VERSION 5.8 ;
BUSBITCHARS "[]" ;
DIVIDERCHAR "/" ;
UNITS
    DATABASE MICRONS 2000 ;
END UNITS

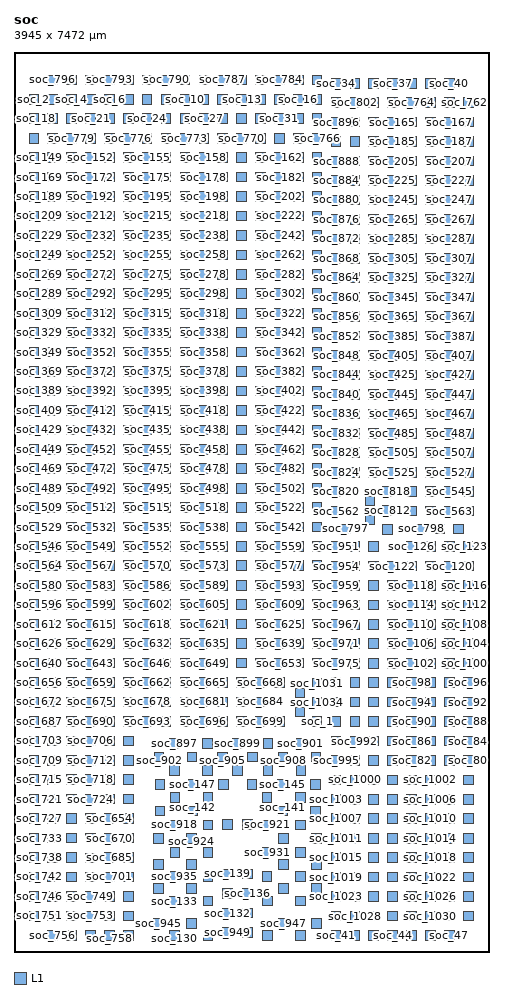
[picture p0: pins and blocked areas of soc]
MACRO soc
  FOREIGN soc 0 0 ;
  CLASS BLOCK ;
  SIZE 3945 BY 7472 ;
  PIN soc_1
    DIRECTION INOUT ;
    USE SIGNAL ;
    PORT
      LAYER L1 ;
        RECT  2476.881 1874.7005 2556.881 1954.7005 ;
    END
  END soc_1
  PIN soc_10
    DIRECTION INOUT ;
    USE SIGNAL ;
    PORT
      LAYER L1 ;
        RECT  1379.281 7039.1995 1459.281 7119.1995 ;
    END
  END soc_10
  PIN soc_100
    DIRECTION INOUT ;
    USE SIGNAL ;
    PORT
      LAYER L1 ;
        RECT  3731.281 2357.4025 3811.281 2437.4025 ;
    END
  END soc_100
  PIN soc_1000
    DIRECTION INOUT ;
    USE SIGNAL ;
    PORT
      LAYER L1 ;
        RECT  2790.481 1388.7545 2870.481 1468.7545 ;
    END
  END soc_1000
  PIN soc_1001
    DIRECTION INOUT ;
    USE SIGNAL ;
    PORT
      LAYER L1 ;
        RECT  2947.281 1388.7545 3027.281 1468.7545 ;
    END
  END soc_1001
  PIN soc_1002
    DIRECTION INOUT ;
    USE SIGNAL ;
    PORT
      LAYER L1 ;
        RECT  3417.681 1388.7545 3497.681 1468.7545 ;
    END
  END soc_1002
  PIN soc_1003
    DIRECTION INOUT ;
    USE SIGNAL ;
    PORT
      LAYER L1 ;
        RECT  2633.681 1227.3135 2713.681 1307.3135 ;
    END
  END soc_1003
  PIN soc_1004
    DIRECTION INOUT ;
    USE SIGNAL ;
    PORT
      LAYER L1 ;
        RECT  2790.481 1227.3135 2870.481 1307.3135 ;
    END
  END soc_1004
  PIN soc_1005
    DIRECTION INOUT ;
    USE SIGNAL ;
    PORT
      LAYER L1 ;
        RECT  2947.281 1227.3135 3027.281 1307.3135 ;
    END
  END soc_1005
  PIN soc_1006
    DIRECTION INOUT ;
    USE SIGNAL ;
    PORT
      LAYER L1 ;
        RECT  3417.681 1227.3135 3497.681 1307.3135 ;
    END
  END soc_1006
  PIN soc_1007
    DIRECTION INOUT ;
    USE SIGNAL ;
    PORT
      LAYER L1 ;
        RECT  2633.681 1065.872 2713.681 1145.872 ;
    END
  END soc_1007
  PIN soc_1008
    DIRECTION INOUT ;
    USE SIGNAL ;
    PORT
      LAYER L1 ;
        RECT  2790.481 1065.872 2870.481 1145.872 ;
    END
  END soc_1008
  PIN soc_1009
    DIRECTION INOUT ;
    USE SIGNAL ;
    PORT
      LAYER L1 ;
        RECT  2947.281 1065.872 3027.281 1145.872 ;
    END
  END soc_1009
  PIN soc_101
    DIRECTION INOUT ;
    USE SIGNAL ;
    PORT
      LAYER L1 ;
        RECT  3574.481 2357.4025 3654.481 2437.4025 ;
    END
  END soc_101
  PIN soc_1010
    DIRECTION INOUT ;
    USE SIGNAL ;
    PORT
      LAYER L1 ;
        RECT  3417.681 1065.872 3497.681 1145.872 ;
    END
  END soc_1010
  PIN soc_1011
    DIRECTION INOUT ;
    USE SIGNAL ;
    PORT
      LAYER L1 ;
        RECT  2633.681 904.431 2713.681 984.431 ;
    END
  END soc_1011
  PIN soc_1012
    DIRECTION INOUT ;
    USE SIGNAL ;
    PORT
      LAYER L1 ;
        RECT  2790.481 904.431 2870.481 984.431 ;
    END
  END soc_1012
  PIN soc_1013
    DIRECTION INOUT ;
    USE SIGNAL ;
    PORT
      LAYER L1 ;
        RECT  2947.281 904.431 3027.281 984.431 ;
    END
  END soc_1013
  PIN soc_1014
    DIRECTION INOUT ;
    USE SIGNAL ;
    PORT
      LAYER L1 ;
        RECT  3417.681 904.431 3497.681 984.431 ;
    END
  END soc_1014
  PIN soc_1015
    DIRECTION INOUT ;
    USE SIGNAL ;
    PORT
      LAYER L1 ;
        RECT  2633.681 742.9895 2713.681 822.9895 ;
    END
  END soc_1015
  PIN soc_1016
    DIRECTION INOUT ;
    USE SIGNAL ;
    PORT
      LAYER L1 ;
        RECT  2790.481 742.9895 2870.481 822.9895 ;
    END
  END soc_1016
  PIN soc_1017
    DIRECTION INOUT ;
    USE SIGNAL ;
    PORT
      LAYER L1 ;
        RECT  2947.281 742.9895 3027.281 822.9895 ;
    END
  END soc_1017
  PIN soc_1018
    DIRECTION INOUT ;
    USE SIGNAL ;
    PORT
      LAYER L1 ;
        RECT  3417.681 742.9895 3497.681 822.9895 ;
    END
  END soc_1018
  PIN soc_1019
    DIRECTION INOUT ;
    USE SIGNAL ;
    PORT
      LAYER L1 ;
        RECT  2633.681 581.5485 2713.681 661.5485 ;
    END
  END soc_1019
  PIN soc_102
    DIRECTION INOUT ;
    USE SIGNAL ;
    PORT
      LAYER L1 ;
        RECT  3260.881 2357.4025 3340.881 2437.4025 ;
    END
  END soc_102
  PIN soc_1020
    DIRECTION INOUT ;
    USE SIGNAL ;
    PORT
      LAYER L1 ;
        RECT  2790.481 581.5485 2870.481 661.5485 ;
    END
  END soc_1020
  PIN soc_1021
    DIRECTION INOUT ;
    USE SIGNAL ;
    PORT
      LAYER L1 ;
        RECT  2947.281 581.5485 3027.281 661.5485 ;
    END
  END soc_1021
  PIN soc_1022
    DIRECTION INOUT ;
    USE SIGNAL ;
    PORT
      LAYER L1 ;
        RECT  3417.681 581.5485 3497.681 661.5485 ;
    END
  END soc_1022
  PIN soc_1023
    DIRECTION INOUT ;
    USE SIGNAL ;
    PORT
      LAYER L1 ;
        RECT  2633.681 420.107 2713.681 500.107 ;
    END
  END soc_1023
  PIN soc_1024
    DIRECTION INOUT ;
    USE SIGNAL ;
    PORT
      LAYER L1 ;
        RECT  2790.481 420.107 2870.481 500.107 ;
    END
  END soc_1024
  PIN soc_1025
    DIRECTION INOUT ;
    USE SIGNAL ;
    PORT
      LAYER L1 ;
        RECT  2947.281 420.107 3027.281 500.107 ;
    END
  END soc_1025
  PIN soc_1026
    DIRECTION INOUT ;
    USE SIGNAL ;
    PORT
      LAYER L1 ;
        RECT  3417.681 420.107 3497.681 500.107 ;
    END
  END soc_1026
  PIN soc_1027
    DIRECTION INOUT ;
    USE SIGNAL ;
    PORT
      LAYER L1 ;
        RECT  2633.681 258.666 2713.681 338.666 ;
    END
  END soc_1027
  PIN soc_1028
    DIRECTION INOUT ;
    USE SIGNAL ;
    PORT
      LAYER L1 ;
        RECT  2790.481 258.666 2870.481 338.666 ;
    END
  END soc_1028
  PIN soc_1029
    DIRECTION INOUT ;
    USE SIGNAL ;
    PORT
      LAYER L1 ;
        RECT  2947.281 258.666 3027.281 338.666 ;
    END
  END soc_1029
  PIN soc_103
    DIRECTION INOUT ;
    USE SIGNAL ;
    PORT
      LAYER L1 ;
        RECT  3104.081 2357.4025 3184.081 2437.4025 ;
    END
  END soc_103
  PIN soc_1030
    DIRECTION INOUT ;
    USE SIGNAL ;
    PORT
      LAYER L1 ;
        RECT  3417.681 258.666 3497.681 338.666 ;
    END
  END soc_1030
  PIN soc_1031
    DIRECTION INOUT ;
    USE SIGNAL ;
    PORT
      LAYER L1 ;
        RECT  2476.881 2188.3005 2556.881 2268.3005 ;
    END
  END soc_1031
  PIN soc_1032
    DIRECTION INOUT ;
    USE SIGNAL ;
    PORT
      LAYER L1 ;
        RECT  2333.5325 2109.9005 2413.5325 2189.9005 ;
    END
  END soc_1032
  PIN soc_1033
    DIRECTION INOUT ;
    USE SIGNAL ;
    PORT
      LAYER L1 ;
        RECT  2333.5325 1953.1005 2413.5325 2033.1005 ;
    END
  END soc_1033
  PIN soc_1034
    DIRECTION INOUT ;
    USE SIGNAL ;
    PORT
      LAYER L1 ;
        RECT  2476.881 2031.5005 2556.881 2111.5005 ;
    END
  END soc_1034
  PIN soc_104
    DIRECTION INOUT ;
    USE SIGNAL ;
    PORT
      LAYER L1 ;
        RECT  3731.281 2518.8435 3811.281 2598.8435 ;
    END
  END soc_104
  PIN soc_105
    DIRECTION INOUT ;
    USE SIGNAL ;
    PORT
      LAYER L1 ;
        RECT  3574.481 2518.8435 3654.481 2598.8435 ;
    END
  END soc_105
  PIN soc_106
    DIRECTION INOUT ;
    USE SIGNAL ;
    PORT
      LAYER L1 ;
        RECT  3260.881 2518.8435 3340.881 2598.8435 ;
    END
  END soc_106
  PIN soc_107
    DIRECTION INOUT ;
    USE SIGNAL ;
    PORT
      LAYER L1 ;
        RECT  3104.081 2518.8435 3184.081 2598.8435 ;
    END
  END soc_107
  PIN soc_108
    DIRECTION INOUT ;
    USE SIGNAL ;
    PORT
      LAYER L1 ;
        RECT  3731.281 2680.285 3811.281 2760.285 ;
    END
  END soc_108
  PIN soc_109
    DIRECTION INOUT ;
    USE SIGNAL ;
    PORT
      LAYER L1 ;
        RECT  3574.481 2680.285 3654.481 2760.285 ;
    END
  END soc_109
  PIN soc_11
    DIRECTION INOUT ;
    USE SIGNAL ;
    PORT
      LAYER L1 ;
        RECT  1536.081 7039.1995 1616.081 7119.1995 ;
    END
  END soc_11
  PIN soc_110
    DIRECTION INOUT ;
    USE SIGNAL ;
    PORT
      LAYER L1 ;
        RECT  3260.881 2680.285 3340.881 2760.285 ;
    END
  END soc_110
  PIN soc_111
    DIRECTION INOUT ;
    USE SIGNAL ;
    PORT
      LAYER L1 ;
        RECT  3104.081 2680.285 3184.081 2760.285 ;
    END
  END soc_111
  PIN soc_112
    DIRECTION INOUT ;
    USE SIGNAL ;
    PORT
      LAYER L1 ;
        RECT  3731.281 2841.7265 3811.281 2921.7265 ;
    END
  END soc_112
  PIN soc_113
    DIRECTION INOUT ;
    USE SIGNAL ;
    PORT
      LAYER L1 ;
        RECT  3574.481 2841.7265 3654.481 2921.7265 ;
    END
  END soc_113
  PIN soc_114
    DIRECTION INOUT ;
    USE SIGNAL ;
    PORT
      LAYER L1 ;
        RECT  3260.881 2841.7265 3340.881 2921.7265 ;
    END
  END soc_114
  PIN soc_115
    DIRECTION INOUT ;
    USE SIGNAL ;
    PORT
      LAYER L1 ;
        RECT  3104.081 2841.7265 3184.081 2921.7265 ;
    END
  END soc_115
  PIN soc_116
    DIRECTION INOUT ;
    USE SIGNAL ;
    PORT
      LAYER L1 ;
        RECT  3731.281 3003.1675 3811.281 3083.1675 ;
    END
  END soc_116
  PIN soc_117
    DIRECTION INOUT ;
    USE SIGNAL ;
    PORT
      LAYER L1 ;
        RECT  3574.481 3003.1675 3654.481 3083.1675 ;
    END
  END soc_117
  PIN soc_118
    DIRECTION INOUT ;
    USE SIGNAL ;
    PORT
      LAYER L1 ;
        RECT  3260.881 3003.1675 3340.881 3083.1675 ;
    END
  END soc_118
  PIN soc_119
    DIRECTION INOUT ;
    USE SIGNAL ;
    PORT
      LAYER L1 ;
        RECT  3104.081 3003.1675 3184.081 3083.1675 ;
    END
  END soc_119
  PIN soc_12
    DIRECTION INOUT ;
    USE SIGNAL ;
    PORT
      LAYER L1 ;
        RECT  1692.881 7039.1995 1772.881 7119.1995 ;
    END
  END soc_12
  PIN soc_120
    DIRECTION INOUT ;
    USE SIGNAL ;
    PORT
      LAYER L1 ;
        RECT  3574.481 3164.609 3654.481 3244.609 ;
    END
  END soc_120
  PIN soc_121
    DIRECTION INOUT ;
    USE SIGNAL ;
    PORT
      LAYER L1 ;
        RECT  3260.881 3164.609 3340.881 3244.609 ;
    END
  END soc_121
  PIN soc_122
    DIRECTION INOUT ;
    USE SIGNAL ;
    PORT
      LAYER L1 ;
        RECT  3104.081 3164.609 3184.081 3244.609 ;
    END
  END soc_122
  PIN soc_123
    DIRECTION INOUT ;
    USE SIGNAL ;
    PORT
      LAYER L1 ;
        RECT  3731.281 3326.05 3811.281 3406.05 ;
    END
  END soc_123
  PIN soc_124
    DIRECTION INOUT ;
    USE SIGNAL ;
    PORT
      LAYER L1 ;
        RECT  3574.481 3326.05 3654.481 3406.05 ;
    END
  END soc_124
  PIN soc_125
    DIRECTION INOUT ;
    USE SIGNAL ;
    PORT
      LAYER L1 ;
        RECT  3417.681 3326.05 3497.681 3406.05 ;
    END
  END soc_125
  PIN soc_126
    DIRECTION INOUT ;
    USE SIGNAL ;
    PORT
      LAYER L1 ;
        RECT  3260.881 3326.05 3340.881 3406.05 ;
    END
  END soc_126
  PIN soc_127
    DIRECTION INOUT ;
    USE SIGNAL ;
    PORT
      LAYER L1 ;
        RECT  2337.637 98.8385 2417.637 178.8385 ;
    END
  END soc_127
  PIN soc_128
    DIRECTION INOUT ;
    USE SIGNAL ;
    PORT
      LAYER L1 ;
        RECT  2063.237 98.8385 2143.237 178.8385 ;
    END
  END soc_128
  PIN soc_129
    DIRECTION INOUT ;
    USE SIGNAL ;
    PORT
      LAYER L1 ;
        RECT  1569.317 98.8385 1649.317 178.8385 ;
    END
  END soc_129
  PIN soc_13
    DIRECTION INOUT ;
    USE SIGNAL ;
    PORT
      LAYER L1 ;
        RECT  1849.681 7039.1995 1929.681 7119.1995 ;
    END
  END soc_13
  PIN soc_130
    DIRECTION INOUT ;
    USE SIGNAL ;
    PORT
      LAYER L1 ;
        RECT  1294.917 98.8385 1374.917 178.8385 ;
    END
  END soc_130
  PIN soc_131
    DIRECTION INOUT ;
    USE SIGNAL ;
    PORT
      LAYER L1 ;
        RECT  1898.597 282.663 1978.597 362.663 ;
    END
  END soc_131
  PIN soc_132
    DIRECTION INOUT ;
    USE SIGNAL ;
    PORT
      LAYER L1 ;
        RECT  1733.957 282.663 1813.957 362.663 ;
    END
  END soc_132
  PIN soc_133
    DIRECTION INOUT ;
    USE SIGNAL ;
    PORT
      LAYER L1 ;
        RECT  1294.917 383.1015 1374.917 463.1015 ;
    END
  END soc_133
  PIN soc_134
    DIRECTION INOUT ;
    USE SIGNAL ;
    PORT
      LAYER L1 ;
        RECT  2337.637 383.1015 2417.637 463.1015 ;
    END
  END soc_134
  PIN soc_135
    DIRECTION INOUT ;
    USE SIGNAL ;
    PORT
      LAYER L1 ;
        RECT  2063.237 383.1015 2143.237 463.1015 ;
    END
  END soc_135
  PIN soc_136
    DIRECTION INOUT ;
    USE SIGNAL ;
    PORT
      LAYER L1 ;
        RECT  1898.597 445.343 1978.597 525.343 ;
    END
  END soc_136
  PIN soc_137
    DIRECTION INOUT ;
    USE SIGNAL ;
    PORT
      LAYER L1 ;
        RECT  1733.957 445.343 1813.957 525.343 ;
    END
  END soc_137
  PIN soc_138
    DIRECTION INOUT ;
    USE SIGNAL ;
    PORT
      LAYER L1 ;
        RECT  1569.317 383.1015 1649.317 463.1015 ;
    END
  END soc_138
  PIN soc_139
    DIRECTION INOUT ;
    USE SIGNAL ;
    PORT
      LAYER L1 ;
        RECT  1733.957 608.023 1813.957 688.023 ;
    END
  END soc_139
  PIN soc_14
    DIRECTION INOUT ;
    USE SIGNAL ;
    PORT
      LAYER L1 ;
        RECT  2006.481 7039.1995 2086.481 7119.1995 ;
    END
  END soc_14
  PIN soc_140
    DIRECTION INOUT ;
    USE SIGNAL ;
    PORT
      LAYER L1 ;
        RECT  2461.244 1130.4435 2541.244 1210.4435 ;
    END
  END soc_140
  PIN soc_141
    DIRECTION INOUT ;
    USE SIGNAL ;
    PORT
      LAYER L1 ;
        RECT  2186.844 1130.4435 2266.844 1210.4435 ;
    END
  END soc_141
  PIN soc_142
    DIRECTION INOUT ;
    USE SIGNAL ;
    PORT
      LAYER L1 ;
        RECT  1445.7095 1130.4435 1525.7095 1210.4435 ;
    END
  END soc_142
  PIN soc_143
    DIRECTION INOUT ;
    USE SIGNAL ;
    PORT
      LAYER L1 ;
        RECT  1171.3095 1130.4435 1251.3095 1210.4435 ;
    END
  END soc_143
  PIN soc_144
    DIRECTION INOUT ;
    USE SIGNAL ;
    PORT
      LAYER L1 ;
        RECT  2461.244 1351.3195 2541.244 1431.3195 ;
    END
  END soc_144
  PIN soc_145
    DIRECTION INOUT ;
    USE SIGNAL ;
    PORT
      LAYER L1 ;
        RECT  2186.844 1351.3195 2266.844 1431.3195 ;
    END
  END soc_145
  PIN soc_146
    DIRECTION INOUT ;
    USE SIGNAL ;
    PORT
      LAYER L1 ;
        RECT  1934.8645 1351.3195 2014.8645 1431.3195 ;
    END
  END soc_146
  PIN soc_147
    DIRECTION INOUT ;
    USE SIGNAL ;
    PORT
      LAYER L1 ;
        RECT  1445.7095 1351.3195 1525.7095 1431.3195 ;
    END
  END soc_147
  PIN soc_148
    DIRECTION INOUT ;
    USE SIGNAL ;
    PORT
      LAYER L1 ;
        RECT  1171.3095 1351.3195 1251.3095 1431.3195 ;
    END
  END soc_148
  PIN soc_149
    DIRECTION INOUT ;
    USE SIGNAL ;
    PORT
      LAYER L1 ;
        RECT  124.881 6554.8755 204.881 6634.8755 ;
    END
  END soc_149
  PIN soc_15
    DIRECTION INOUT ;
    USE SIGNAL ;
    PORT
      LAYER L1 ;
        RECT  2163.281 7039.1995 2243.281 7119.1995 ;
    END
  END soc_15
  PIN soc_150
    DIRECTION INOUT ;
    USE SIGNAL ;
    PORT
      LAYER L1 ;
        RECT  281.681 6554.8755 361.681 6634.8755 ;
    END
  END soc_150
  PIN soc_151
    DIRECTION INOUT ;
    USE SIGNAL ;
    PORT
      LAYER L1 ;
        RECT  438.481 6554.8755 518.481 6634.8755 ;
    END
  END soc_151
  PIN soc_152
    DIRECTION INOUT ;
    USE SIGNAL ;
    PORT
      LAYER L1 ;
        RECT  595.281 6554.8755 675.281 6634.8755 ;
    END
  END soc_152
  PIN soc_153
    DIRECTION INOUT ;
    USE SIGNAL ;
    PORT
      LAYER L1 ;
        RECT  752.081 6554.8755 832.081 6634.8755 ;
    END
  END soc_153
  PIN soc_154
    DIRECTION INOUT ;
    USE SIGNAL ;
    PORT
      LAYER L1 ;
        RECT  908.881 6554.8755 988.881 6634.8755 ;
    END
  END soc_154
  PIN soc_155
    DIRECTION INOUT ;
    USE SIGNAL ;
    PORT
      LAYER L1 ;
        RECT  1065.681 6554.8755 1145.681 6634.8755 ;
    END
  END soc_155
  PIN soc_156
    DIRECTION INOUT ;
    USE SIGNAL ;
    PORT
      LAYER L1 ;
        RECT  1222.481 6554.8755 1302.481 6634.8755 ;
    END
  END soc_156
  PIN soc_157
    DIRECTION INOUT ;
    USE SIGNAL ;
    PORT
      LAYER L1 ;
        RECT  1379.281 6554.8755 1459.281 6634.8755 ;
    END
  END soc_157
  PIN soc_158
    DIRECTION INOUT ;
    USE SIGNAL ;
    PORT
      LAYER L1 ;
        RECT  1536.081 6554.8755 1616.081 6634.8755 ;
    END
  END soc_158
  PIN soc_159
    DIRECTION INOUT ;
    USE SIGNAL ;
    PORT
      LAYER L1 ;
        RECT  1692.881 6554.8755 1772.881 6634.8755 ;
    END
  END soc_159
  PIN soc_16
    DIRECTION INOUT ;
    USE SIGNAL ;
    PORT
      LAYER L1 ;
        RECT  2320.081 7039.1995 2400.081 7119.1995 ;
    END
  END soc_16
  PIN soc_160
    DIRECTION INOUT ;
    USE SIGNAL ;
    PORT
      LAYER L1 ;
        RECT  1849.681 6554.8755 1929.681 6634.8755 ;
    END
  END soc_160
  PIN soc_161
    DIRECTION INOUT ;
    USE SIGNAL ;
    PORT
      LAYER L1 ;
        RECT  2006.481 6554.8755 2086.481 6634.8755 ;
    END
  END soc_161
  PIN soc_162
    DIRECTION INOUT ;
    USE SIGNAL ;
    PORT
      LAYER L1 ;
        RECT  2163.281 6554.8755 2243.281 6634.8755 ;
    END
  END soc_162
  PIN soc_163
    DIRECTION INOUT ;
    USE SIGNAL ;
    PORT
      LAYER L1 ;
        RECT  2320.081 6554.8755 2400.081 6634.8755 ;
    END
  END soc_163
  PIN soc_164
    DIRECTION INOUT ;
    USE SIGNAL ;
    PORT
      LAYER L1 ;
        RECT  2476.881 6554.8755 2556.881 6634.8755 ;
    END
  END soc_164
  PIN soc_165
    DIRECTION INOUT ;
    USE SIGNAL ;
    PORT
      LAYER L1 ;
        RECT  3104.081 6849.4225 3184.081 6929.4225 ;
    END
  END soc_165
  PIN soc_166
    DIRECTION INOUT ;
    USE SIGNAL ;
    PORT
      LAYER L1 ;
        RECT  3260.881 6849.4225 3340.881 6929.4225 ;
    END
  END soc_166
  PIN soc_167
    DIRECTION INOUT ;
    USE SIGNAL ;
    PORT
      LAYER L1 ;
        RECT  3574.481 6849.4225 3654.481 6929.4225 ;
    END
  END soc_167
  PIN soc_168
    DIRECTION INOUT ;
    USE SIGNAL ;
    PORT
      LAYER L1 ;
        RECT  3731.281 6849.4225 3811.281 6929.4225 ;
    END
  END soc_168
  PIN soc_169
    DIRECTION INOUT ;
    USE SIGNAL ;
    PORT
      LAYER L1 ;
        RECT  124.881 6393.4345 204.881 6473.4345 ;
    END
  END soc_169
  PIN soc_17
    DIRECTION INOUT ;
    USE SIGNAL ;
    PORT
      LAYER L1 ;
        RECT  2476.881 7039.1995 2556.881 7119.1995 ;
    END
  END soc_17
  PIN soc_170
    DIRECTION INOUT ;
    USE SIGNAL ;
    PORT
      LAYER L1 ;
        RECT  281.681 6393.4345 361.681 6473.4345 ;
    END
  END soc_170
  PIN soc_171
    DIRECTION INOUT ;
    USE SIGNAL ;
    PORT
      LAYER L1 ;
        RECT  438.481 6393.4345 518.481 6473.4345 ;
    END
  END soc_171
  PIN soc_172
    DIRECTION INOUT ;
    USE SIGNAL ;
    PORT
      LAYER L1 ;
        RECT  595.281 6393.4345 675.281 6473.4345 ;
    END
  END soc_172
  PIN soc_173
    DIRECTION INOUT ;
    USE SIGNAL ;
    PORT
      LAYER L1 ;
        RECT  752.081 6393.4345 832.081 6473.4345 ;
    END
  END soc_173
  PIN soc_174
    DIRECTION INOUT ;
    USE SIGNAL ;
    PORT
      LAYER L1 ;
        RECT  908.881 6393.4345 988.881 6473.4345 ;
    END
  END soc_174
  PIN soc_175
    DIRECTION INOUT ;
    USE SIGNAL ;
    PORT
      LAYER L1 ;
        RECT  1065.681 6393.4345 1145.681 6473.4345 ;
    END
  END soc_175
  PIN soc_176
    DIRECTION INOUT ;
    USE SIGNAL ;
    PORT
      LAYER L1 ;
        RECT  1222.481 6393.4345 1302.481 6473.4345 ;
    END
  END soc_176
  PIN soc_177
    DIRECTION INOUT ;
    USE SIGNAL ;
    PORT
      LAYER L1 ;
        RECT  1379.281 6393.4345 1459.281 6473.4345 ;
    END
  END soc_177
  PIN soc_178
    DIRECTION INOUT ;
    USE SIGNAL ;
    PORT
      LAYER L1 ;
        RECT  1536.081 6393.4345 1616.081 6473.4345 ;
    END
  END soc_178
  PIN soc_179
    DIRECTION INOUT ;
    USE SIGNAL ;
    PORT
      LAYER L1 ;
        RECT  1692.881 6393.4345 1772.881 6473.4345 ;
    END
  END soc_179
  PIN soc_18
    DIRECTION INOUT ;
    USE SIGNAL ;
    PORT
      LAYER L1 ;
        RECT  124.881 6877.7585 204.881 6957.7585 ;
    END
  END soc_18
  PIN soc_180
    DIRECTION INOUT ;
    USE SIGNAL ;
    PORT
      LAYER L1 ;
        RECT  1849.681 6393.4345 1929.681 6473.4345 ;
    END
  END soc_180
  PIN soc_181
    DIRECTION INOUT ;
    USE SIGNAL ;
    PORT
      LAYER L1 ;
        RECT  2006.481 6393.4345 2086.481 6473.4345 ;
    END
  END soc_181
  PIN soc_182
    DIRECTION INOUT ;
    USE SIGNAL ;
    PORT
      LAYER L1 ;
        RECT  2163.281 6393.4345 2243.281 6473.4345 ;
    END
  END soc_182
  PIN soc_183
    DIRECTION INOUT ;
    USE SIGNAL ;
    PORT
      LAYER L1 ;
        RECT  2320.081 6393.4345 2400.081 6473.4345 ;
    END
  END soc_183
  PIN soc_184
    DIRECTION INOUT ;
    USE SIGNAL ;
    PORT
      LAYER L1 ;
        RECT  2476.881 6393.4345 2556.881 6473.4345 ;
    END
  END soc_184
  PIN soc_185
    DIRECTION INOUT ;
    USE SIGNAL ;
    PORT
      LAYER L1 ;
        RECT  3104.081 6687.9815 3184.081 6767.9815 ;
    END
  END soc_185
  PIN soc_186
    DIRECTION INOUT ;
    USE SIGNAL ;
    PORT
      LAYER L1 ;
        RECT  3260.881 6687.9815 3340.881 6767.9815 ;
    END
  END soc_186
  PIN soc_187
    DIRECTION INOUT ;
    USE SIGNAL ;
    PORT
      LAYER L1 ;
        RECT  3574.481 6687.9815 3654.481 6767.9815 ;
    END
  END soc_187
  PIN soc_188
    DIRECTION INOUT ;
    USE SIGNAL ;
    PORT
      LAYER L1 ;
        RECT  3731.281 6687.9815 3811.281 6767.9815 ;
    END
  END soc_188
  PIN soc_189
    DIRECTION INOUT ;
    USE SIGNAL ;
    PORT
      LAYER L1 ;
        RECT  124.881 6231.993 204.881 6311.993 ;
    END
  END soc_189
  PIN soc_19
    DIRECTION INOUT ;
    USE SIGNAL ;
    PORT
      LAYER L1 ;
        RECT  281.681 6877.7585 361.681 6957.7585 ;
    END
  END soc_19
  PIN soc_190
    DIRECTION INOUT ;
    USE SIGNAL ;
    PORT
      LAYER L1 ;
        RECT  281.681 6231.993 361.681 6311.993 ;
    END
  END soc_190
  PIN soc_191
    DIRECTION INOUT ;
    USE SIGNAL ;
    PORT
      LAYER L1 ;
        RECT  438.481 6231.993 518.481 6311.993 ;
    END
  END soc_191
  PIN soc_192
    DIRECTION INOUT ;
    USE SIGNAL ;
    PORT
      LAYER L1 ;
        RECT  595.281 6231.993 675.281 6311.993 ;
    END
  END soc_192
  PIN soc_193
    DIRECTION INOUT ;
    USE SIGNAL ;
    PORT
      LAYER L1 ;
        RECT  752.081 6231.993 832.081 6311.993 ;
    END
  END soc_193
  PIN soc_194
    DIRECTION INOUT ;
    USE SIGNAL ;
    PORT
      LAYER L1 ;
        RECT  908.881 6231.993 988.881 6311.993 ;
    END
  END soc_194
  PIN soc_195
    DIRECTION INOUT ;
    USE SIGNAL ;
    PORT
      LAYER L1 ;
        RECT  1065.681 6231.993 1145.681 6311.993 ;
    END
  END soc_195
  PIN soc_196
    DIRECTION INOUT ;
    USE SIGNAL ;
    PORT
      LAYER L1 ;
        RECT  1222.481 6231.993 1302.481 6311.993 ;
    END
  END soc_196
  PIN soc_197
    DIRECTION INOUT ;
    USE SIGNAL ;
    PORT
      LAYER L1 ;
        RECT  1379.281 6231.993 1459.281 6311.993 ;
    END
  END soc_197
  PIN soc_198
    DIRECTION INOUT ;
    USE SIGNAL ;
    PORT
      LAYER L1 ;
        RECT  1536.081 6231.993 1616.081 6311.993 ;
    END
  END soc_198
  PIN soc_199
    DIRECTION INOUT ;
    USE SIGNAL ;
    PORT
      LAYER L1 ;
        RECT  1692.881 6231.993 1772.881 6311.993 ;
    END
  END soc_199
  PIN soc_2
    DIRECTION INOUT ;
    USE SIGNAL ;
    PORT
      LAYER L1 ;
        RECT  124.881 7039.1995 204.881 7119.1995 ;
    END
  END soc_2
  PIN soc_20
    DIRECTION INOUT ;
    USE SIGNAL ;
    PORT
      LAYER L1 ;
        RECT  438.481 6877.7585 518.481 6957.7585 ;
    END
  END soc_20
  PIN soc_200
    DIRECTION INOUT ;
    USE SIGNAL ;
    PORT
      LAYER L1 ;
        RECT  1849.681 6231.993 1929.681 6311.993 ;
    END
  END soc_200
  PIN soc_201
    DIRECTION INOUT ;
    USE SIGNAL ;
    PORT
      LAYER L1 ;
        RECT  2006.481 6231.993 2086.481 6311.993 ;
    END
  END soc_201
  PIN soc_202
    DIRECTION INOUT ;
    USE SIGNAL ;
    PORT
      LAYER L1 ;
        RECT  2163.281 6231.993 2243.281 6311.993 ;
    END
  END soc_202
  PIN soc_203
    DIRECTION INOUT ;
    USE SIGNAL ;
    PORT
      LAYER L1 ;
        RECT  2320.081 6231.993 2400.081 6311.993 ;
    END
  END soc_203
  PIN soc_204
    DIRECTION INOUT ;
    USE SIGNAL ;
    PORT
      LAYER L1 ;
        RECT  2476.881 6231.993 2556.881 6311.993 ;
    END
  END soc_204
  PIN soc_205
    DIRECTION INOUT ;
    USE SIGNAL ;
    PORT
      LAYER L1 ;
        RECT  3104.081 6526.54 3184.081 6606.54 ;
    END
  END soc_205
  PIN soc_206
    DIRECTION INOUT ;
    USE SIGNAL ;
    PORT
      LAYER L1 ;
        RECT  3260.881 6526.54 3340.881 6606.54 ;
    END
  END soc_206
  PIN soc_207
    DIRECTION INOUT ;
    USE SIGNAL ;
    PORT
      LAYER L1 ;
        RECT  3574.481 6526.54 3654.481 6606.54 ;
    END
  END soc_207
  PIN soc_208
    DIRECTION INOUT ;
    USE SIGNAL ;
    PORT
      LAYER L1 ;
        RECT  3731.281 6526.54 3811.281 6606.54 ;
    END
  END soc_208
  PIN soc_209
    DIRECTION INOUT ;
    USE SIGNAL ;
    PORT
      LAYER L1 ;
        RECT  124.881 6070.552 204.881 6150.552 ;
    END
  END soc_209
  PIN soc_21
    DIRECTION INOUT ;
    USE SIGNAL ;
    PORT
      LAYER L1 ;
        RECT  595.281 6877.7585 675.281 6957.7585 ;
    END
  END soc_21
  PIN soc_210
    DIRECTION INOUT ;
    USE SIGNAL ;
    PORT
      LAYER L1 ;
        RECT  281.681 6070.552 361.681 6150.552 ;
    END
  END soc_210
  PIN soc_211
    DIRECTION INOUT ;
    USE SIGNAL ;
    PORT
      LAYER L1 ;
        RECT  438.481 6070.552 518.481 6150.552 ;
    END
  END soc_211
  PIN soc_212
    DIRECTION INOUT ;
    USE SIGNAL ;
    PORT
      LAYER L1 ;
        RECT  595.281 6070.552 675.281 6150.552 ;
    END
  END soc_212
  PIN soc_213
    DIRECTION INOUT ;
    USE SIGNAL ;
    PORT
      LAYER L1 ;
        RECT  752.081 6070.552 832.081 6150.552 ;
    END
  END soc_213
  PIN soc_214
    DIRECTION INOUT ;
    USE SIGNAL ;
    PORT
      LAYER L1 ;
        RECT  908.881 6070.552 988.881 6150.552 ;
    END
  END soc_214
  PIN soc_215
    DIRECTION INOUT ;
    USE SIGNAL ;
    PORT
      LAYER L1 ;
        RECT  1065.681 6070.552 1145.681 6150.552 ;
    END
  END soc_215
  PIN soc_216
    DIRECTION INOUT ;
    USE SIGNAL ;
    PORT
      LAYER L1 ;
        RECT  1222.481 6070.552 1302.481 6150.552 ;
    END
  END soc_216
  PIN soc_217
    DIRECTION INOUT ;
    USE SIGNAL ;
    PORT
      LAYER L1 ;
        RECT  1379.281 6070.552 1459.281 6150.552 ;
    END
  END soc_217
  PIN soc_218
    DIRECTION INOUT ;
    USE SIGNAL ;
    PORT
      LAYER L1 ;
        RECT  1536.081 6070.552 1616.081 6150.552 ;
    END
  END soc_218
  PIN soc_219
    DIRECTION INOUT ;
    USE SIGNAL ;
    PORT
      LAYER L1 ;
        RECT  1692.881 6070.552 1772.881 6150.552 ;
    END
  END soc_219
  PIN soc_22
    DIRECTION INOUT ;
    USE SIGNAL ;
    PORT
      LAYER L1 ;
        RECT  752.081 6877.7585 832.081 6957.7585 ;
    END
  END soc_22
  PIN soc_220
    DIRECTION INOUT ;
    USE SIGNAL ;
    PORT
      LAYER L1 ;
        RECT  1849.681 6070.552 1929.681 6150.552 ;
    END
  END soc_220
  PIN soc_221
    DIRECTION INOUT ;
    USE SIGNAL ;
    PORT
      LAYER L1 ;
        RECT  2006.481 6070.552 2086.481 6150.552 ;
    END
  END soc_221
  PIN soc_222
    DIRECTION INOUT ;
    USE SIGNAL ;
    PORT
      LAYER L1 ;
        RECT  2163.281 6070.552 2243.281 6150.552 ;
    END
  END soc_222
  PIN soc_223
    DIRECTION INOUT ;
    USE SIGNAL ;
    PORT
      LAYER L1 ;
        RECT  2320.081 6070.552 2400.081 6150.552 ;
    END
  END soc_223
  PIN soc_224
    DIRECTION INOUT ;
    USE SIGNAL ;
    PORT
      LAYER L1 ;
        RECT  2476.881 6070.552 2556.881 6150.552 ;
    END
  END soc_224
  PIN soc_225
    DIRECTION INOUT ;
    USE SIGNAL ;
    PORT
      LAYER L1 ;
        RECT  3104.081 6365.0985 3184.081 6445.0985 ;
    END
  END soc_225
  PIN soc_226
    DIRECTION INOUT ;
    USE SIGNAL ;
    PORT
      LAYER L1 ;
        RECT  3260.881 6365.0985 3340.881 6445.0985 ;
    END
  END soc_226
  PIN soc_227
    DIRECTION INOUT ;
    USE SIGNAL ;
    PORT
      LAYER L1 ;
        RECT  3574.481 6365.0985 3654.481 6445.0985 ;
    END
  END soc_227
  PIN soc_228
    DIRECTION INOUT ;
    USE SIGNAL ;
    PORT
      LAYER L1 ;
        RECT  3731.281 6365.0985 3811.281 6445.0985 ;
    END
  END soc_228
  PIN soc_229
    DIRECTION INOUT ;
    USE SIGNAL ;
    PORT
      LAYER L1 ;
        RECT  124.881 5909.1105 204.881 5989.1105 ;
    END
  END soc_229
  PIN soc_23
    DIRECTION INOUT ;
    USE SIGNAL ;
    PORT
      LAYER L1 ;
        RECT  908.881 6877.7585 988.881 6957.7585 ;
    END
  END soc_23
  PIN soc_230
    DIRECTION INOUT ;
    USE SIGNAL ;
    PORT
      LAYER L1 ;
        RECT  281.681 5909.1105 361.681 5989.1105 ;
    END
  END soc_230
  PIN soc_231
    DIRECTION INOUT ;
    USE SIGNAL ;
    PORT
      LAYER L1 ;
        RECT  438.481 5909.1105 518.481 5989.1105 ;
    END
  END soc_231
  PIN soc_232
    DIRECTION INOUT ;
    USE SIGNAL ;
    PORT
      LAYER L1 ;
        RECT  595.281 5909.1105 675.281 5989.1105 ;
    END
  END soc_232
  PIN soc_233
    DIRECTION INOUT ;
    USE SIGNAL ;
    PORT
      LAYER L1 ;
        RECT  752.081 5909.1105 832.081 5989.1105 ;
    END
  END soc_233
  PIN soc_234
    DIRECTION INOUT ;
    USE SIGNAL ;
    PORT
      LAYER L1 ;
        RECT  908.881 5909.1105 988.881 5989.1105 ;
    END
  END soc_234
  PIN soc_235
    DIRECTION INOUT ;
    USE SIGNAL ;
    PORT
      LAYER L1 ;
        RECT  1065.681 5909.1105 1145.681 5989.1105 ;
    END
  END soc_235
  PIN soc_236
    DIRECTION INOUT ;
    USE SIGNAL ;
    PORT
      LAYER L1 ;
        RECT  1222.481 5909.1105 1302.481 5989.1105 ;
    END
  END soc_236
  PIN soc_237
    DIRECTION INOUT ;
    USE SIGNAL ;
    PORT
      LAYER L1 ;
        RECT  1379.281 5909.1105 1459.281 5989.1105 ;
    END
  END soc_237
  PIN soc_238
    DIRECTION INOUT ;
    USE SIGNAL ;
    PORT
      LAYER L1 ;
        RECT  1536.081 5909.1105 1616.081 5989.1105 ;
    END
  END soc_238
  PIN soc_239
    DIRECTION INOUT ;
    USE SIGNAL ;
    PORT
      LAYER L1 ;
        RECT  1692.881 5909.1105 1772.881 5989.1105 ;
    END
  END soc_239
  PIN soc_24
    DIRECTION INOUT ;
    USE SIGNAL ;
    PORT
      LAYER L1 ;
        RECT  1065.681 6877.7585 1145.681 6957.7585 ;
    END
  END soc_24
  PIN soc_240
    DIRECTION INOUT ;
    USE SIGNAL ;
    PORT
      LAYER L1 ;
        RECT  1849.681 5909.1105 1929.681 5989.1105 ;
    END
  END soc_240
  PIN soc_241
    DIRECTION INOUT ;
    USE SIGNAL ;
    PORT
      LAYER L1 ;
        RECT  2006.481 5909.1105 2086.481 5989.1105 ;
    END
  END soc_241
  PIN soc_242
    DIRECTION INOUT ;
    USE SIGNAL ;
    PORT
      LAYER L1 ;
        RECT  2163.281 5909.1105 2243.281 5989.1105 ;
    END
  END soc_242
  PIN soc_243
    DIRECTION INOUT ;
    USE SIGNAL ;
    PORT
      LAYER L1 ;
        RECT  2320.081 5909.1105 2400.081 5989.1105 ;
    END
  END soc_243
  PIN soc_244
    DIRECTION INOUT ;
    USE SIGNAL ;
    PORT
      LAYER L1 ;
        RECT  2476.881 5909.1105 2556.881 5989.1105 ;
    END
  END soc_244
  PIN soc_245
    DIRECTION INOUT ;
    USE SIGNAL ;
    PORT
      LAYER L1 ;
        RECT  3104.081 6203.6575 3184.081 6283.6575 ;
    END
  END soc_245
  PIN soc_246
    DIRECTION INOUT ;
    USE SIGNAL ;
    PORT
      LAYER L1 ;
        RECT  3260.881 6203.6575 3340.881 6283.6575 ;
    END
  END soc_246
  PIN soc_247
    DIRECTION INOUT ;
    USE SIGNAL ;
    PORT
      LAYER L1 ;
        RECT  3574.481 6203.6575 3654.481 6283.6575 ;
    END
  END soc_247
  PIN soc_248
    DIRECTION INOUT ;
    USE SIGNAL ;
    PORT
      LAYER L1 ;
        RECT  3731.281 6203.6575 3811.281 6283.6575 ;
    END
  END soc_248
  PIN soc_249
    DIRECTION INOUT ;
    USE SIGNAL ;
    PORT
      LAYER L1 ;
        RECT  124.881 5747.6695 204.881 5827.6695 ;
    END
  END soc_249
  PIN soc_25
    DIRECTION INOUT ;
    USE SIGNAL ;
    PORT
      LAYER L1 ;
        RECT  1222.481 6877.7585 1302.481 6957.7585 ;
    END
  END soc_25
  PIN soc_250
    DIRECTION INOUT ;
    USE SIGNAL ;
    PORT
      LAYER L1 ;
        RECT  281.681 5747.6695 361.681 5827.6695 ;
    END
  END soc_250
  PIN soc_251
    DIRECTION INOUT ;
    USE SIGNAL ;
    PORT
      LAYER L1 ;
        RECT  438.481 5747.6695 518.481 5827.6695 ;
    END
  END soc_251
  PIN soc_252
    DIRECTION INOUT ;
    USE SIGNAL ;
    PORT
      LAYER L1 ;
        RECT  595.281 5747.6695 675.281 5827.6695 ;
    END
  END soc_252
  PIN soc_253
    DIRECTION INOUT ;
    USE SIGNAL ;
    PORT
      LAYER L1 ;
        RECT  752.081 5747.6695 832.081 5827.6695 ;
    END
  END soc_253
  PIN soc_254
    DIRECTION INOUT ;
    USE SIGNAL ;
    PORT
      LAYER L1 ;
        RECT  908.881 5747.6695 988.881 5827.6695 ;
    END
  END soc_254
  PIN soc_255
    DIRECTION INOUT ;
    USE SIGNAL ;
    PORT
      LAYER L1 ;
        RECT  1065.681 5747.6695 1145.681 5827.6695 ;
    END
  END soc_255
  PIN soc_256
    DIRECTION INOUT ;
    USE SIGNAL ;
    PORT
      LAYER L1 ;
        RECT  1222.481 5747.6695 1302.481 5827.6695 ;
    END
  END soc_256
  PIN soc_257
    DIRECTION INOUT ;
    USE SIGNAL ;
    PORT
      LAYER L1 ;
        RECT  1379.281 5747.6695 1459.281 5827.6695 ;
    END
  END soc_257
  PIN soc_258
    DIRECTION INOUT ;
    USE SIGNAL ;
    PORT
      LAYER L1 ;
        RECT  1536.081 5747.6695 1616.081 5827.6695 ;
    END
  END soc_258
  PIN soc_259
    DIRECTION INOUT ;
    USE SIGNAL ;
    PORT
      LAYER L1 ;
        RECT  1692.881 5747.6695 1772.881 5827.6695 ;
    END
  END soc_259
  PIN soc_26
    DIRECTION INOUT ;
    USE SIGNAL ;
    PORT
      LAYER L1 ;
        RECT  1379.281 6877.7585 1459.281 6957.7585 ;
    END
  END soc_26
  PIN soc_260
    DIRECTION INOUT ;
    USE SIGNAL ;
    PORT
      LAYER L1 ;
        RECT  1849.681 5747.6695 1929.681 5827.6695 ;
    END
  END soc_260
  PIN soc_261
    DIRECTION INOUT ;
    USE SIGNAL ;
    PORT
      LAYER L1 ;
        RECT  2006.481 5747.6695 2086.481 5827.6695 ;
    END
  END soc_261
  PIN soc_262
    DIRECTION INOUT ;
    USE SIGNAL ;
    PORT
      LAYER L1 ;
        RECT  2163.281 5747.6695 2243.281 5827.6695 ;
    END
  END soc_262
  PIN soc_263
    DIRECTION INOUT ;
    USE SIGNAL ;
    PORT
      LAYER L1 ;
        RECT  2320.081 5747.6695 2400.081 5827.6695 ;
    END
  END soc_263
  PIN soc_264
    DIRECTION INOUT ;
    USE SIGNAL ;
    PORT
      LAYER L1 ;
        RECT  2476.881 5747.6695 2556.881 5827.6695 ;
    END
  END soc_264
  PIN soc_265
    DIRECTION INOUT ;
    USE SIGNAL ;
    PORT
      LAYER L1 ;
        RECT  3104.081 6042.216 3184.081 6122.216 ;
    END
  END soc_265
  PIN soc_266
    DIRECTION INOUT ;
    USE SIGNAL ;
    PORT
      LAYER L1 ;
        RECT  3260.881 6042.216 3340.881 6122.216 ;
    END
  END soc_266
  PIN soc_267
    DIRECTION INOUT ;
    USE SIGNAL ;
    PORT
      LAYER L1 ;
        RECT  3574.481 6042.216 3654.481 6122.216 ;
    END
  END soc_267
  PIN soc_268
    DIRECTION INOUT ;
    USE SIGNAL ;
    PORT
      LAYER L1 ;
        RECT  3731.281 6042.216 3811.281 6122.216 ;
    END
  END soc_268
  PIN soc_269
    DIRECTION INOUT ;
    USE SIGNAL ;
    PORT
      LAYER L1 ;
        RECT  124.881 5586.228 204.881 5666.228 ;
    END
  END soc_269
  PIN soc_27
    DIRECTION INOUT ;
    USE SIGNAL ;
    PORT
      LAYER L1 ;
        RECT  1536.081 6877.7585 1616.081 6957.7585 ;
    END
  END soc_27
  PIN soc_270
    DIRECTION INOUT ;
    USE SIGNAL ;
    PORT
      LAYER L1 ;
        RECT  281.681 5586.228 361.681 5666.228 ;
    END
  END soc_270
  PIN soc_271
    DIRECTION INOUT ;
    USE SIGNAL ;
    PORT
      LAYER L1 ;
        RECT  438.481 5586.228 518.481 5666.228 ;
    END
  END soc_271
  PIN soc_272
    DIRECTION INOUT ;
    USE SIGNAL ;
    PORT
      LAYER L1 ;
        RECT  595.281 5586.228 675.281 5666.228 ;
    END
  END soc_272
  PIN soc_273
    DIRECTION INOUT ;
    USE SIGNAL ;
    PORT
      LAYER L1 ;
        RECT  752.081 5586.228 832.081 5666.228 ;
    END
  END soc_273
  PIN soc_274
    DIRECTION INOUT ;
    USE SIGNAL ;
    PORT
      LAYER L1 ;
        RECT  908.881 5586.228 988.881 5666.228 ;
    END
  END soc_274
  PIN soc_275
    DIRECTION INOUT ;
    USE SIGNAL ;
    PORT
      LAYER L1 ;
        RECT  1065.681 5586.228 1145.681 5666.228 ;
    END
  END soc_275
  PIN soc_276
    DIRECTION INOUT ;
    USE SIGNAL ;
    PORT
      LAYER L1 ;
        RECT  1222.481 5586.228 1302.481 5666.228 ;
    END
  END soc_276
  PIN soc_277
    DIRECTION INOUT ;
    USE SIGNAL ;
    PORT
      LAYER L1 ;
        RECT  1379.281 5586.228 1459.281 5666.228 ;
    END
  END soc_277
  PIN soc_278
    DIRECTION INOUT ;
    USE SIGNAL ;
    PORT
      LAYER L1 ;
        RECT  1536.081 5586.228 1616.081 5666.228 ;
    END
  END soc_278
  PIN soc_279
    DIRECTION INOUT ;
    USE SIGNAL ;
    PORT
      LAYER L1 ;
        RECT  1692.881 5586.228 1772.881 5666.228 ;
    END
  END soc_279
  PIN soc_28
    DIRECTION INOUT ;
    USE SIGNAL ;
    PORT
      LAYER L1 ;
        RECT  1692.881 6877.7585 1772.881 6957.7585 ;
    END
  END soc_28
  PIN soc_280
    DIRECTION INOUT ;
    USE SIGNAL ;
    PORT
      LAYER L1 ;
        RECT  1849.681 5586.228 1929.681 5666.228 ;
    END
  END soc_280
  PIN soc_281
    DIRECTION INOUT ;
    USE SIGNAL ;
    PORT
      LAYER L1 ;
        RECT  2006.481 5586.228 2086.481 5666.228 ;
    END
  END soc_281
  PIN soc_282
    DIRECTION INOUT ;
    USE SIGNAL ;
    PORT
      LAYER L1 ;
        RECT  2163.281 5586.228 2243.281 5666.228 ;
    END
  END soc_282
  PIN soc_283
    DIRECTION INOUT ;
    USE SIGNAL ;
    PORT
      LAYER L1 ;
        RECT  2320.081 5586.228 2400.081 5666.228 ;
    END
  END soc_283
  PIN soc_284
    DIRECTION INOUT ;
    USE SIGNAL ;
    PORT
      LAYER L1 ;
        RECT  2476.881 5586.228 2556.881 5666.228 ;
    END
  END soc_284
  PIN soc_285
    DIRECTION INOUT ;
    USE SIGNAL ;
    PORT
      LAYER L1 ;
        RECT  3104.081 5880.775 3184.081 5960.775 ;
    END
  END soc_285
  PIN soc_286
    DIRECTION INOUT ;
    USE SIGNAL ;
    PORT
      LAYER L1 ;
        RECT  3260.881 5880.775 3340.881 5960.775 ;
    END
  END soc_286
  PIN soc_287
    DIRECTION INOUT ;
    USE SIGNAL ;
    PORT
      LAYER L1 ;
        RECT  3574.481 5880.775 3654.481 5960.775 ;
    END
  END soc_287
  PIN soc_288
    DIRECTION INOUT ;
    USE SIGNAL ;
    PORT
      LAYER L1 ;
        RECT  3731.281 5880.775 3811.281 5960.775 ;
    END
  END soc_288
  PIN soc_289
    DIRECTION INOUT ;
    USE SIGNAL ;
    PORT
      LAYER L1 ;
        RECT  124.881 5424.7865 204.881 5504.7865 ;
    END
  END soc_289
  PIN soc_29
    DIRECTION INOUT ;
    USE SIGNAL ;
    PORT
      LAYER L1 ;
        RECT  1849.681 6877.7585 1929.681 6957.7585 ;
    END
  END soc_29
  PIN soc_290
    DIRECTION INOUT ;
    USE SIGNAL ;
    PORT
      LAYER L1 ;
        RECT  281.681 5424.7865 361.681 5504.7865 ;
    END
  END soc_290
  PIN soc_291
    DIRECTION INOUT ;
    USE SIGNAL ;
    PORT
      LAYER L1 ;
        RECT  438.481 5424.7865 518.481 5504.7865 ;
    END
  END soc_291
  PIN soc_292
    DIRECTION INOUT ;
    USE SIGNAL ;
    PORT
      LAYER L1 ;
        RECT  595.281 5424.7865 675.281 5504.7865 ;
    END
  END soc_292
  PIN soc_293
    DIRECTION INOUT ;
    USE SIGNAL ;
    PORT
      LAYER L1 ;
        RECT  752.081 5424.7865 832.081 5504.7865 ;
    END
  END soc_293
  PIN soc_294
    DIRECTION INOUT ;
    USE SIGNAL ;
    PORT
      LAYER L1 ;
        RECT  908.881 5424.7865 988.881 5504.7865 ;
    END
  END soc_294
  PIN soc_295
    DIRECTION INOUT ;
    USE SIGNAL ;
    PORT
      LAYER L1 ;
        RECT  1065.681 5424.7865 1145.681 5504.7865 ;
    END
  END soc_295
  PIN soc_296
    DIRECTION INOUT ;
    USE SIGNAL ;
    PORT
      LAYER L1 ;
        RECT  1222.481 5424.7865 1302.481 5504.7865 ;
    END
  END soc_296
  PIN soc_297
    DIRECTION INOUT ;
    USE SIGNAL ;
    PORT
      LAYER L1 ;
        RECT  1379.281 5424.7865 1459.281 5504.7865 ;
    END
  END soc_297
  PIN soc_298
    DIRECTION INOUT ;
    USE SIGNAL ;
    PORT
      LAYER L1 ;
        RECT  1536.081 5424.7865 1616.081 5504.7865 ;
    END
  END soc_298
  PIN soc_299
    DIRECTION INOUT ;
    USE SIGNAL ;
    PORT
      LAYER L1 ;
        RECT  1692.881 5424.7865 1772.881 5504.7865 ;
    END
  END soc_299
  PIN soc_3
    DIRECTION INOUT ;
    USE SIGNAL ;
    PORT
      LAYER L1 ;
        RECT  281.681 7039.1995 361.681 7119.1995 ;
    END
  END soc_3
  PIN soc_30
    DIRECTION INOUT ;
    USE SIGNAL ;
    PORT
      LAYER L1 ;
        RECT  2006.481 6877.7585 2086.481 6957.7585 ;
    END
  END soc_30
  PIN soc_300
    DIRECTION INOUT ;
    USE SIGNAL ;
    PORT
      LAYER L1 ;
        RECT  1849.681 5424.7865 1929.681 5504.7865 ;
    END
  END soc_300
  PIN soc_301
    DIRECTION INOUT ;
    USE SIGNAL ;
    PORT
      LAYER L1 ;
        RECT  2006.481 5424.7865 2086.481 5504.7865 ;
    END
  END soc_301
  PIN soc_302
    DIRECTION INOUT ;
    USE SIGNAL ;
    PORT
      LAYER L1 ;
        RECT  2163.281 5424.7865 2243.281 5504.7865 ;
    END
  END soc_302
  PIN soc_303
    DIRECTION INOUT ;
    USE SIGNAL ;
    PORT
      LAYER L1 ;
        RECT  2320.081 5424.7865 2400.081 5504.7865 ;
    END
  END soc_303
  PIN soc_304
    DIRECTION INOUT ;
    USE SIGNAL ;
    PORT
      LAYER L1 ;
        RECT  2476.881 5424.7865 2556.881 5504.7865 ;
    END
  END soc_304
  PIN soc_305
    DIRECTION INOUT ;
    USE SIGNAL ;
    PORT
      LAYER L1 ;
        RECT  3104.081 5719.3335 3184.081 5799.3335 ;
    END
  END soc_305
  PIN soc_306
    DIRECTION INOUT ;
    USE SIGNAL ;
    PORT
      LAYER L1 ;
        RECT  3260.881 5719.3335 3340.881 5799.3335 ;
    END
  END soc_306
  PIN soc_307
    DIRECTION INOUT ;
    USE SIGNAL ;
    PORT
      LAYER L1 ;
        RECT  3574.481 5719.3335 3654.481 5799.3335 ;
    END
  END soc_307
  PIN soc_308
    DIRECTION INOUT ;
    USE SIGNAL ;
    PORT
      LAYER L1 ;
        RECT  3731.281 5719.3335 3811.281 5799.3335 ;
    END
  END soc_308
  PIN soc_309
    DIRECTION INOUT ;
    USE SIGNAL ;
    PORT
      LAYER L1 ;
        RECT  124.881 5263.3455 204.881 5343.3455 ;
    END
  END soc_309
  PIN soc_31
    DIRECTION INOUT ;
    USE SIGNAL ;
    PORT
      LAYER L1 ;
        RECT  2163.281 6877.7585 2243.281 6957.7585 ;
    END
  END soc_31
  PIN soc_310
    DIRECTION INOUT ;
    USE SIGNAL ;
    PORT
      LAYER L1 ;
        RECT  281.681 5263.3455 361.681 5343.3455 ;
    END
  END soc_310
  PIN soc_311
    DIRECTION INOUT ;
    USE SIGNAL ;
    PORT
      LAYER L1 ;
        RECT  438.481 5263.3455 518.481 5343.3455 ;
    END
  END soc_311
  PIN soc_312
    DIRECTION INOUT ;
    USE SIGNAL ;
    PORT
      LAYER L1 ;
        RECT  595.281 5263.3455 675.281 5343.3455 ;
    END
  END soc_312
  PIN soc_313
    DIRECTION INOUT ;
    USE SIGNAL ;
    PORT
      LAYER L1 ;
        RECT  752.081 5263.3455 832.081 5343.3455 ;
    END
  END soc_313
  PIN soc_314
    DIRECTION INOUT ;
    USE SIGNAL ;
    PORT
      LAYER L1 ;
        RECT  908.881 5263.3455 988.881 5343.3455 ;
    END
  END soc_314
  PIN soc_315
    DIRECTION INOUT ;
    USE SIGNAL ;
    PORT
      LAYER L1 ;
        RECT  1065.681 5263.3455 1145.681 5343.3455 ;
    END
  END soc_315
  PIN soc_316
    DIRECTION INOUT ;
    USE SIGNAL ;
    PORT
      LAYER L1 ;
        RECT  1222.481 5263.3455 1302.481 5343.3455 ;
    END
  END soc_316
  PIN soc_317
    DIRECTION INOUT ;
    USE SIGNAL ;
    PORT
      LAYER L1 ;
        RECT  1379.281 5263.3455 1459.281 5343.3455 ;
    END
  END soc_317
  PIN soc_318
    DIRECTION INOUT ;
    USE SIGNAL ;
    PORT
      LAYER L1 ;
        RECT  1536.081 5263.3455 1616.081 5343.3455 ;
    END
  END soc_318
  PIN soc_319
    DIRECTION INOUT ;
    USE SIGNAL ;
    PORT
      LAYER L1 ;
        RECT  1692.881 5263.3455 1772.881 5343.3455 ;
    END
  END soc_319
  PIN soc_32
    DIRECTION INOUT ;
    USE SIGNAL ;
    PORT
      LAYER L1 ;
        RECT  2320.081 6877.7585 2400.081 6957.7585 ;
    END
  END soc_32
  PIN soc_320
    DIRECTION INOUT ;
    USE SIGNAL ;
    PORT
      LAYER L1 ;
        RECT  1849.681 5263.3455 1929.681 5343.3455 ;
    END
  END soc_320
  PIN soc_321
    DIRECTION INOUT ;
    USE SIGNAL ;
    PORT
      LAYER L1 ;
        RECT  2006.481 5263.3455 2086.481 5343.3455 ;
    END
  END soc_321
  PIN soc_322
    DIRECTION INOUT ;
    USE SIGNAL ;
    PORT
      LAYER L1 ;
        RECT  2163.281 5263.3455 2243.281 5343.3455 ;
    END
  END soc_322
  PIN soc_323
    DIRECTION INOUT ;
    USE SIGNAL ;
    PORT
      LAYER L1 ;
        RECT  2320.081 5263.3455 2400.081 5343.3455 ;
    END
  END soc_323
  PIN soc_324
    DIRECTION INOUT ;
    USE SIGNAL ;
    PORT
      LAYER L1 ;
        RECT  2476.881 5263.3455 2556.881 5343.3455 ;
    END
  END soc_324
  PIN soc_325
    DIRECTION INOUT ;
    USE SIGNAL ;
    PORT
      LAYER L1 ;
        RECT  3104.081 5557.8925 3184.081 5637.8925 ;
    END
  END soc_325
  PIN soc_326
    DIRECTION INOUT ;
    USE SIGNAL ;
    PORT
      LAYER L1 ;
        RECT  3260.881 5557.8925 3340.881 5637.8925 ;
    END
  END soc_326
  PIN soc_327
    DIRECTION INOUT ;
    USE SIGNAL ;
    PORT
      LAYER L1 ;
        RECT  3574.481 5557.8925 3654.481 5637.8925 ;
    END
  END soc_327
  PIN soc_328
    DIRECTION INOUT ;
    USE SIGNAL ;
    PORT
      LAYER L1 ;
        RECT  3731.281 5557.8925 3811.281 5637.8925 ;
    END
  END soc_328
  PIN soc_329
    DIRECTION INOUT ;
    USE SIGNAL ;
    PORT
      LAYER L1 ;
        RECT  124.881 5101.904 204.881 5181.904 ;
    END
  END soc_329
  PIN soc_33
    DIRECTION INOUT ;
    USE SIGNAL ;
    PORT
      LAYER L1 ;
        RECT  2476.881 6877.7585 2556.881 6957.7585 ;
    END
  END soc_33
  PIN soc_330
    DIRECTION INOUT ;
    USE SIGNAL ;
    PORT
      LAYER L1 ;
        RECT  281.681 5101.904 361.681 5181.904 ;
    END
  END soc_330
  PIN soc_331
    DIRECTION INOUT ;
    USE SIGNAL ;
    PORT
      LAYER L1 ;
        RECT  438.481 5101.904 518.481 5181.904 ;
    END
  END soc_331
  PIN soc_332
    DIRECTION INOUT ;
    USE SIGNAL ;
    PORT
      LAYER L1 ;
        RECT  595.281 5101.904 675.281 5181.904 ;
    END
  END soc_332
  PIN soc_333
    DIRECTION INOUT ;
    USE SIGNAL ;
    PORT
      LAYER L1 ;
        RECT  752.081 5101.904 832.081 5181.904 ;
    END
  END soc_333
  PIN soc_334
    DIRECTION INOUT ;
    USE SIGNAL ;
    PORT
      LAYER L1 ;
        RECT  908.881 5101.904 988.881 5181.904 ;
    END
  END soc_334
  PIN soc_335
    DIRECTION INOUT ;
    USE SIGNAL ;
    PORT
      LAYER L1 ;
        RECT  1065.681 5101.904 1145.681 5181.904 ;
    END
  END soc_335
  PIN soc_336
    DIRECTION INOUT ;
    USE SIGNAL ;
    PORT
      LAYER L1 ;
        RECT  1222.481 5101.904 1302.481 5181.904 ;
    END
  END soc_336
  PIN soc_337
    DIRECTION INOUT ;
    USE SIGNAL ;
    PORT
      LAYER L1 ;
        RECT  1379.281 5101.904 1459.281 5181.904 ;
    END
  END soc_337
  PIN soc_338
    DIRECTION INOUT ;
    USE SIGNAL ;
    PORT
      LAYER L1 ;
        RECT  1536.081 5101.904 1616.081 5181.904 ;
    END
  END soc_338
  PIN soc_339
    DIRECTION INOUT ;
    USE SIGNAL ;
    PORT
      LAYER L1 ;
        RECT  1692.881 5101.904 1772.881 5181.904 ;
    END
  END soc_339
  PIN soc_34
    DIRECTION INOUT ;
    USE SIGNAL ;
    PORT
      LAYER L1 ;
        RECT  2633.681 7172.305 2713.681 7252.305 ;
    END
  END soc_34
  PIN soc_340
    DIRECTION INOUT ;
    USE SIGNAL ;
    PORT
      LAYER L1 ;
        RECT  1849.681 5101.904 1929.681 5181.904 ;
    END
  END soc_340
  PIN soc_341
    DIRECTION INOUT ;
    USE SIGNAL ;
    PORT
      LAYER L1 ;
        RECT  2006.481 5101.904 2086.481 5181.904 ;
    END
  END soc_341
  PIN soc_342
    DIRECTION INOUT ;
    USE SIGNAL ;
    PORT
      LAYER L1 ;
        RECT  2163.281 5101.904 2243.281 5181.904 ;
    END
  END soc_342
  PIN soc_343
    DIRECTION INOUT ;
    USE SIGNAL ;
    PORT
      LAYER L1 ;
        RECT  2320.081 5101.904 2400.081 5181.904 ;
    END
  END soc_343
  PIN soc_344
    DIRECTION INOUT ;
    USE SIGNAL ;
    PORT
      LAYER L1 ;
        RECT  2476.881 5101.904 2556.881 5181.904 ;
    END
  END soc_344
  PIN soc_345
    DIRECTION INOUT ;
    USE SIGNAL ;
    PORT
      LAYER L1 ;
        RECT  3104.081 5396.451 3184.081 5476.451 ;
    END
  END soc_345
  PIN soc_346
    DIRECTION INOUT ;
    USE SIGNAL ;
    PORT
      LAYER L1 ;
        RECT  3260.881 5396.451 3340.881 5476.451 ;
    END
  END soc_346
  PIN soc_347
    DIRECTION INOUT ;
    USE SIGNAL ;
    PORT
      LAYER L1 ;
        RECT  3574.481 5396.451 3654.481 5476.451 ;
    END
  END soc_347
  PIN soc_348
    DIRECTION INOUT ;
    USE SIGNAL ;
    PORT
      LAYER L1 ;
        RECT  3731.281 5396.451 3811.281 5476.451 ;
    END
  END soc_348
  PIN soc_349
    DIRECTION INOUT ;
    USE SIGNAL ;
    PORT
      LAYER L1 ;
        RECT  124.881 4940.463 204.881 5020.463 ;
    END
  END soc_349
  PIN soc_35
    DIRECTION INOUT ;
    USE SIGNAL ;
    PORT
      LAYER L1 ;
        RECT  2790.481 7172.305 2870.481 7252.305 ;
    END
  END soc_35
  PIN soc_350
    DIRECTION INOUT ;
    USE SIGNAL ;
    PORT
      LAYER L1 ;
        RECT  281.681 4940.463 361.681 5020.463 ;
    END
  END soc_350
  PIN soc_351
    DIRECTION INOUT ;
    USE SIGNAL ;
    PORT
      LAYER L1 ;
        RECT  438.481 4940.463 518.481 5020.463 ;
    END
  END soc_351
  PIN soc_352
    DIRECTION INOUT ;
    USE SIGNAL ;
    PORT
      LAYER L1 ;
        RECT  595.281 4940.463 675.281 5020.463 ;
    END
  END soc_352
  PIN soc_353
    DIRECTION INOUT ;
    USE SIGNAL ;
    PORT
      LAYER L1 ;
        RECT  752.081 4940.463 832.081 5020.463 ;
    END
  END soc_353
  PIN soc_354
    DIRECTION INOUT ;
    USE SIGNAL ;
    PORT
      LAYER L1 ;
        RECT  908.881 4940.463 988.881 5020.463 ;
    END
  END soc_354
  PIN soc_355
    DIRECTION INOUT ;
    USE SIGNAL ;
    PORT
      LAYER L1 ;
        RECT  1065.681 4940.463 1145.681 5020.463 ;
    END
  END soc_355
  PIN soc_356
    DIRECTION INOUT ;
    USE SIGNAL ;
    PORT
      LAYER L1 ;
        RECT  1222.481 4940.463 1302.481 5020.463 ;
    END
  END soc_356
  PIN soc_357
    DIRECTION INOUT ;
    USE SIGNAL ;
    PORT
      LAYER L1 ;
        RECT  1379.281 4940.463 1459.281 5020.463 ;
    END
  END soc_357
  PIN soc_358
    DIRECTION INOUT ;
    USE SIGNAL ;
    PORT
      LAYER L1 ;
        RECT  1536.081 4940.463 1616.081 5020.463 ;
    END
  END soc_358
  PIN soc_359
    DIRECTION INOUT ;
    USE SIGNAL ;
    PORT
      LAYER L1 ;
        RECT  1692.881 4940.463 1772.881 5020.463 ;
    END
  END soc_359
  PIN soc_36
    DIRECTION INOUT ;
    USE SIGNAL ;
    PORT
      LAYER L1 ;
        RECT  2947.281 7172.305 3027.281 7252.305 ;
    END
  END soc_36
  PIN soc_360
    DIRECTION INOUT ;
    USE SIGNAL ;
    PORT
      LAYER L1 ;
        RECT  1849.681 4940.463 1929.681 5020.463 ;
    END
  END soc_360
  PIN soc_361
    DIRECTION INOUT ;
    USE SIGNAL ;
    PORT
      LAYER L1 ;
        RECT  2006.481 4940.463 2086.481 5020.463 ;
    END
  END soc_361
  PIN soc_362
    DIRECTION INOUT ;
    USE SIGNAL ;
    PORT
      LAYER L1 ;
        RECT  2163.281 4940.463 2243.281 5020.463 ;
    END
  END soc_362
  PIN soc_363
    DIRECTION INOUT ;
    USE SIGNAL ;
    PORT
      LAYER L1 ;
        RECT  2320.081 4940.463 2400.081 5020.463 ;
    END
  END soc_363
  PIN soc_364
    DIRECTION INOUT ;
    USE SIGNAL ;
    PORT
      LAYER L1 ;
        RECT  2476.881 4940.463 2556.881 5020.463 ;
    END
  END soc_364
  PIN soc_365
    DIRECTION INOUT ;
    USE SIGNAL ;
    PORT
      LAYER L1 ;
        RECT  3104.081 5235.0095 3184.081 5315.0095 ;
    END
  END soc_365
  PIN soc_366
    DIRECTION INOUT ;
    USE SIGNAL ;
    PORT
      LAYER L1 ;
        RECT  3260.881 5235.0095 3340.881 5315.0095 ;
    END
  END soc_366
  PIN soc_367
    DIRECTION INOUT ;
    USE SIGNAL ;
    PORT
      LAYER L1 ;
        RECT  3574.481 5235.0095 3654.481 5315.0095 ;
    END
  END soc_367
  PIN soc_368
    DIRECTION INOUT ;
    USE SIGNAL ;
    PORT
      LAYER L1 ;
        RECT  3731.281 5235.0095 3811.281 5315.0095 ;
    END
  END soc_368
  PIN soc_369
    DIRECTION INOUT ;
    USE SIGNAL ;
    PORT
      LAYER L1 ;
        RECT  124.881 4779.0215 204.881 4859.0215 ;
    END
  END soc_369
  PIN soc_37
    DIRECTION INOUT ;
    USE SIGNAL ;
    PORT
      LAYER L1 ;
        RECT  3104.081 7172.305 3184.081 7252.305 ;
    END
  END soc_37
  PIN soc_370
    DIRECTION INOUT ;
    USE SIGNAL ;
    PORT
      LAYER L1 ;
        RECT  281.681 4779.0215 361.681 4859.0215 ;
    END
  END soc_370
  PIN soc_371
    DIRECTION INOUT ;
    USE SIGNAL ;
    PORT
      LAYER L1 ;
        RECT  438.481 4779.0215 518.481 4859.0215 ;
    END
  END soc_371
  PIN soc_372
    DIRECTION INOUT ;
    USE SIGNAL ;
    PORT
      LAYER L1 ;
        RECT  595.281 4779.0215 675.281 4859.0215 ;
    END
  END soc_372
  PIN soc_373
    DIRECTION INOUT ;
    USE SIGNAL ;
    PORT
      LAYER L1 ;
        RECT  752.081 4779.0215 832.081 4859.0215 ;
    END
  END soc_373
  PIN soc_374
    DIRECTION INOUT ;
    USE SIGNAL ;
    PORT
      LAYER L1 ;
        RECT  908.881 4779.0215 988.881 4859.0215 ;
    END
  END soc_374
  PIN soc_375
    DIRECTION INOUT ;
    USE SIGNAL ;
    PORT
      LAYER L1 ;
        RECT  1065.681 4779.0215 1145.681 4859.0215 ;
    END
  END soc_375
  PIN soc_376
    DIRECTION INOUT ;
    USE SIGNAL ;
    PORT
      LAYER L1 ;
        RECT  1222.481 4779.0215 1302.481 4859.0215 ;
    END
  END soc_376
  PIN soc_377
    DIRECTION INOUT ;
    USE SIGNAL ;
    PORT
      LAYER L1 ;
        RECT  1379.281 4779.0215 1459.281 4859.0215 ;
    END
  END soc_377
  PIN soc_378
    DIRECTION INOUT ;
    USE SIGNAL ;
    PORT
      LAYER L1 ;
        RECT  1536.081 4779.0215 1616.081 4859.0215 ;
    END
  END soc_378
  PIN soc_379
    DIRECTION INOUT ;
    USE SIGNAL ;
    PORT
      LAYER L1 ;
        RECT  1692.881 4779.0215 1772.881 4859.0215 ;
    END
  END soc_379
  PIN soc_38
    DIRECTION INOUT ;
    USE SIGNAL ;
    PORT
      LAYER L1 ;
        RECT  3260.881 7172.305 3340.881 7252.305 ;
    END
  END soc_38
  PIN soc_380
    DIRECTION INOUT ;
    USE SIGNAL ;
    PORT
      LAYER L1 ;
        RECT  1849.681 4779.0215 1929.681 4859.0215 ;
    END
  END soc_380
  PIN soc_381
    DIRECTION INOUT ;
    USE SIGNAL ;
    PORT
      LAYER L1 ;
        RECT  2006.481 4779.0215 2086.481 4859.0215 ;
    END
  END soc_381
  PIN soc_382
    DIRECTION INOUT ;
    USE SIGNAL ;
    PORT
      LAYER L1 ;
        RECT  2163.281 4779.0215 2243.281 4859.0215 ;
    END
  END soc_382
  PIN soc_383
    DIRECTION INOUT ;
    USE SIGNAL ;
    PORT
      LAYER L1 ;
        RECT  2320.081 4779.0215 2400.081 4859.0215 ;
    END
  END soc_383
  PIN soc_384
    DIRECTION INOUT ;
    USE SIGNAL ;
    PORT
      LAYER L1 ;
        RECT  2476.881 4779.0215 2556.881 4859.0215 ;
    END
  END soc_384
  PIN soc_385
    DIRECTION INOUT ;
    USE SIGNAL ;
    PORT
      LAYER L1 ;
        RECT  3104.081 5073.5685 3184.081 5153.5685 ;
    END
  END soc_385
  PIN soc_386
    DIRECTION INOUT ;
    USE SIGNAL ;
    PORT
      LAYER L1 ;
        RECT  3260.881 5073.5685 3340.881 5153.5685 ;
    END
  END soc_386
  PIN soc_387
    DIRECTION INOUT ;
    USE SIGNAL ;
    PORT
      LAYER L1 ;
        RECT  3574.481 5073.5685 3654.481 5153.5685 ;
    END
  END soc_387
  PIN soc_388
    DIRECTION INOUT ;
    USE SIGNAL ;
    PORT
      LAYER L1 ;
        RECT  3731.281 5073.5685 3811.281 5153.5685 ;
    END
  END soc_388
  PIN soc_389
    DIRECTION INOUT ;
    USE SIGNAL ;
    PORT
      LAYER L1 ;
        RECT  124.881 4617.5805 204.881 4697.5805 ;
    END
  END soc_389
  PIN soc_39
    DIRECTION INOUT ;
    USE SIGNAL ;
    PORT
      LAYER L1 ;
        RECT  3417.681 7172.305 3497.681 7252.305 ;
    END
  END soc_39
  PIN soc_390
    DIRECTION INOUT ;
    USE SIGNAL ;
    PORT
      LAYER L1 ;
        RECT  281.681 4617.5805 361.681 4697.5805 ;
    END
  END soc_390
  PIN soc_391
    DIRECTION INOUT ;
    USE SIGNAL ;
    PORT
      LAYER L1 ;
        RECT  438.481 4617.5805 518.481 4697.5805 ;
    END
  END soc_391
  PIN soc_392
    DIRECTION INOUT ;
    USE SIGNAL ;
    PORT
      LAYER L1 ;
        RECT  595.281 4617.5805 675.281 4697.5805 ;
    END
  END soc_392
  PIN soc_393
    DIRECTION INOUT ;
    USE SIGNAL ;
    PORT
      LAYER L1 ;
        RECT  752.081 4617.5805 832.081 4697.5805 ;
    END
  END soc_393
  PIN soc_394
    DIRECTION INOUT ;
    USE SIGNAL ;
    PORT
      LAYER L1 ;
        RECT  908.881 4617.5805 988.881 4697.5805 ;
    END
  END soc_394
  PIN soc_395
    DIRECTION INOUT ;
    USE SIGNAL ;
    PORT
      LAYER L1 ;
        RECT  1065.681 4617.5805 1145.681 4697.5805 ;
    END
  END soc_395
  PIN soc_396
    DIRECTION INOUT ;
    USE SIGNAL ;
    PORT
      LAYER L1 ;
        RECT  1222.481 4617.5805 1302.481 4697.5805 ;
    END
  END soc_396
  PIN soc_397
    DIRECTION INOUT ;
    USE SIGNAL ;
    PORT
      LAYER L1 ;
        RECT  1379.281 4617.5805 1459.281 4697.5805 ;
    END
  END soc_397
  PIN soc_398
    DIRECTION INOUT ;
    USE SIGNAL ;
    PORT
      LAYER L1 ;
        RECT  1536.081 4617.5805 1616.081 4697.5805 ;
    END
  END soc_398
  PIN soc_399
    DIRECTION INOUT ;
    USE SIGNAL ;
    PORT
      LAYER L1 ;
        RECT  1692.881 4617.5805 1772.881 4697.5805 ;
    END
  END soc_399
  PIN soc_4
    DIRECTION INOUT ;
    USE SIGNAL ;
    PORT
      LAYER L1 ;
        RECT  438.481 7039.1995 518.481 7119.1995 ;
    END
  END soc_4
  PIN soc_40
    DIRECTION INOUT ;
    USE SIGNAL ;
    PORT
      LAYER L1 ;
        RECT  3574.481 7172.305 3654.481 7252.305 ;
    END
  END soc_40
  PIN soc_400
    DIRECTION INOUT ;
    USE SIGNAL ;
    PORT
      LAYER L1 ;
        RECT  1849.681 4617.5805 1929.681 4697.5805 ;
    END
  END soc_400
  PIN soc_401
    DIRECTION INOUT ;
    USE SIGNAL ;
    PORT
      LAYER L1 ;
        RECT  2006.481 4617.5805 2086.481 4697.5805 ;
    END
  END soc_401
  PIN soc_402
    DIRECTION INOUT ;
    USE SIGNAL ;
    PORT
      LAYER L1 ;
        RECT  2163.281 4617.5805 2243.281 4697.5805 ;
    END
  END soc_402
  PIN soc_403
    DIRECTION INOUT ;
    USE SIGNAL ;
    PORT
      LAYER L1 ;
        RECT  2320.081 4617.5805 2400.081 4697.5805 ;
    END
  END soc_403
  PIN soc_404
    DIRECTION INOUT ;
    USE SIGNAL ;
    PORT
      LAYER L1 ;
        RECT  2476.881 4617.5805 2556.881 4697.5805 ;
    END
  END soc_404
  PIN soc_405
    DIRECTION INOUT ;
    USE SIGNAL ;
    PORT
      LAYER L1 ;
        RECT  3104.081 4912.127 3184.081 4992.127 ;
    END
  END soc_405
  PIN soc_406
    DIRECTION INOUT ;
    USE SIGNAL ;
    PORT
      LAYER L1 ;
        RECT  3260.881 4912.127 3340.881 4992.127 ;
    END
  END soc_406
  PIN soc_407
    DIRECTION INOUT ;
    USE SIGNAL ;
    PORT
      LAYER L1 ;
        RECT  3574.481 4912.127 3654.481 4992.127 ;
    END
  END soc_407
  PIN soc_408
    DIRECTION INOUT ;
    USE SIGNAL ;
    PORT
      LAYER L1 ;
        RECT  3731.281 4912.127 3811.281 4992.127 ;
    END
  END soc_408
  PIN soc_409
    DIRECTION INOUT ;
    USE SIGNAL ;
    PORT
      LAYER L1 ;
        RECT  124.881 4456.139 204.881 4536.139 ;
    END
  END soc_409
  PIN soc_41
    DIRECTION INOUT ;
    USE SIGNAL ;
    PORT
      LAYER L1 ;
        RECT  2633.681 97.2245 2713.681 177.2245 ;
    END
  END soc_41
  PIN soc_410
    DIRECTION INOUT ;
    USE SIGNAL ;
    PORT
      LAYER L1 ;
        RECT  281.681 4456.139 361.681 4536.139 ;
    END
  END soc_410
  PIN soc_411
    DIRECTION INOUT ;
    USE SIGNAL ;
    PORT
      LAYER L1 ;
        RECT  438.481 4456.139 518.481 4536.139 ;
    END
  END soc_411
  PIN soc_412
    DIRECTION INOUT ;
    USE SIGNAL ;
    PORT
      LAYER L1 ;
        RECT  595.281 4456.139 675.281 4536.139 ;
    END
  END soc_412
  PIN soc_413
    DIRECTION INOUT ;
    USE SIGNAL ;
    PORT
      LAYER L1 ;
        RECT  752.081 4456.139 832.081 4536.139 ;
    END
  END soc_413
  PIN soc_414
    DIRECTION INOUT ;
    USE SIGNAL ;
    PORT
      LAYER L1 ;
        RECT  908.881 4456.139 988.881 4536.139 ;
    END
  END soc_414
  PIN soc_415
    DIRECTION INOUT ;
    USE SIGNAL ;
    PORT
      LAYER L1 ;
        RECT  1065.681 4456.139 1145.681 4536.139 ;
    END
  END soc_415
  PIN soc_416
    DIRECTION INOUT ;
    USE SIGNAL ;
    PORT
      LAYER L1 ;
        RECT  1222.481 4456.139 1302.481 4536.139 ;
    END
  END soc_416
  PIN soc_417
    DIRECTION INOUT ;
    USE SIGNAL ;
    PORT
      LAYER L1 ;
        RECT  1379.281 4456.139 1459.281 4536.139 ;
    END
  END soc_417
  PIN soc_418
    DIRECTION INOUT ;
    USE SIGNAL ;
    PORT
      LAYER L1 ;
        RECT  1536.081 4456.139 1616.081 4536.139 ;
    END
  END soc_418
  PIN soc_419
    DIRECTION INOUT ;
    USE SIGNAL ;
    PORT
      LAYER L1 ;
        RECT  1692.881 4456.139 1772.881 4536.139 ;
    END
  END soc_419
  PIN soc_42
    DIRECTION INOUT ;
    USE SIGNAL ;
    PORT
      LAYER L1 ;
        RECT  2790.481 97.2245 2870.481 177.2245 ;
    END
  END soc_42
  PIN soc_420
    DIRECTION INOUT ;
    USE SIGNAL ;
    PORT
      LAYER L1 ;
        RECT  1849.681 4456.139 1929.681 4536.139 ;
    END
  END soc_420
  PIN soc_421
    DIRECTION INOUT ;
    USE SIGNAL ;
    PORT
      LAYER L1 ;
        RECT  2006.481 4456.139 2086.481 4536.139 ;
    END
  END soc_421
  PIN soc_422
    DIRECTION INOUT ;
    USE SIGNAL ;
    PORT
      LAYER L1 ;
        RECT  2163.281 4456.139 2243.281 4536.139 ;
    END
  END soc_422
  PIN soc_423
    DIRECTION INOUT ;
    USE SIGNAL ;
    PORT
      LAYER L1 ;
        RECT  2320.081 4456.139 2400.081 4536.139 ;
    END
  END soc_423
  PIN soc_424
    DIRECTION INOUT ;
    USE SIGNAL ;
    PORT
      LAYER L1 ;
        RECT  2476.881 4456.139 2556.881 4536.139 ;
    END
  END soc_424
  PIN soc_425
    DIRECTION INOUT ;
    USE SIGNAL ;
    PORT
      LAYER L1 ;
        RECT  3104.081 4750.686 3184.081 4830.686 ;
    END
  END soc_425
  PIN soc_426
    DIRECTION INOUT ;
    USE SIGNAL ;
    PORT
      LAYER L1 ;
        RECT  3260.881 4750.686 3340.881 4830.686 ;
    END
  END soc_426
  PIN soc_427
    DIRECTION INOUT ;
    USE SIGNAL ;
    PORT
      LAYER L1 ;
        RECT  3574.481 4750.686 3654.481 4830.686 ;
    END
  END soc_427
  PIN soc_428
    DIRECTION INOUT ;
    USE SIGNAL ;
    PORT
      LAYER L1 ;
        RECT  3731.281 4750.686 3811.281 4830.686 ;
    END
  END soc_428
  PIN soc_429
    DIRECTION INOUT ;
    USE SIGNAL ;
    PORT
      LAYER L1 ;
        RECT  124.881 4294.697 204.881 4374.697 ;
    END
  END soc_429
  PIN soc_43
    DIRECTION INOUT ;
    USE SIGNAL ;
    PORT
      LAYER L1 ;
        RECT  2947.281 97.2245 3027.281 177.2245 ;
    END
  END soc_43
  PIN soc_430
    DIRECTION INOUT ;
    USE SIGNAL ;
    PORT
      LAYER L1 ;
        RECT  281.681 4294.698 361.681 4374.698 ;
    END
  END soc_430
  PIN soc_431
    DIRECTION INOUT ;
    USE SIGNAL ;
    PORT
      LAYER L1 ;
        RECT  438.481 4294.698 518.481 4374.698 ;
    END
  END soc_431
  PIN soc_432
    DIRECTION INOUT ;
    USE SIGNAL ;
    PORT
      LAYER L1 ;
        RECT  595.281 4294.698 675.281 4374.698 ;
    END
  END soc_432
  PIN soc_433
    DIRECTION INOUT ;
    USE SIGNAL ;
    PORT
      LAYER L1 ;
        RECT  752.081 4294.698 832.081 4374.698 ;
    END
  END soc_433
  PIN soc_434
    DIRECTION INOUT ;
    USE SIGNAL ;
    PORT
      LAYER L1 ;
        RECT  908.881 4294.698 988.881 4374.698 ;
    END
  END soc_434
  PIN soc_435
    DIRECTION INOUT ;
    USE SIGNAL ;
    PORT
      LAYER L1 ;
        RECT  1065.681 4294.698 1145.681 4374.698 ;
    END
  END soc_435
  PIN soc_436
    DIRECTION INOUT ;
    USE SIGNAL ;
    PORT
      LAYER L1 ;
        RECT  1222.481 4294.698 1302.481 4374.698 ;
    END
  END soc_436
  PIN soc_437
    DIRECTION INOUT ;
    USE SIGNAL ;
    PORT
      LAYER L1 ;
        RECT  1379.281 4294.698 1459.281 4374.698 ;
    END
  END soc_437
  PIN soc_438
    DIRECTION INOUT ;
    USE SIGNAL ;
    PORT
      LAYER L1 ;
        RECT  1536.081 4294.698 1616.081 4374.698 ;
    END
  END soc_438
  PIN soc_439
    DIRECTION INOUT ;
    USE SIGNAL ;
    PORT
      LAYER L1 ;
        RECT  1692.881 4294.698 1772.881 4374.698 ;
    END
  END soc_439
  PIN soc_44
    DIRECTION INOUT ;
    USE SIGNAL ;
    PORT
      LAYER L1 ;
        RECT  3104.081 97.2245 3184.081 177.2245 ;
    END
  END soc_44
  PIN soc_440
    DIRECTION INOUT ;
    USE SIGNAL ;
    PORT
      LAYER L1 ;
        RECT  1849.681 4294.698 1929.681 4374.698 ;
    END
  END soc_440
  PIN soc_441
    DIRECTION INOUT ;
    USE SIGNAL ;
    PORT
      LAYER L1 ;
        RECT  2006.481 4294.698 2086.481 4374.698 ;
    END
  END soc_441
  PIN soc_442
    DIRECTION INOUT ;
    USE SIGNAL ;
    PORT
      LAYER L1 ;
        RECT  2163.281 4294.698 2243.281 4374.698 ;
    END
  END soc_442
  PIN soc_443
    DIRECTION INOUT ;
    USE SIGNAL ;
    PORT
      LAYER L1 ;
        RECT  2320.081 4294.698 2400.081 4374.698 ;
    END
  END soc_443
  PIN soc_444
    DIRECTION INOUT ;
    USE SIGNAL ;
    PORT
      LAYER L1 ;
        RECT  2476.881 4294.698 2556.881 4374.698 ;
    END
  END soc_444
  PIN soc_445
    DIRECTION INOUT ;
    USE SIGNAL ;
    PORT
      LAYER L1 ;
        RECT  3104.081 4589.2445 3184.081 4669.2445 ;
    END
  END soc_445
  PIN soc_446
    DIRECTION INOUT ;
    USE SIGNAL ;
    PORT
      LAYER L1 ;
        RECT  3260.881 4589.2445 3340.881 4669.2445 ;
    END
  END soc_446
  PIN soc_447
    DIRECTION INOUT ;
    USE SIGNAL ;
    PORT
      LAYER L1 ;
        RECT  3574.481 4589.2445 3654.481 4669.2445 ;
    END
  END soc_447
  PIN soc_448
    DIRECTION INOUT ;
    USE SIGNAL ;
    PORT
      LAYER L1 ;
        RECT  3731.281 4589.2445 3811.281 4669.2445 ;
    END
  END soc_448
  PIN soc_449
    DIRECTION INOUT ;
    USE SIGNAL ;
    PORT
      LAYER L1 ;
        RECT  124.881 4133.2565 204.881 4213.2565 ;
    END
  END soc_449
  PIN soc_45
    DIRECTION INOUT ;
    USE SIGNAL ;
    PORT
      LAYER L1 ;
        RECT  3260.881 97.2245 3340.881 177.2245 ;
    END
  END soc_45
  PIN soc_450
    DIRECTION INOUT ;
    USE SIGNAL ;
    PORT
      LAYER L1 ;
        RECT  281.681 4133.2565 361.681 4213.2565 ;
    END
  END soc_450
  PIN soc_451
    DIRECTION INOUT ;
    USE SIGNAL ;
    PORT
      LAYER L1 ;
        RECT  438.481 4133.2565 518.481 4213.2565 ;
    END
  END soc_451
  PIN soc_452
    DIRECTION INOUT ;
    USE SIGNAL ;
    PORT
      LAYER L1 ;
        RECT  595.281 4133.2565 675.281 4213.2565 ;
    END
  END soc_452
  PIN soc_453
    DIRECTION INOUT ;
    USE SIGNAL ;
    PORT
      LAYER L1 ;
        RECT  752.081 4133.2565 832.081 4213.2565 ;
    END
  END soc_453
  PIN soc_454
    DIRECTION INOUT ;
    USE SIGNAL ;
    PORT
      LAYER L1 ;
        RECT  908.881 4133.2565 988.881 4213.2565 ;
    END
  END soc_454
  PIN soc_455
    DIRECTION INOUT ;
    USE SIGNAL ;
    PORT
      LAYER L1 ;
        RECT  1065.681 4133.2565 1145.681 4213.2565 ;
    END
  END soc_455
  PIN soc_456
    DIRECTION INOUT ;
    USE SIGNAL ;
    PORT
      LAYER L1 ;
        RECT  1222.481 4133.2565 1302.481 4213.2565 ;
    END
  END soc_456
  PIN soc_457
    DIRECTION INOUT ;
    USE SIGNAL ;
    PORT
      LAYER L1 ;
        RECT  1379.281 4133.2565 1459.281 4213.2565 ;
    END
  END soc_457
  PIN soc_458
    DIRECTION INOUT ;
    USE SIGNAL ;
    PORT
      LAYER L1 ;
        RECT  1536.081 4133.2565 1616.081 4213.2565 ;
    END
  END soc_458
  PIN soc_459
    DIRECTION INOUT ;
    USE SIGNAL ;
    PORT
      LAYER L1 ;
        RECT  1692.881 4133.2565 1772.881 4213.2565 ;
    END
  END soc_459
  PIN soc_46
    DIRECTION INOUT ;
    USE SIGNAL ;
    PORT
      LAYER L1 ;
        RECT  3417.681 97.2245 3497.681 177.2245 ;
    END
  END soc_46
  PIN soc_460
    DIRECTION INOUT ;
    USE SIGNAL ;
    PORT
      LAYER L1 ;
        RECT  1849.681 4133.2565 1929.681 4213.2565 ;
    END
  END soc_460
  PIN soc_461
    DIRECTION INOUT ;
    USE SIGNAL ;
    PORT
      LAYER L1 ;
        RECT  2006.481 4133.2565 2086.481 4213.2565 ;
    END
  END soc_461
  PIN soc_462
    DIRECTION INOUT ;
    USE SIGNAL ;
    PORT
      LAYER L1 ;
        RECT  2163.281 4133.2565 2243.281 4213.2565 ;
    END
  END soc_462
  PIN soc_463
    DIRECTION INOUT ;
    USE SIGNAL ;
    PORT
      LAYER L1 ;
        RECT  2320.081 4133.2565 2400.081 4213.2565 ;
    END
  END soc_463
  PIN soc_464
    DIRECTION INOUT ;
    USE SIGNAL ;
    PORT
      LAYER L1 ;
        RECT  2476.881 4133.2565 2556.881 4213.2565 ;
    END
  END soc_464
  PIN soc_465
    DIRECTION INOUT ;
    USE SIGNAL ;
    PORT
      LAYER L1 ;
        RECT  3104.081 4427.8035 3184.081 4507.8035 ;
    END
  END soc_465
  PIN soc_466
    DIRECTION INOUT ;
    USE SIGNAL ;
    PORT
      LAYER L1 ;
        RECT  3260.881 4427.8035 3340.881 4507.8035 ;
    END
  END soc_466
  PIN soc_467
    DIRECTION INOUT ;
    USE SIGNAL ;
    PORT
      LAYER L1 ;
        RECT  3574.481 4427.8035 3654.481 4507.8035 ;
    END
  END soc_467
  PIN soc_468
    DIRECTION INOUT ;
    USE SIGNAL ;
    PORT
      LAYER L1 ;
        RECT  3731.281 4427.8035 3811.281 4507.8035 ;
    END
  END soc_468
  PIN soc_469
    DIRECTION INOUT ;
    USE SIGNAL ;
    PORT
      LAYER L1 ;
        RECT  124.881 3971.815 204.881 4051.815 ;
    END
  END soc_469
  PIN soc_47
    DIRECTION INOUT ;
    USE SIGNAL ;
    PORT
      LAYER L1 ;
        RECT  3574.481 97.2245 3654.481 177.2245 ;
    END
  END soc_47
  PIN soc_470
    DIRECTION INOUT ;
    USE SIGNAL ;
    PORT
      LAYER L1 ;
        RECT  281.681 3971.815 361.681 4051.815 ;
    END
  END soc_470
  PIN soc_471
    DIRECTION INOUT ;
    USE SIGNAL ;
    PORT
      LAYER L1 ;
        RECT  438.481 3971.815 518.481 4051.815 ;
    END
  END soc_471
  PIN soc_472
    DIRECTION INOUT ;
    USE SIGNAL ;
    PORT
      LAYER L1 ;
        RECT  595.281 3971.815 675.281 4051.815 ;
    END
  END soc_472
  PIN soc_473
    DIRECTION INOUT ;
    USE SIGNAL ;
    PORT
      LAYER L1 ;
        RECT  752.081 3971.815 832.081 4051.815 ;
    END
  END soc_473
  PIN soc_474
    DIRECTION INOUT ;
    USE SIGNAL ;
    PORT
      LAYER L1 ;
        RECT  908.881 3971.815 988.881 4051.815 ;
    END
  END soc_474
  PIN soc_475
    DIRECTION INOUT ;
    USE SIGNAL ;
    PORT
      LAYER L1 ;
        RECT  1065.681 3971.815 1145.681 4051.815 ;
    END
  END soc_475
  PIN soc_476
    DIRECTION INOUT ;
    USE SIGNAL ;
    PORT
      LAYER L1 ;
        RECT  1222.481 3971.815 1302.481 4051.815 ;
    END
  END soc_476
  PIN soc_477
    DIRECTION INOUT ;
    USE SIGNAL ;
    PORT
      LAYER L1 ;
        RECT  1379.281 3971.815 1459.281 4051.815 ;
    END
  END soc_477
  PIN soc_478
    DIRECTION INOUT ;
    USE SIGNAL ;
    PORT
      LAYER L1 ;
        RECT  1536.081 3971.815 1616.081 4051.815 ;
    END
  END soc_478
  PIN soc_479
    DIRECTION INOUT ;
    USE SIGNAL ;
    PORT
      LAYER L1 ;
        RECT  1692.881 3971.815 1772.881 4051.815 ;
    END
  END soc_479
  PIN soc_48
    DIRECTION INOUT ;
    USE SIGNAL ;
    PORT
      LAYER L1 ;
        RECT  3731.281 258.666 3811.281 338.666 ;
    END
  END soc_48
  PIN soc_480
    DIRECTION INOUT ;
    USE SIGNAL ;
    PORT
      LAYER L1 ;
        RECT  1849.681 3971.815 1929.681 4051.815 ;
    END
  END soc_480
  PIN soc_481
    DIRECTION INOUT ;
    USE SIGNAL ;
    PORT
      LAYER L1 ;
        RECT  2006.481 3971.815 2086.481 4051.815 ;
    END
  END soc_481
  PIN soc_482
    DIRECTION INOUT ;
    USE SIGNAL ;
    PORT
      LAYER L1 ;
        RECT  2163.281 3971.815 2243.281 4051.815 ;
    END
  END soc_482
  PIN soc_483
    DIRECTION INOUT ;
    USE SIGNAL ;
    PORT
      LAYER L1 ;
        RECT  2320.081 3971.815 2400.081 4051.815 ;
    END
  END soc_483
  PIN soc_484
    DIRECTION INOUT ;
    USE SIGNAL ;
    PORT
      LAYER L1 ;
        RECT  2476.881 3971.815 2556.881 4051.815 ;
    END
  END soc_484
  PIN soc_485
    DIRECTION INOUT ;
    USE SIGNAL ;
    PORT
      LAYER L1 ;
        RECT  3104.081 4266.362 3184.081 4346.362 ;
    END
  END soc_485
  PIN soc_486
    DIRECTION INOUT ;
    USE SIGNAL ;
    PORT
      LAYER L1 ;
        RECT  3260.881 4266.362 3340.881 4346.362 ;
    END
  END soc_486
  PIN soc_487
    DIRECTION INOUT ;
    USE SIGNAL ;
    PORT
      LAYER L1 ;
        RECT  3574.481 4266.362 3654.481 4346.362 ;
    END
  END soc_487
  PIN soc_488
    DIRECTION INOUT ;
    USE SIGNAL ;
    PORT
      LAYER L1 ;
        RECT  3731.281 4266.362 3811.281 4346.362 ;
    END
  END soc_488
  PIN soc_489
    DIRECTION INOUT ;
    USE SIGNAL ;
    PORT
      LAYER L1 ;
        RECT  124.881 3810.373 204.881 3890.373 ;
    END
  END soc_489
  PIN soc_49
    DIRECTION INOUT ;
    USE SIGNAL ;
    PORT
      LAYER L1 ;
        RECT  3574.481 258.666 3654.481 338.666 ;
    END
  END soc_49
  PIN soc_490
    DIRECTION INOUT ;
    USE SIGNAL ;
    PORT
      LAYER L1 ;
        RECT  281.681 3810.374 361.681 3890.374 ;
    END
  END soc_490
  PIN soc_491
    DIRECTION INOUT ;
    USE SIGNAL ;
    PORT
      LAYER L1 ;
        RECT  438.481 3810.374 518.481 3890.374 ;
    END
  END soc_491
  PIN soc_492
    DIRECTION INOUT ;
    USE SIGNAL ;
    PORT
      LAYER L1 ;
        RECT  595.281 3810.374 675.281 3890.374 ;
    END
  END soc_492
  PIN soc_493
    DIRECTION INOUT ;
    USE SIGNAL ;
    PORT
      LAYER L1 ;
        RECT  752.081 3810.374 832.081 3890.374 ;
    END
  END soc_493
  PIN soc_494
    DIRECTION INOUT ;
    USE SIGNAL ;
    PORT
      LAYER L1 ;
        RECT  908.881 3810.374 988.881 3890.374 ;
    END
  END soc_494
  PIN soc_495
    DIRECTION INOUT ;
    USE SIGNAL ;
    PORT
      LAYER L1 ;
        RECT  1065.681 3810.374 1145.681 3890.374 ;
    END
  END soc_495
  PIN soc_496
    DIRECTION INOUT ;
    USE SIGNAL ;
    PORT
      LAYER L1 ;
        RECT  1222.481 3810.374 1302.481 3890.374 ;
    END
  END soc_496
  PIN soc_497
    DIRECTION INOUT ;
    USE SIGNAL ;
    PORT
      LAYER L1 ;
        RECT  1379.281 3810.374 1459.281 3890.374 ;
    END
  END soc_497
  PIN soc_498
    DIRECTION INOUT ;
    USE SIGNAL ;
    PORT
      LAYER L1 ;
        RECT  1536.081 3810.374 1616.081 3890.374 ;
    END
  END soc_498
  PIN soc_499
    DIRECTION INOUT ;
    USE SIGNAL ;
    PORT
      LAYER L1 ;
        RECT  1692.881 3810.374 1772.881 3890.374 ;
    END
  END soc_499
  PIN soc_5
    DIRECTION INOUT ;
    USE SIGNAL ;
    PORT
      LAYER L1 ;
        RECT  595.281 7039.1995 675.281 7119.1995 ;
    END
  END soc_5
  PIN soc_50
    DIRECTION INOUT ;
    USE SIGNAL ;
    PORT
      LAYER L1 ;
        RECT  3260.881 258.666 3340.881 338.666 ;
    END
  END soc_50
  PIN soc_500
    DIRECTION INOUT ;
    USE SIGNAL ;
    PORT
      LAYER L1 ;
        RECT  1849.681 3810.374 1929.681 3890.374 ;
    END
  END soc_500
  PIN soc_501
    DIRECTION INOUT ;
    USE SIGNAL ;
    PORT
      LAYER L1 ;
        RECT  2006.481 3810.374 2086.481 3890.374 ;
    END
  END soc_501
  PIN soc_502
    DIRECTION INOUT ;
    USE SIGNAL ;
    PORT
      LAYER L1 ;
        RECT  2163.281 3810.374 2243.281 3890.374 ;
    END
  END soc_502
  PIN soc_503
    DIRECTION INOUT ;
    USE SIGNAL ;
    PORT
      LAYER L1 ;
        RECT  2320.081 3810.374 2400.081 3890.374 ;
    END
  END soc_503
  PIN soc_504
    DIRECTION INOUT ;
    USE SIGNAL ;
    PORT
      LAYER L1 ;
        RECT  2476.881 3810.374 2556.881 3890.374 ;
    END
  END soc_504
  PIN soc_505
    DIRECTION INOUT ;
    USE SIGNAL ;
    PORT
      LAYER L1 ;
        RECT  3104.081 4104.921 3184.081 4184.921 ;
    END
  END soc_505
  PIN soc_506
    DIRECTION INOUT ;
    USE SIGNAL ;
    PORT
      LAYER L1 ;
        RECT  3260.881 4104.921 3340.881 4184.921 ;
    END
  END soc_506
  PIN soc_507
    DIRECTION INOUT ;
    USE SIGNAL ;
    PORT
      LAYER L1 ;
        RECT  3574.481 4104.921 3654.481 4184.921 ;
    END
  END soc_507
  PIN soc_508
    DIRECTION INOUT ;
    USE SIGNAL ;
    PORT
      LAYER L1 ;
        RECT  3731.281 4104.921 3811.281 4184.921 ;
    END
  END soc_508
  PIN soc_509
    DIRECTION INOUT ;
    USE SIGNAL ;
    PORT
      LAYER L1 ;
        RECT  124.881 3648.9325 204.881 3728.9325 ;
    END
  END soc_509
  PIN soc_51
    DIRECTION INOUT ;
    USE SIGNAL ;
    PORT
      LAYER L1 ;
        RECT  3104.081 258.666 3184.081 338.666 ;
    END
  END soc_51
  PIN soc_510
    DIRECTION INOUT ;
    USE SIGNAL ;
    PORT
      LAYER L1 ;
        RECT  281.681 3648.9325 361.681 3728.9325 ;
    END
  END soc_510
  PIN soc_511
    DIRECTION INOUT ;
    USE SIGNAL ;
    PORT
      LAYER L1 ;
        RECT  438.481 3648.9325 518.481 3728.9325 ;
    END
  END soc_511
  PIN soc_512
    DIRECTION INOUT ;
    USE SIGNAL ;
    PORT
      LAYER L1 ;
        RECT  595.281 3648.9325 675.281 3728.9325 ;
    END
  END soc_512
  PIN soc_513
    DIRECTION INOUT ;
    USE SIGNAL ;
    PORT
      LAYER L1 ;
        RECT  752.081 3648.9325 832.081 3728.9325 ;
    END
  END soc_513
  PIN soc_514
    DIRECTION INOUT ;
    USE SIGNAL ;
    PORT
      LAYER L1 ;
        RECT  908.881 3648.9325 988.881 3728.9325 ;
    END
  END soc_514
  PIN soc_515
    DIRECTION INOUT ;
    USE SIGNAL ;
    PORT
      LAYER L1 ;
        RECT  1065.681 3648.9325 1145.681 3728.9325 ;
    END
  END soc_515
  PIN soc_516
    DIRECTION INOUT ;
    USE SIGNAL ;
    PORT
      LAYER L1 ;
        RECT  1222.481 3648.9325 1302.481 3728.9325 ;
    END
  END soc_516
  PIN soc_517
    DIRECTION INOUT ;
    USE SIGNAL ;
    PORT
      LAYER L1 ;
        RECT  1379.281 3648.9325 1459.281 3728.9325 ;
    END
  END soc_517
  PIN soc_518
    DIRECTION INOUT ;
    USE SIGNAL ;
    PORT
      LAYER L1 ;
        RECT  1536.081 3648.9325 1616.081 3728.9325 ;
    END
  END soc_518
  PIN soc_519
    DIRECTION INOUT ;
    USE SIGNAL ;
    PORT
      LAYER L1 ;
        RECT  1692.881 3648.9325 1772.881 3728.9325 ;
    END
  END soc_519
  PIN soc_52
    DIRECTION INOUT ;
    USE SIGNAL ;
    PORT
      LAYER L1 ;
        RECT  3731.281 420.107 3811.281 500.107 ;
    END
  END soc_52
  PIN soc_520
    DIRECTION INOUT ;
    USE SIGNAL ;
    PORT
      LAYER L1 ;
        RECT  1849.681 3648.9325 1929.681 3728.9325 ;
    END
  END soc_520
  PIN soc_521
    DIRECTION INOUT ;
    USE SIGNAL ;
    PORT
      LAYER L1 ;
        RECT  2006.481 3648.9325 2086.481 3728.9325 ;
    END
  END soc_521
  PIN soc_522
    DIRECTION INOUT ;
    USE SIGNAL ;
    PORT
      LAYER L1 ;
        RECT  2163.281 3648.9325 2243.281 3728.9325 ;
    END
  END soc_522
  PIN soc_523
    DIRECTION INOUT ;
    USE SIGNAL ;
    PORT
      LAYER L1 ;
        RECT  2320.081 3648.9325 2400.081 3728.9325 ;
    END
  END soc_523
  PIN soc_524
    DIRECTION INOUT ;
    USE SIGNAL ;
    PORT
      LAYER L1 ;
        RECT  2476.881 3648.9325 2556.881 3728.9325 ;
    END
  END soc_524
  PIN soc_525
    DIRECTION INOUT ;
    USE SIGNAL ;
    PORT
      LAYER L1 ;
        RECT  3104.081 3943.4795 3184.081 4023.4795 ;
    END
  END soc_525
  PIN soc_526
    DIRECTION INOUT ;
    USE SIGNAL ;
    PORT
      LAYER L1 ;
        RECT  3260.881 3943.4795 3340.881 4023.4795 ;
    END
  END soc_526
  PIN soc_527
    DIRECTION INOUT ;
    USE SIGNAL ;
    PORT
      LAYER L1 ;
        RECT  3574.481 3943.4795 3654.481 4023.4795 ;
    END
  END soc_527
  PIN soc_528
    DIRECTION INOUT ;
    USE SIGNAL ;
    PORT
      LAYER L1 ;
        RECT  3731.281 3943.4795 3811.281 4023.4795 ;
    END
  END soc_528
  PIN soc_529
    DIRECTION INOUT ;
    USE SIGNAL ;
    PORT
      LAYER L1 ;
        RECT  124.881 3487.4915 204.881 3567.4915 ;
    END
  END soc_529
  PIN soc_53
    DIRECTION INOUT ;
    USE SIGNAL ;
    PORT
      LAYER L1 ;
        RECT  3574.481 420.107 3654.481 500.107 ;
    END
  END soc_53
  PIN soc_530
    DIRECTION INOUT ;
    USE SIGNAL ;
    PORT
      LAYER L1 ;
        RECT  281.681 3487.4915 361.681 3567.4915 ;
    END
  END soc_530
  PIN soc_531
    DIRECTION INOUT ;
    USE SIGNAL ;
    PORT
      LAYER L1 ;
        RECT  438.481 3487.4915 518.481 3567.4915 ;
    END
  END soc_531
  PIN soc_532
    DIRECTION INOUT ;
    USE SIGNAL ;
    PORT
      LAYER L1 ;
        RECT  595.281 3487.4915 675.281 3567.4915 ;
    END
  END soc_532
  PIN soc_533
    DIRECTION INOUT ;
    USE SIGNAL ;
    PORT
      LAYER L1 ;
        RECT  752.081 3487.4915 832.081 3567.4915 ;
    END
  END soc_533
  PIN soc_534
    DIRECTION INOUT ;
    USE SIGNAL ;
    PORT
      LAYER L1 ;
        RECT  908.881 3487.4915 988.881 3567.4915 ;
    END
  END soc_534
  PIN soc_535
    DIRECTION INOUT ;
    USE SIGNAL ;
    PORT
      LAYER L1 ;
        RECT  1065.681 3487.4915 1145.681 3567.4915 ;
    END
  END soc_535
  PIN soc_536
    DIRECTION INOUT ;
    USE SIGNAL ;
    PORT
      LAYER L1 ;
        RECT  1222.481 3487.4915 1302.481 3567.4915 ;
    END
  END soc_536
  PIN soc_537
    DIRECTION INOUT ;
    USE SIGNAL ;
    PORT
      LAYER L1 ;
        RECT  1379.281 3487.4915 1459.281 3567.4915 ;
    END
  END soc_537
  PIN soc_538
    DIRECTION INOUT ;
    USE SIGNAL ;
    PORT
      LAYER L1 ;
        RECT  1536.081 3487.4915 1616.081 3567.4915 ;
    END
  END soc_538
  PIN soc_539
    DIRECTION INOUT ;
    USE SIGNAL ;
    PORT
      LAYER L1 ;
        RECT  1692.881 3487.4915 1772.881 3567.4915 ;
    END
  END soc_539
  PIN soc_54
    DIRECTION INOUT ;
    USE SIGNAL ;
    PORT
      LAYER L1 ;
        RECT  3260.881 420.107 3340.881 500.107 ;
    END
  END soc_54
  PIN soc_540
    DIRECTION INOUT ;
    USE SIGNAL ;
    PORT
      LAYER L1 ;
        RECT  1849.681 3487.4915 1929.681 3567.4915 ;
    END
  END soc_540
  PIN soc_541
    DIRECTION INOUT ;
    USE SIGNAL ;
    PORT
      LAYER L1 ;
        RECT  2006.481 3487.4915 2086.481 3567.4915 ;
    END
  END soc_541
  PIN soc_542
    DIRECTION INOUT ;
    USE SIGNAL ;
    PORT
      LAYER L1 ;
        RECT  2163.281 3487.4915 2243.281 3567.4915 ;
    END
  END soc_542
  PIN soc_543
    DIRECTION INOUT ;
    USE SIGNAL ;
    PORT
      LAYER L1 ;
        RECT  2320.081 3487.4915 2400.081 3567.4915 ;
    END
  END soc_543
  PIN soc_544
    DIRECTION INOUT ;
    USE SIGNAL ;
    PORT
      LAYER L1 ;
        RECT  2476.881 3487.4915 2556.881 3567.4915 ;
    END
  END soc_544
  PIN soc_545
    DIRECTION INOUT ;
    USE SIGNAL ;
    PORT
      LAYER L1 ;
        RECT  3574.481 3782.038 3654.481 3862.038 ;
    END
  END soc_545
  PIN soc_546
    DIRECTION INOUT ;
    USE SIGNAL ;
    PORT
      LAYER L1 ;
        RECT  124.881 3326.049 204.881 3406.049 ;
    END
  END soc_546
  PIN soc_547
    DIRECTION INOUT ;
    USE SIGNAL ;
    PORT
      LAYER L1 ;
        RECT  281.681 3326.05 361.681 3406.05 ;
    END
  END soc_547
  PIN soc_548
    DIRECTION INOUT ;
    USE SIGNAL ;
    PORT
      LAYER L1 ;
        RECT  438.481 3326.05 518.481 3406.05 ;
    END
  END soc_548
  PIN soc_549
    DIRECTION INOUT ;
    USE SIGNAL ;
    PORT
      LAYER L1 ;
        RECT  595.281 3326.05 675.281 3406.05 ;
    END
  END soc_549
  PIN soc_55
    DIRECTION INOUT ;
    USE SIGNAL ;
    PORT
      LAYER L1 ;
        RECT  3104.081 420.107 3184.081 500.107 ;
    END
  END soc_55
  PIN soc_550
    DIRECTION INOUT ;
    USE SIGNAL ;
    PORT
      LAYER L1 ;
        RECT  752.081 3326.05 832.081 3406.05 ;
    END
  END soc_550
  PIN soc_551
    DIRECTION INOUT ;
    USE SIGNAL ;
    PORT
      LAYER L1 ;
        RECT  908.881 3326.05 988.881 3406.05 ;
    END
  END soc_551
  PIN soc_552
    DIRECTION INOUT ;
    USE SIGNAL ;
    PORT
      LAYER L1 ;
        RECT  1065.681 3326.05 1145.681 3406.05 ;
    END
  END soc_552
  PIN soc_553
    DIRECTION INOUT ;
    USE SIGNAL ;
    PORT
      LAYER L1 ;
        RECT  1222.481 3326.05 1302.481 3406.05 ;
    END
  END soc_553
  PIN soc_554
    DIRECTION INOUT ;
    USE SIGNAL ;
    PORT
      LAYER L1 ;
        RECT  1379.281 3326.05 1459.281 3406.05 ;
    END
  END soc_554
  PIN soc_555
    DIRECTION INOUT ;
    USE SIGNAL ;
    PORT
      LAYER L1 ;
        RECT  1536.081 3326.05 1616.081 3406.05 ;
    END
  END soc_555
  PIN soc_556
    DIRECTION INOUT ;
    USE SIGNAL ;
    PORT
      LAYER L1 ;
        RECT  1692.881 3326.05 1772.881 3406.05 ;
    END
  END soc_556
  PIN soc_557
    DIRECTION INOUT ;
    USE SIGNAL ;
    PORT
      LAYER L1 ;
        RECT  1849.681 3326.05 1929.681 3406.05 ;
    END
  END soc_557
  PIN soc_558
    DIRECTION INOUT ;
    USE SIGNAL ;
    PORT
      LAYER L1 ;
        RECT  2006.481 3326.05 2086.481 3406.05 ;
    END
  END soc_558
  PIN soc_559
    DIRECTION INOUT ;
    USE SIGNAL ;
    PORT
      LAYER L1 ;
        RECT  2163.281 3326.05 2243.281 3406.05 ;
    END
  END soc_559
  PIN soc_56
    DIRECTION INOUT ;
    USE SIGNAL ;
    PORT
      LAYER L1 ;
        RECT  3731.281 581.5485 3811.281 661.5485 ;
    END
  END soc_56
  PIN soc_560
    DIRECTION INOUT ;
    USE SIGNAL ;
    PORT
      LAYER L1 ;
        RECT  2320.081 3326.05 2400.081 3406.05 ;
    END
  END soc_560
  PIN soc_561
    DIRECTION INOUT ;
    USE SIGNAL ;
    PORT
      LAYER L1 ;
        RECT  2476.881 3326.05 2556.881 3406.05 ;
    END
  END soc_561
  PIN soc_562
    DIRECTION INOUT ;
    USE SIGNAL ;
    PORT
      LAYER L1 ;
        RECT  2633.681 3620.597 2713.681 3700.597 ;
    END
  END soc_562
  PIN soc_563
    DIRECTION INOUT ;
    USE SIGNAL ;
    PORT
      LAYER L1 ;
        RECT  3574.481 3620.597 3654.481 3700.597 ;
    END
  END soc_563
  PIN soc_564
    DIRECTION INOUT ;
    USE SIGNAL ;
    PORT
      LAYER L1 ;
        RECT  124.881 3166.2465 204.881 3246.2465 ;
    END
  END soc_564
  PIN soc_565
    DIRECTION INOUT ;
    USE SIGNAL ;
    PORT
      LAYER L1 ;
        RECT  281.681 3166.2465 361.681 3246.2465 ;
    END
  END soc_565
  PIN soc_566
    DIRECTION INOUT ;
    USE SIGNAL ;
    PORT
      LAYER L1 ;
        RECT  438.481 3166.2465 518.481 3246.2465 ;
    END
  END soc_566
  PIN soc_567
    DIRECTION INOUT ;
    USE SIGNAL ;
    PORT
      LAYER L1 ;
        RECT  595.281 3166.2465 675.281 3246.2465 ;
    END
  END soc_567
  PIN soc_568
    DIRECTION INOUT ;
    USE SIGNAL ;
    PORT
      LAYER L1 ;
        RECT  752.081 3166.2465 832.081 3246.2465 ;
    END
  END soc_568
  PIN soc_569
    DIRECTION INOUT ;
    USE SIGNAL ;
    PORT
      LAYER L1 ;
        RECT  908.881 3166.2465 988.881 3246.2465 ;
    END
  END soc_569
  PIN soc_57
    DIRECTION INOUT ;
    USE SIGNAL ;
    PORT
      LAYER L1 ;
        RECT  3574.481 581.5485 3654.481 661.5485 ;
    END
  END soc_57
  PIN soc_570
    DIRECTION INOUT ;
    USE SIGNAL ;
    PORT
      LAYER L1 ;
        RECT  1065.681 3166.2465 1145.681 3246.2465 ;
    END
  END soc_570
  PIN soc_571
    DIRECTION INOUT ;
    USE SIGNAL ;
    PORT
      LAYER L1 ;
        RECT  1222.481 3166.2465 1302.481 3246.2465 ;
    END
  END soc_571
  PIN soc_572
    DIRECTION INOUT ;
    USE SIGNAL ;
    PORT
      LAYER L1 ;
        RECT  1379.281 3166.2465 1459.281 3246.2465 ;
    END
  END soc_572
  PIN soc_573
    DIRECTION INOUT ;
    USE SIGNAL ;
    PORT
      LAYER L1 ;
        RECT  1536.081 3166.2465 1616.081 3246.2465 ;
    END
  END soc_573
  PIN soc_574
    DIRECTION INOUT ;
    USE SIGNAL ;
    PORT
      LAYER L1 ;
        RECT  1692.881 3166.2465 1772.881 3246.2465 ;
    END
  END soc_574
  PIN soc_575
    DIRECTION INOUT ;
    USE SIGNAL ;
    PORT
      LAYER L1 ;
        RECT  1849.681 3166.2465 1929.681 3246.2465 ;
    END
  END soc_575
  PIN soc_576
    DIRECTION INOUT ;
    USE SIGNAL ;
    PORT
      LAYER L1 ;
        RECT  2006.481 3166.2465 2086.481 3246.2465 ;
    END
  END soc_576
  PIN soc_577
    DIRECTION INOUT ;
    USE SIGNAL ;
    PORT
      LAYER L1 ;
        RECT  2163.281 3166.2465 2243.281 3246.2465 ;
    END
  END soc_577
  PIN soc_578
    DIRECTION INOUT ;
    USE SIGNAL ;
    PORT
      LAYER L1 ;
        RECT  2320.081 3166.2465 2400.081 3246.2465 ;
    END
  END soc_578
  PIN soc_579
    DIRECTION INOUT ;
    USE SIGNAL ;
    PORT
      LAYER L1 ;
        RECT  2476.881 3166.2465 2556.881 3246.2465 ;
    END
  END soc_579
  PIN soc_58
    DIRECTION INOUT ;
    USE SIGNAL ;
    PORT
      LAYER L1 ;
        RECT  3260.881 581.5485 3340.881 661.5485 ;
    END
  END soc_58
  PIN soc_580
    DIRECTION INOUT ;
    USE SIGNAL ;
    PORT
      LAYER L1 ;
        RECT  124.881 3004.805 204.881 3084.805 ;
    END
  END soc_580
  PIN soc_581
    DIRECTION INOUT ;
    USE SIGNAL ;
    PORT
      LAYER L1 ;
        RECT  281.681 3004.805 361.681 3084.805 ;
    END
  END soc_581
  PIN soc_582
    DIRECTION INOUT ;
    USE SIGNAL ;
    PORT
      LAYER L1 ;
        RECT  438.481 3004.805 518.481 3084.805 ;
    END
  END soc_582
  PIN soc_583
    DIRECTION INOUT ;
    USE SIGNAL ;
    PORT
      LAYER L1 ;
        RECT  595.281 3004.805 675.281 3084.805 ;
    END
  END soc_583
  PIN soc_584
    DIRECTION INOUT ;
    USE SIGNAL ;
    PORT
      LAYER L1 ;
        RECT  752.081 3004.805 832.081 3084.805 ;
    END
  END soc_584
  PIN soc_585
    DIRECTION INOUT ;
    USE SIGNAL ;
    PORT
      LAYER L1 ;
        RECT  908.881 3004.805 988.881 3084.805 ;
    END
  END soc_585
  PIN soc_586
    DIRECTION INOUT ;
    USE SIGNAL ;
    PORT
      LAYER L1 ;
        RECT  1065.681 3004.805 1145.681 3084.805 ;
    END
  END soc_586
  PIN soc_587
    DIRECTION INOUT ;
    USE SIGNAL ;
    PORT
      LAYER L1 ;
        RECT  1222.481 3004.805 1302.481 3084.805 ;
    END
  END soc_587
  PIN soc_588
    DIRECTION INOUT ;
    USE SIGNAL ;
    PORT
      LAYER L1 ;
        RECT  1379.281 3004.805 1459.281 3084.805 ;
    END
  END soc_588
  PIN soc_589
    DIRECTION INOUT ;
    USE SIGNAL ;
    PORT
      LAYER L1 ;
        RECT  1536.081 3004.805 1616.081 3084.805 ;
    END
  END soc_589
  PIN soc_59
    DIRECTION INOUT ;
    USE SIGNAL ;
    PORT
      LAYER L1 ;
        RECT  3104.081 581.5485 3184.081 661.5485 ;
    END
  END soc_59
  PIN soc_590
    DIRECTION INOUT ;
    USE SIGNAL ;
    PORT
      LAYER L1 ;
        RECT  1692.881 3004.805 1772.881 3084.805 ;
    END
  END soc_590
  PIN soc_591
    DIRECTION INOUT ;
    USE SIGNAL ;
    PORT
      LAYER L1 ;
        RECT  1849.681 3004.805 1929.681 3084.805 ;
    END
  END soc_591
  PIN soc_592
    DIRECTION INOUT ;
    USE SIGNAL ;
    PORT
      LAYER L1 ;
        RECT  2006.481 3004.805 2086.481 3084.805 ;
    END
  END soc_592
  PIN soc_593
    DIRECTION INOUT ;
    USE SIGNAL ;
    PORT
      LAYER L1 ;
        RECT  2163.281 3004.805 2243.281 3084.805 ;
    END
  END soc_593
  PIN soc_594
    DIRECTION INOUT ;
    USE SIGNAL ;
    PORT
      LAYER L1 ;
        RECT  2320.081 3004.805 2400.081 3084.805 ;
    END
  END soc_594
  PIN soc_595
    DIRECTION INOUT ;
    USE SIGNAL ;
    PORT
      LAYER L1 ;
        RECT  2476.881 3004.805 2556.881 3084.805 ;
    END
  END soc_595
  PIN soc_596
    DIRECTION INOUT ;
    USE SIGNAL ;
    PORT
      LAYER L1 ;
        RECT  124.881 2843.364 204.881 2923.364 ;
    END
  END soc_596
  PIN soc_597
    DIRECTION INOUT ;
    USE SIGNAL ;
    PORT
      LAYER L1 ;
        RECT  281.681 2843.364 361.681 2923.364 ;
    END
  END soc_597
  PIN soc_598
    DIRECTION INOUT ;
    USE SIGNAL ;
    PORT
      LAYER L1 ;
        RECT  438.481 2843.364 518.481 2923.364 ;
    END
  END soc_598
  PIN soc_599
    DIRECTION INOUT ;
    USE SIGNAL ;
    PORT
      LAYER L1 ;
        RECT  595.281 2843.364 675.281 2923.364 ;
    END
  END soc_599
  PIN soc_6
    DIRECTION INOUT ;
    USE SIGNAL ;
    PORT
      LAYER L1 ;
        RECT  752.081 7039.1995 832.081 7119.1995 ;
    END
  END soc_6
  PIN soc_60
    DIRECTION INOUT ;
    USE SIGNAL ;
    PORT
      LAYER L1 ;
        RECT  3731.281 742.9895 3811.281 822.9895 ;
    END
  END soc_60
  PIN soc_600
    DIRECTION INOUT ;
    USE SIGNAL ;
    PORT
      LAYER L1 ;
        RECT  752.081 2843.364 832.081 2923.364 ;
    END
  END soc_600
  PIN soc_601
    DIRECTION INOUT ;
    USE SIGNAL ;
    PORT
      LAYER L1 ;
        RECT  908.881 2843.364 988.881 2923.364 ;
    END
  END soc_601
  PIN soc_602
    DIRECTION INOUT ;
    USE SIGNAL ;
    PORT
      LAYER L1 ;
        RECT  1065.681 2843.364 1145.681 2923.364 ;
    END
  END soc_602
  PIN soc_603
    DIRECTION INOUT ;
    USE SIGNAL ;
    PORT
      LAYER L1 ;
        RECT  1222.481 2843.364 1302.481 2923.364 ;
    END
  END soc_603
  PIN soc_604
    DIRECTION INOUT ;
    USE SIGNAL ;
    PORT
      LAYER L1 ;
        RECT  1379.281 2843.364 1459.281 2923.364 ;
    END
  END soc_604
  PIN soc_605
    DIRECTION INOUT ;
    USE SIGNAL ;
    PORT
      LAYER L1 ;
        RECT  1536.081 2843.364 1616.081 2923.364 ;
    END
  END soc_605
  PIN soc_606
    DIRECTION INOUT ;
    USE SIGNAL ;
    PORT
      LAYER L1 ;
        RECT  1692.881 2843.364 1772.881 2923.364 ;
    END
  END soc_606
  PIN soc_607
    DIRECTION INOUT ;
    USE SIGNAL ;
    PORT
      LAYER L1 ;
        RECT  1849.681 2843.364 1929.681 2923.364 ;
    END
  END soc_607
  PIN soc_608
    DIRECTION INOUT ;
    USE SIGNAL ;
    PORT
      LAYER L1 ;
        RECT  2006.481 2843.364 2086.481 2923.364 ;
    END
  END soc_608
  PIN soc_609
    DIRECTION INOUT ;
    USE SIGNAL ;
    PORT
      LAYER L1 ;
        RECT  2163.281 2843.364 2243.281 2923.364 ;
    END
  END soc_609
  PIN soc_61
    DIRECTION INOUT ;
    USE SIGNAL ;
    PORT
      LAYER L1 ;
        RECT  3574.481 742.9895 3654.481 822.9895 ;
    END
  END soc_61
  PIN soc_610
    DIRECTION INOUT ;
    USE SIGNAL ;
    PORT
      LAYER L1 ;
        RECT  2320.081 2843.364 2400.081 2923.364 ;
    END
  END soc_610
  PIN soc_611
    DIRECTION INOUT ;
    USE SIGNAL ;
    PORT
      LAYER L1 ;
        RECT  2476.881 2843.364 2556.881 2923.364 ;
    END
  END soc_611
  PIN soc_612
    DIRECTION INOUT ;
    USE SIGNAL ;
    PORT
      LAYER L1 ;
        RECT  124.881 2681.9225 204.881 2761.9225 ;
    END
  END soc_612
  PIN soc_613
    DIRECTION INOUT ;
    USE SIGNAL ;
    PORT
      LAYER L1 ;
        RECT  281.681 2681.9225 361.681 2761.9225 ;
    END
  END soc_613
  PIN soc_614
    DIRECTION INOUT ;
    USE SIGNAL ;
    PORT
      LAYER L1 ;
        RECT  438.481 2681.9225 518.481 2761.9225 ;
    END
  END soc_614
  PIN soc_615
    DIRECTION INOUT ;
    USE SIGNAL ;
    PORT
      LAYER L1 ;
        RECT  595.281 2681.9225 675.281 2761.9225 ;
    END
  END soc_615
  PIN soc_616
    DIRECTION INOUT ;
    USE SIGNAL ;
    PORT
      LAYER L1 ;
        RECT  752.081 2681.9225 832.081 2761.9225 ;
    END
  END soc_616
  PIN soc_617
    DIRECTION INOUT ;
    USE SIGNAL ;
    PORT
      LAYER L1 ;
        RECT  908.881 2681.9225 988.881 2761.9225 ;
    END
  END soc_617
  PIN soc_618
    DIRECTION INOUT ;
    USE SIGNAL ;
    PORT
      LAYER L1 ;
        RECT  1065.681 2681.9225 1145.681 2761.9225 ;
    END
  END soc_618
  PIN soc_619
    DIRECTION INOUT ;
    USE SIGNAL ;
    PORT
      LAYER L1 ;
        RECT  1222.481 2681.9225 1302.481 2761.9225 ;
    END
  END soc_619
  PIN soc_62
    DIRECTION INOUT ;
    USE SIGNAL ;
    PORT
      LAYER L1 ;
        RECT  3260.881 742.9895 3340.881 822.9895 ;
    END
  END soc_62
  PIN soc_620
    DIRECTION INOUT ;
    USE SIGNAL ;
    PORT
      LAYER L1 ;
        RECT  1379.281 2681.9225 1459.281 2761.9225 ;
    END
  END soc_620
  PIN soc_621
    DIRECTION INOUT ;
    USE SIGNAL ;
    PORT
      LAYER L1 ;
        RECT  1536.081 2681.9225 1616.081 2761.9225 ;
    END
  END soc_621
  PIN soc_622
    DIRECTION INOUT ;
    USE SIGNAL ;
    PORT
      LAYER L1 ;
        RECT  1692.881 2681.9225 1772.881 2761.9225 ;
    END
  END soc_622
  PIN soc_623
    DIRECTION INOUT ;
    USE SIGNAL ;
    PORT
      LAYER L1 ;
        RECT  1849.681 2681.9225 1929.681 2761.9225 ;
    END
  END soc_623
  PIN soc_624
    DIRECTION INOUT ;
    USE SIGNAL ;
    PORT
      LAYER L1 ;
        RECT  2006.481 2681.9225 2086.481 2761.9225 ;
    END
  END soc_624
  PIN soc_625
    DIRECTION INOUT ;
    USE SIGNAL ;
    PORT
      LAYER L1 ;
        RECT  2163.281 2681.9225 2243.281 2761.9225 ;
    END
  END soc_625
  PIN soc_626
    DIRECTION INOUT ;
    USE SIGNAL ;
    PORT
      LAYER L1 ;
        RECT  124.881 2520.4815 204.881 2600.4815 ;
    END
  END soc_626
  PIN soc_627
    DIRECTION INOUT ;
    USE SIGNAL ;
    PORT
      LAYER L1 ;
        RECT  281.681 2520.4815 361.681 2600.4815 ;
    END
  END soc_627
  PIN soc_628
    DIRECTION INOUT ;
    USE SIGNAL ;
    PORT
      LAYER L1 ;
        RECT  438.481 2520.4815 518.481 2600.4815 ;
    END
  END soc_628
  PIN soc_629
    DIRECTION INOUT ;
    USE SIGNAL ;
    PORT
      LAYER L1 ;
        RECT  595.281 2520.4815 675.281 2600.4815 ;
    END
  END soc_629
  PIN soc_63
    DIRECTION INOUT ;
    USE SIGNAL ;
    PORT
      LAYER L1 ;
        RECT  3104.081 742.9895 3184.081 822.9895 ;
    END
  END soc_63
  PIN soc_630
    DIRECTION INOUT ;
    USE SIGNAL ;
    PORT
      LAYER L1 ;
        RECT  752.081 2520.4815 832.081 2600.4815 ;
    END
  END soc_630
  PIN soc_631
    DIRECTION INOUT ;
    USE SIGNAL ;
    PORT
      LAYER L1 ;
        RECT  908.881 2520.4815 988.881 2600.4815 ;
    END
  END soc_631
  PIN soc_632
    DIRECTION INOUT ;
    USE SIGNAL ;
    PORT
      LAYER L1 ;
        RECT  1065.681 2520.4815 1145.681 2600.4815 ;
    END
  END soc_632
  PIN soc_633
    DIRECTION INOUT ;
    USE SIGNAL ;
    PORT
      LAYER L1 ;
        RECT  1222.481 2520.4815 1302.481 2600.4815 ;
    END
  END soc_633
  PIN soc_634
    DIRECTION INOUT ;
    USE SIGNAL ;
    PORT
      LAYER L1 ;
        RECT  1379.281 2520.4815 1459.281 2600.4815 ;
    END
  END soc_634
  PIN soc_635
    DIRECTION INOUT ;
    USE SIGNAL ;
    PORT
      LAYER L1 ;
        RECT  1536.081 2520.4815 1616.081 2600.4815 ;
    END
  END soc_635
  PIN soc_636
    DIRECTION INOUT ;
    USE SIGNAL ;
    PORT
      LAYER L1 ;
        RECT  1692.881 2520.4815 1772.881 2600.4815 ;
    END
  END soc_636
  PIN soc_637
    DIRECTION INOUT ;
    USE SIGNAL ;
    PORT
      LAYER L1 ;
        RECT  1849.681 2520.4815 1929.681 2600.4815 ;
    END
  END soc_637
  PIN soc_638
    DIRECTION INOUT ;
    USE SIGNAL ;
    PORT
      LAYER L1 ;
        RECT  2006.481 2520.4815 2086.481 2600.4815 ;
    END
  END soc_638
  PIN soc_639
    DIRECTION INOUT ;
    USE SIGNAL ;
    PORT
      LAYER L1 ;
        RECT  2163.281 2520.4815 2243.281 2600.4815 ;
    END
  END soc_639
  PIN soc_64
    DIRECTION INOUT ;
    USE SIGNAL ;
    PORT
      LAYER L1 ;
        RECT  3731.281 904.431 3811.281 984.431 ;
    END
  END soc_64
  PIN soc_640
    DIRECTION INOUT ;
    USE SIGNAL ;
    PORT
      LAYER L1 ;
        RECT  124.881 2359.039 204.881 2439.039 ;
    END
  END soc_640
  PIN soc_641
    DIRECTION INOUT ;
    USE SIGNAL ;
    PORT
      LAYER L1 ;
        RECT  281.681 2359.04 361.681 2439.04 ;
    END
  END soc_641
  PIN soc_642
    DIRECTION INOUT ;
    USE SIGNAL ;
    PORT
      LAYER L1 ;
        RECT  438.481 2359.04 518.481 2439.04 ;
    END
  END soc_642
  PIN soc_643
    DIRECTION INOUT ;
    USE SIGNAL ;
    PORT
      LAYER L1 ;
        RECT  595.281 2359.04 675.281 2439.04 ;
    END
  END soc_643
  PIN soc_644
    DIRECTION INOUT ;
    USE SIGNAL ;
    PORT
      LAYER L1 ;
        RECT  752.081 2359.04 832.081 2439.04 ;
    END
  END soc_644
  PIN soc_645
    DIRECTION INOUT ;
    USE SIGNAL ;
    PORT
      LAYER L1 ;
        RECT  908.881 2359.04 988.881 2439.04 ;
    END
  END soc_645
  PIN soc_646
    DIRECTION INOUT ;
    USE SIGNAL ;
    PORT
      LAYER L1 ;
        RECT  1065.681 2359.04 1145.681 2439.04 ;
    END
  END soc_646
  PIN soc_647
    DIRECTION INOUT ;
    USE SIGNAL ;
    PORT
      LAYER L1 ;
        RECT  1222.481 2359.04 1302.481 2439.04 ;
    END
  END soc_647
  PIN soc_648
    DIRECTION INOUT ;
    USE SIGNAL ;
    PORT
      LAYER L1 ;
        RECT  1379.281 2359.04 1459.281 2439.04 ;
    END
  END soc_648
  PIN soc_649
    DIRECTION INOUT ;
    USE SIGNAL ;
    PORT
      LAYER L1 ;
        RECT  1536.081 2359.04 1616.081 2439.04 ;
    END
  END soc_649
  PIN soc_65
    DIRECTION INOUT ;
    USE SIGNAL ;
    PORT
      LAYER L1 ;
        RECT  3574.481 904.431 3654.481 984.431 ;
    END
  END soc_65
  PIN soc_650
    DIRECTION INOUT ;
    USE SIGNAL ;
    PORT
      LAYER L1 ;
        RECT  1692.881 2359.04 1772.881 2439.04 ;
    END
  END soc_650
  PIN soc_651
    DIRECTION INOUT ;
    USE SIGNAL ;
    PORT
      LAYER L1 ;
        RECT  1849.681 2359.04 1929.681 2439.04 ;
    END
  END soc_651
  PIN soc_652
    DIRECTION INOUT ;
    USE SIGNAL ;
    PORT
      LAYER L1 ;
        RECT  2006.481 2359.04 2086.481 2439.04 ;
    END
  END soc_652
  PIN soc_653
    DIRECTION INOUT ;
    USE SIGNAL ;
    PORT
      LAYER L1 ;
        RECT  2163.281 2359.04 2243.281 2439.04 ;
    END
  END soc_653
  PIN soc_654
    DIRECTION INOUT ;
    USE SIGNAL ;
    PORT
      LAYER L1 ;
        RECT  752.081 1067.51 832.081 1147.51 ;
    END
  END soc_654
  PIN soc_655
    DIRECTION INOUT ;
    USE SIGNAL ;
    PORT
      LAYER L1 ;
        RECT  908.881 1067.51 988.881 1147.51 ;
    END
  END soc_655
  PIN soc_656
    DIRECTION INOUT ;
    USE SIGNAL ;
    PORT
      LAYER L1 ;
        RECT  124.881 2197.5985 204.881 2277.5985 ;
    END
  END soc_656
  PIN soc_657
    DIRECTION INOUT ;
    USE SIGNAL ;
    PORT
      LAYER L1 ;
        RECT  281.681 2197.5985 361.681 2277.5985 ;
    END
  END soc_657
  PIN soc_658
    DIRECTION INOUT ;
    USE SIGNAL ;
    PORT
      LAYER L1 ;
        RECT  438.481 2197.5985 518.481 2277.5985 ;
    END
  END soc_658
  PIN soc_659
    DIRECTION INOUT ;
    USE SIGNAL ;
    PORT
      LAYER L1 ;
        RECT  595.281 2197.5985 675.281 2277.5985 ;
    END
  END soc_659
  PIN soc_66
    DIRECTION INOUT ;
    USE SIGNAL ;
    PORT
      LAYER L1 ;
        RECT  3260.881 904.431 3340.881 984.431 ;
    END
  END soc_66
  PIN soc_660
    DIRECTION INOUT ;
    USE SIGNAL ;
    PORT
      LAYER L1 ;
        RECT  752.081 2197.5985 832.081 2277.5985 ;
    END
  END soc_660
  PIN soc_661
    DIRECTION INOUT ;
    USE SIGNAL ;
    PORT
      LAYER L1 ;
        RECT  908.881 2197.5985 988.881 2277.5985 ;
    END
  END soc_661
  PIN soc_662
    DIRECTION INOUT ;
    USE SIGNAL ;
    PORT
      LAYER L1 ;
        RECT  1065.681 2197.5985 1145.681 2277.5985 ;
    END
  END soc_662
  PIN soc_663
    DIRECTION INOUT ;
    USE SIGNAL ;
    PORT
      LAYER L1 ;
        RECT  1222.481 2197.5985 1302.481 2277.5985 ;
    END
  END soc_663
  PIN soc_664
    DIRECTION INOUT ;
    USE SIGNAL ;
    PORT
      LAYER L1 ;
        RECT  1379.281 2197.5985 1459.281 2277.5985 ;
    END
  END soc_664
  PIN soc_665
    DIRECTION INOUT ;
    USE SIGNAL ;
    PORT
      LAYER L1 ;
        RECT  1536.081 2197.5985 1616.081 2277.5985 ;
    END
  END soc_665
  PIN soc_666
    DIRECTION INOUT ;
    USE SIGNAL ;
    PORT
      LAYER L1 ;
        RECT  1692.881 2197.5985 1772.881 2277.5985 ;
    END
  END soc_666
  PIN soc_667
    DIRECTION INOUT ;
    USE SIGNAL ;
    PORT
      LAYER L1 ;
        RECT  1849.681 2197.5985 1929.681 2277.5985 ;
    END
  END soc_667
  PIN soc_668
    DIRECTION INOUT ;
    USE SIGNAL ;
    PORT
      LAYER L1 ;
        RECT  2006.481 2197.5985 2086.481 2277.5985 ;
    END
  END soc_668
  PIN soc_669
    DIRECTION INOUT ;
    USE SIGNAL ;
    PORT
      LAYER L1 ;
        RECT  2163.281 2197.5985 2243.281 2277.5985 ;
    END
  END soc_669
  PIN soc_67
    DIRECTION INOUT ;
    USE SIGNAL ;
    PORT
      LAYER L1 ;
        RECT  3104.081 904.431 3184.081 984.431 ;
    END
  END soc_67
  PIN soc_670
    DIRECTION INOUT ;
    USE SIGNAL ;
    PORT
      LAYER L1 ;
        RECT  752.081 906.0685 832.081 986.0685 ;
    END
  END soc_670
  PIN soc_671
    DIRECTION INOUT ;
    USE SIGNAL ;
    PORT
      LAYER L1 ;
        RECT  908.881 906.0685 988.881 986.0685 ;
    END
  END soc_671
  PIN soc_672
    DIRECTION INOUT ;
    USE SIGNAL ;
    PORT
      LAYER L1 ;
        RECT  124.881 2036.1575 204.881 2116.1575 ;
    END
  END soc_672
  PIN soc_673
    DIRECTION INOUT ;
    USE SIGNAL ;
    PORT
      LAYER L1 ;
        RECT  281.681 2036.1575 361.681 2116.1575 ;
    END
  END soc_673
  PIN soc_674
    DIRECTION INOUT ;
    USE SIGNAL ;
    PORT
      LAYER L1 ;
        RECT  438.481 2036.1575 518.481 2116.1575 ;
    END
  END soc_674
  PIN soc_675
    DIRECTION INOUT ;
    USE SIGNAL ;
    PORT
      LAYER L1 ;
        RECT  595.281 2036.1575 675.281 2116.1575 ;
    END
  END soc_675
  PIN soc_676
    DIRECTION INOUT ;
    USE SIGNAL ;
    PORT
      LAYER L1 ;
        RECT  752.081 2036.1575 832.081 2116.1575 ;
    END
  END soc_676
  PIN soc_677
    DIRECTION INOUT ;
    USE SIGNAL ;
    PORT
      LAYER L1 ;
        RECT  908.881 2036.1575 988.881 2116.1575 ;
    END
  END soc_677
  PIN soc_678
    DIRECTION INOUT ;
    USE SIGNAL ;
    PORT
      LAYER L1 ;
        RECT  1065.681 2036.1575 1145.681 2116.1575 ;
    END
  END soc_678
  PIN soc_679
    DIRECTION INOUT ;
    USE SIGNAL ;
    PORT
      LAYER L1 ;
        RECT  1222.481 2036.1575 1302.481 2116.1575 ;
    END
  END soc_679
  PIN soc_68
    DIRECTION INOUT ;
    USE SIGNAL ;
    PORT
      LAYER L1 ;
        RECT  3731.281 1065.872 3811.281 1145.872 ;
    END
  END soc_68
  PIN soc_680
    DIRECTION INOUT ;
    USE SIGNAL ;
    PORT
      LAYER L1 ;
        RECT  1379.281 2036.1575 1459.281 2116.1575 ;
    END
  END soc_680
  PIN soc_681
    DIRECTION INOUT ;
    USE SIGNAL ;
    PORT
      LAYER L1 ;
        RECT  1536.081 2036.1575 1616.081 2116.1575 ;
    END
  END soc_681
  PIN soc_682
    DIRECTION INOUT ;
    USE SIGNAL ;
    PORT
      LAYER L1 ;
        RECT  1692.881 2036.1575 1772.881 2116.1575 ;
    END
  END soc_682
  PIN soc_683
    DIRECTION INOUT ;
    USE SIGNAL ;
    PORT
      LAYER L1 ;
        RECT  1849.681 2036.1575 1929.681 2116.1575 ;
    END
  END soc_683
  PIN soc_684
    DIRECTION INOUT ;
    USE SIGNAL ;
    PORT
      LAYER L1 ;
        RECT  2006.481 2036.1575 2086.481 2116.1575 ;
    END
  END soc_684
  PIN soc_685
    DIRECTION INOUT ;
    USE SIGNAL ;
    PORT
      LAYER L1 ;
        RECT  752.081 744.627 832.081 824.627 ;
    END
  END soc_685
  PIN soc_686
    DIRECTION INOUT ;
    USE SIGNAL ;
    PORT
      LAYER L1 ;
        RECT  908.881 744.627 988.881 824.627 ;
    END
  END soc_686
  PIN soc_687
    DIRECTION INOUT ;
    USE SIGNAL ;
    PORT
      LAYER L1 ;
        RECT  124.881 1874.715 204.881 1954.715 ;
    END
  END soc_687
  PIN soc_688
    DIRECTION INOUT ;
    USE SIGNAL ;
    PORT
      LAYER L1 ;
        RECT  281.681 1874.716 361.681 1954.716 ;
    END
  END soc_688
  PIN soc_689
    DIRECTION INOUT ;
    USE SIGNAL ;
    PORT
      LAYER L1 ;
        RECT  438.481 1874.716 518.481 1954.716 ;
    END
  END soc_689
  PIN soc_69
    DIRECTION INOUT ;
    USE SIGNAL ;
    PORT
      LAYER L1 ;
        RECT  3574.481 1065.872 3654.481 1145.872 ;
    END
  END soc_69
  PIN soc_690
    DIRECTION INOUT ;
    USE SIGNAL ;
    PORT
      LAYER L1 ;
        RECT  595.281 1874.716 675.281 1954.716 ;
    END
  END soc_690
  PIN soc_691
    DIRECTION INOUT ;
    USE SIGNAL ;
    PORT
      LAYER L1 ;
        RECT  752.081 1874.716 832.081 1954.716 ;
    END
  END soc_691
  PIN soc_692
    DIRECTION INOUT ;
    USE SIGNAL ;
    PORT
      LAYER L1 ;
        RECT  908.881 1874.716 988.881 1954.716 ;
    END
  END soc_692
  PIN soc_693
    DIRECTION INOUT ;
    USE SIGNAL ;
    PORT
      LAYER L1 ;
        RECT  1065.681 1874.716 1145.681 1954.716 ;
    END
  END soc_693
  PIN soc_694
    DIRECTION INOUT ;
    USE SIGNAL ;
    PORT
      LAYER L1 ;
        RECT  1222.481 1874.716 1302.481 1954.716 ;
    END
  END soc_694
  PIN soc_695
    DIRECTION INOUT ;
    USE SIGNAL ;
    PORT
      LAYER L1 ;
        RECT  1379.281 1874.716 1459.281 1954.716 ;
    END
  END soc_695
  PIN soc_696
    DIRECTION INOUT ;
    USE SIGNAL ;
    PORT
      LAYER L1 ;
        RECT  1536.081 1874.716 1616.081 1954.716 ;
    END
  END soc_696
  PIN soc_697
    DIRECTION INOUT ;
    USE SIGNAL ;
    PORT
      LAYER L1 ;
        RECT  1692.881 1874.716 1772.881 1954.716 ;
    END
  END soc_697
  PIN soc_698
    DIRECTION INOUT ;
    USE SIGNAL ;
    PORT
      LAYER L1 ;
        RECT  1849.681 1874.716 1929.681 1954.716 ;
    END
  END soc_698
  PIN soc_699
    DIRECTION INOUT ;
    USE SIGNAL ;
    PORT
      LAYER L1 ;
        RECT  2006.481 1874.716 2086.481 1954.716 ;
    END
  END soc_699
  PIN soc_7
    DIRECTION INOUT ;
    USE SIGNAL ;
    PORT
      LAYER L1 ;
        RECT  908.881 7039.1995 988.881 7119.1995 ;
    END
  END soc_7
  PIN soc_70
    DIRECTION INOUT ;
    USE SIGNAL ;
    PORT
      LAYER L1 ;
        RECT  3260.881 1065.872 3340.881 1145.872 ;
    END
  END soc_70
  PIN soc_700
    DIRECTION INOUT ;
    USE SIGNAL ;
    PORT
      LAYER L1 ;
        RECT  2163.282 1874.716 2243.282 1954.716 ;
    END
  END soc_700
  PIN soc_701
    DIRECTION INOUT ;
    USE SIGNAL ;
    PORT
      LAYER L1 ;
        RECT  752.081 583.186 832.081 663.186 ;
    END
  END soc_701
  PIN soc_702
    DIRECTION INOUT ;
    USE SIGNAL ;
    PORT
      LAYER L1 ;
        RECT  908.881 583.186 988.881 663.186 ;
    END
  END soc_702
  PIN soc_703
    DIRECTION INOUT ;
    USE SIGNAL ;
    PORT
      LAYER L1 ;
        RECT  124.881 1713.275 204.881 1793.275 ;
    END
  END soc_703
  PIN soc_704
    DIRECTION INOUT ;
    USE SIGNAL ;
    PORT
      LAYER L1 ;
        RECT  281.681 1713.275 361.681 1793.275 ;
    END
  END soc_704
  PIN soc_705
    DIRECTION INOUT ;
    USE SIGNAL ;
    PORT
      LAYER L1 ;
        RECT  438.481 1713.275 518.481 1793.275 ;
    END
  END soc_705
  PIN soc_706
    DIRECTION INOUT ;
    USE SIGNAL ;
    PORT
      LAYER L1 ;
        RECT  595.281 1713.275 675.281 1793.275 ;
    END
  END soc_706
  PIN soc_707
    DIRECTION INOUT ;
    USE SIGNAL ;
    PORT
      LAYER L1 ;
        RECT  752.081 1713.275 832.081 1793.275 ;
    END
  END soc_707
  PIN soc_708
    DIRECTION INOUT ;
    USE SIGNAL ;
    PORT
      LAYER L1 ;
        RECT  908.881 1713.275 988.881 1793.275 ;
    END
  END soc_708
  PIN soc_709
    DIRECTION INOUT ;
    USE SIGNAL ;
    PORT
      LAYER L1 ;
        RECT  124.881 1551.8335 204.881 1631.8335 ;
    END
  END soc_709
  PIN soc_71
    DIRECTION INOUT ;
    USE SIGNAL ;
    PORT
      LAYER L1 ;
        RECT  3104.081 1065.872 3184.081 1145.872 ;
    END
  END soc_71
  PIN soc_710
    DIRECTION INOUT ;
    USE SIGNAL ;
    PORT
      LAYER L1 ;
        RECT  281.681 1551.8335 361.681 1631.8335 ;
    END
  END soc_710
  PIN soc_711
    DIRECTION INOUT ;
    USE SIGNAL ;
    PORT
      LAYER L1 ;
        RECT  438.481 1551.8335 518.481 1631.8335 ;
    END
  END soc_711
  PIN soc_712
    DIRECTION INOUT ;
    USE SIGNAL ;
    PORT
      LAYER L1 ;
        RECT  595.281 1551.8335 675.281 1631.8335 ;
    END
  END soc_712
  PIN soc_713
    DIRECTION INOUT ;
    USE SIGNAL ;
    PORT
      LAYER L1 ;
        RECT  752.081 1551.8335 832.081 1631.8335 ;
    END
  END soc_713
  PIN soc_714
    DIRECTION INOUT ;
    USE SIGNAL ;
    PORT
      LAYER L1 ;
        RECT  908.881 1551.8335 988.881 1631.8335 ;
    END
  END soc_714
  PIN soc_715
    DIRECTION INOUT ;
    USE SIGNAL ;
    PORT
      LAYER L1 ;
        RECT  124.881 1390.3915 204.881 1470.3915 ;
    END
  END soc_715
  PIN soc_716
    DIRECTION INOUT ;
    USE SIGNAL ;
    PORT
      LAYER L1 ;
        RECT  281.681 1390.3925 361.681 1470.3925 ;
    END
  END soc_716
  PIN soc_717
    DIRECTION INOUT ;
    USE SIGNAL ;
    PORT
      LAYER L1 ;
        RECT  438.481 1390.3925 518.481 1470.3925 ;
    END
  END soc_717
  PIN soc_718
    DIRECTION INOUT ;
    USE SIGNAL ;
    PORT
      LAYER L1 ;
        RECT  595.281 1390.3925 675.281 1470.3925 ;
    END
  END soc_718
  PIN soc_719
    DIRECTION INOUT ;
    USE SIGNAL ;
    PORT
      LAYER L1 ;
        RECT  752.081 1390.3925 832.081 1470.3925 ;
    END
  END soc_719
  PIN soc_72
    DIRECTION INOUT ;
    USE SIGNAL ;
    PORT
      LAYER L1 ;
        RECT  3731.281 1227.3135 3811.281 1307.3135 ;
    END
  END soc_72
  PIN soc_720
    DIRECTION INOUT ;
    USE SIGNAL ;
    PORT
      LAYER L1 ;
        RECT  908.881 1390.3925 988.881 1470.3925 ;
    END
  END soc_720
  PIN soc_721
    DIRECTION INOUT ;
    USE SIGNAL ;
    PORT
      LAYER L1 ;
        RECT  124.881 1228.951 204.881 1308.951 ;
    END
  END soc_721
  PIN soc_722
    DIRECTION INOUT ;
    USE SIGNAL ;
    PORT
      LAYER L1 ;
        RECT  281.681 1228.951 361.681 1308.951 ;
    END
  END soc_722
  PIN soc_723
    DIRECTION INOUT ;
    USE SIGNAL ;
    PORT
      LAYER L1 ;
        RECT  438.481 1228.951 518.481 1308.951 ;
    END
  END soc_723
  PIN soc_724
    DIRECTION INOUT ;
    USE SIGNAL ;
    PORT
      LAYER L1 ;
        RECT  595.281 1228.951 675.281 1308.951 ;
    END
  END soc_724
  PIN soc_725
    DIRECTION INOUT ;
    USE SIGNAL ;
    PORT
      LAYER L1 ;
        RECT  752.081 1228.951 832.081 1308.951 ;
    END
  END soc_725
  PIN soc_726
    DIRECTION INOUT ;
    USE SIGNAL ;
    PORT
      LAYER L1 ;
        RECT  908.881 1228.951 988.881 1308.951 ;
    END
  END soc_726
  PIN soc_727
    DIRECTION INOUT ;
    USE SIGNAL ;
    PORT
      LAYER L1 ;
        RECT  124.881 1067.51 204.881 1147.51 ;
    END
  END soc_727
  PIN soc_728
    DIRECTION INOUT ;
    USE SIGNAL ;
    PORT
      LAYER L1 ;
        RECT  281.681 1067.51 361.681 1147.51 ;
    END
  END soc_728
  PIN soc_729
    DIRECTION INOUT ;
    USE SIGNAL ;
    PORT
      LAYER L1 ;
        RECT  438.481 1067.51 518.481 1147.51 ;
    END
  END soc_729
  PIN soc_73
    DIRECTION INOUT ;
    USE SIGNAL ;
    PORT
      LAYER L1 ;
        RECT  3574.481 1227.3135 3654.481 1307.3135 ;
    END
  END soc_73
  PIN soc_730
    DIRECTION INOUT ;
    USE SIGNAL ;
    PORT
      LAYER L1 ;
        RECT  595.281 1067.51 675.281 1147.51 ;
    END
  END soc_730
  PIN soc_731
    DIRECTION INOUT ;
    USE SIGNAL ;
    PORT
      LAYER L1 ;
        RECT  2320.081 2520.4825 2400.081 2600.4825 ;
    END
  END soc_731
  PIN soc_732
    DIRECTION INOUT ;
    USE SIGNAL ;
    PORT
      LAYER L1 ;
        RECT  2476.881 2520.4825 2556.881 2600.4825 ;
    END
  END soc_732
  PIN soc_733
    DIRECTION INOUT ;
    USE SIGNAL ;
    PORT
      LAYER L1 ;
        RECT  124.881 906.0675 204.881 986.0675 ;
    END
  END soc_733
  PIN soc_734
    DIRECTION INOUT ;
    USE SIGNAL ;
    PORT
      LAYER L1 ;
        RECT  281.681 906.0685 361.681 986.0685 ;
    END
  END soc_734
  PIN soc_735
    DIRECTION INOUT ;
    USE SIGNAL ;
    PORT
      LAYER L1 ;
        RECT  438.481 906.0685 518.481 986.0685 ;
    END
  END soc_735
  PIN soc_736
    DIRECTION INOUT ;
    USE SIGNAL ;
    PORT
      LAYER L1 ;
        RECT  595.281 906.0685 675.281 986.0685 ;
    END
  END soc_736
  PIN soc_737
    DIRECTION INOUT ;
    USE SIGNAL ;
    PORT
      LAYER L1 ;
        RECT  908.881 421.7445 988.881 501.7445 ;
    END
  END soc_737
  PIN soc_738
    DIRECTION INOUT ;
    USE SIGNAL ;
    PORT
      LAYER L1 ;
        RECT  124.881 744.627 204.881 824.627 ;
    END
  END soc_738
  PIN soc_739
    DIRECTION INOUT ;
    USE SIGNAL ;
    PORT
      LAYER L1 ;
        RECT  281.681 744.627 361.681 824.627 ;
    END
  END soc_739
  PIN soc_74
    DIRECTION INOUT ;
    USE SIGNAL ;
    PORT
      LAYER L1 ;
        RECT  3260.881 1227.3135 3340.881 1307.3135 ;
    END
  END soc_74
  PIN soc_740
    DIRECTION INOUT ;
    USE SIGNAL ;
    PORT
      LAYER L1 ;
        RECT  438.481 744.627 518.481 824.627 ;
    END
  END soc_740
  PIN soc_741
    DIRECTION INOUT ;
    USE SIGNAL ;
    PORT
      LAYER L1 ;
        RECT  595.281 740.4565 675.281 820.4565 ;
    END
  END soc_741
  PIN soc_742
    DIRECTION INOUT ;
    USE SIGNAL ;
    PORT
      LAYER L1 ;
        RECT  124.881 583.186 204.881 663.186 ;
    END
  END soc_742
  PIN soc_743
    DIRECTION INOUT ;
    USE SIGNAL ;
    PORT
      LAYER L1 ;
        RECT  281.681 583.186 361.681 663.186 ;
    END
  END soc_743
  PIN soc_744
    DIRECTION INOUT ;
    USE SIGNAL ;
    PORT
      LAYER L1 ;
        RECT  438.481 583.186 518.481 663.186 ;
    END
  END soc_744
  PIN soc_745
    DIRECTION INOUT ;
    USE SIGNAL ;
    PORT
      LAYER L1 ;
        RECT  595.769 583.1685 675.769 663.1685 ;
    END
  END soc_745
  PIN soc_746
    DIRECTION INOUT ;
    USE SIGNAL ;
    PORT
      LAYER L1 ;
        RECT  124.881 421.7445 204.881 501.7445 ;
    END
  END soc_746
  PIN soc_747
    DIRECTION INOUT ;
    USE SIGNAL ;
    PORT
      LAYER L1 ;
        RECT  281.681 421.7445 361.681 501.7445 ;
    END
  END soc_747
  PIN soc_748
    DIRECTION INOUT ;
    USE SIGNAL ;
    PORT
      LAYER L1 ;
        RECT  438.481 421.7445 518.481 501.7445 ;
    END
  END soc_748
  PIN soc_749
    DIRECTION INOUT ;
    USE SIGNAL ;
    PORT
      LAYER L1 ;
        RECT  595.281 421.7445 675.281 501.7445 ;
    END
  END soc_749
  PIN soc_75
    DIRECTION INOUT ;
    USE SIGNAL ;
    PORT
      LAYER L1 ;
        RECT  3104.081 1227.3135 3184.081 1307.3135 ;
    END
  END soc_75
  PIN soc_750
    DIRECTION INOUT ;
    USE SIGNAL ;
    PORT
      LAYER L1 ;
        RECT  752.081 421.7445 832.081 501.7445 ;
    END
  END soc_750
  PIN soc_751
    DIRECTION INOUT ;
    USE SIGNAL ;
    PORT
      LAYER L1 ;
        RECT  124.881 260.3035 204.881 340.3035 ;
    END
  END soc_751
  PIN soc_752
    DIRECTION INOUT ;
    USE SIGNAL ;
    PORT
      LAYER L1 ;
        RECT  281.681 260.3035 361.681 340.3035 ;
    END
  END soc_752
  PIN soc_753
    DIRECTION INOUT ;
    USE SIGNAL ;
    PORT
      LAYER L1 ;
        RECT  595.281 260.3035 675.281 340.3035 ;
    END
  END soc_753
  PIN soc_754
    DIRECTION INOUT ;
    USE SIGNAL ;
    PORT
      LAYER L1 ;
        RECT  752.081 260.3035 832.081 340.3035 ;
    END
  END soc_754
  PIN soc_755
    DIRECTION INOUT ;
    USE SIGNAL ;
    PORT
      LAYER L1 ;
        RECT  908.881 260.3035 988.881 340.3035 ;
    END
  END soc_755
  PIN soc_756
    DIRECTION INOUT ;
    USE SIGNAL ;
    PORT
      LAYER L1 ;
        RECT  281.681 98.862 361.681 178.862 ;
    END
  END soc_756
  PIN soc_757
    DIRECTION INOUT ;
    USE SIGNAL ;
    PORT
      LAYER L1 ;
        RECT  595.281 98.862 675.281 178.862 ;
    END
  END soc_757
  PIN soc_758
    DIRECTION INOUT ;
    USE SIGNAL ;
    PORT
      LAYER L1 ;
        RECT  752.081 98.862 832.081 178.862 ;
    END
  END soc_758
  PIN soc_759
    DIRECTION INOUT ;
    USE SIGNAL ;
    PORT
      LAYER L1 ;
        RECT  908.881 98.862 988.881 178.862 ;
    END
  END soc_759
  PIN soc_76
    DIRECTION INOUT ;
    USE SIGNAL ;
    PORT
      LAYER L1 ;
        RECT  3731.281 1388.7545 3811.281 1468.7545 ;
    END
  END soc_76
  PIN soc_760
    DIRECTION INOUT ;
    USE SIGNAL ;
    PORT
      LAYER L1 ;
        RECT  438.481 260.3035 518.481 340.3035 ;
    END
  END soc_760
  PIN soc_761
    DIRECTION INOUT ;
    USE SIGNAL ;
    PORT
      LAYER L1 ;
        RECT  438.481 98.862 518.481 178.862 ;
    END
  END soc_761
  PIN soc_762
    DIRECTION INOUT ;
    USE SIGNAL ;
    PORT
      LAYER L1 ;
        RECT  3731.281 7010.864 3811.281 7090.864 ;
    END
  END soc_762
  PIN soc_763
    DIRECTION INOUT ;
    USE SIGNAL ;
    PORT
      LAYER L1 ;
        RECT  3574.481 7010.864 3654.481 7090.864 ;
    END
  END soc_763
  PIN soc_764
    DIRECTION INOUT ;
    USE SIGNAL ;
    PORT
      LAYER L1 ;
        RECT  3260.881 7010.864 3340.881 7090.864 ;
    END
  END soc_764
  PIN soc_765
    DIRECTION INOUT ;
    USE SIGNAL ;
    PORT
      LAYER L1 ;
        RECT  3104.081 7010.864 3184.081 7090.864 ;
    END
  END soc_765
  PIN soc_766
    DIRECTION INOUT ;
    USE SIGNAL ;
    PORT
      LAYER L1 ;
        RECT  2476.881 6716.317 2556.881 6796.317 ;
    END
  END soc_766
  PIN soc_767
    DIRECTION INOUT ;
    USE SIGNAL ;
    PORT
      LAYER L1 ;
        RECT  2320.081 6716.317 2400.081 6796.317 ;
    END
  END soc_767
  PIN soc_768
    DIRECTION INOUT ;
    USE SIGNAL ;
    PORT
      LAYER L1 ;
        RECT  2163.281 6716.317 2243.281 6796.317 ;
    END
  END soc_768
  PIN soc_769
    DIRECTION INOUT ;
    USE SIGNAL ;
    PORT
      LAYER L1 ;
        RECT  2006.481 6716.317 2086.481 6796.317 ;
    END
  END soc_769
  PIN soc_77
    DIRECTION INOUT ;
    USE SIGNAL ;
    PORT
      LAYER L1 ;
        RECT  3574.481 1388.7545 3654.481 1468.7545 ;
    END
  END soc_77
  PIN soc_770
    DIRECTION INOUT ;
    USE SIGNAL ;
    PORT
      LAYER L1 ;
        RECT  1849.681 6716.317 1929.681 6796.317 ;
    END
  END soc_770
  PIN soc_771
    DIRECTION INOUT ;
    USE SIGNAL ;
    PORT
      LAYER L1 ;
        RECT  1692.881 6716.317 1772.881 6796.317 ;
    END
  END soc_771
  PIN soc_772
    DIRECTION INOUT ;
    USE SIGNAL ;
    PORT
      LAYER L1 ;
        RECT  1536.081 6716.317 1616.081 6796.317 ;
    END
  END soc_772
  PIN soc_773
    DIRECTION INOUT ;
    USE SIGNAL ;
    PORT
      LAYER L1 ;
        RECT  1379.281 6716.317 1459.281 6796.317 ;
    END
  END soc_773
  PIN soc_774
    DIRECTION INOUT ;
    USE SIGNAL ;
    PORT
      LAYER L1 ;
        RECT  1222.481 6716.317 1302.481 6796.317 ;
    END
  END soc_774
  PIN soc_775
    DIRECTION INOUT ;
    USE SIGNAL ;
    PORT
      LAYER L1 ;
        RECT  1065.681 6716.317 1145.681 6796.317 ;
    END
  END soc_775
  PIN soc_776
    DIRECTION INOUT ;
    USE SIGNAL ;
    PORT
      LAYER L1 ;
        RECT  908.881 6716.317 988.881 6796.317 ;
    END
  END soc_776
  PIN soc_777
    DIRECTION INOUT ;
    USE SIGNAL ;
    PORT
      LAYER L1 ;
        RECT  752.081 6716.317 832.081 6796.317 ;
    END
  END soc_777
  PIN soc_778
    DIRECTION INOUT ;
    USE SIGNAL ;
    PORT
      LAYER L1 ;
        RECT  595.281 6716.317 675.281 6796.317 ;
    END
  END soc_778
  PIN soc_779
    DIRECTION INOUT ;
    USE SIGNAL ;
    PORT
      LAYER L1 ;
        RECT  438.481 6716.317 518.481 6796.317 ;
    END
  END soc_779
  PIN soc_78
    DIRECTION INOUT ;
    USE SIGNAL ;
    PORT
      LAYER L1 ;
        RECT  3260.881 1388.7545 3340.881 1468.7545 ;
    END
  END soc_78
  PIN soc_780
    DIRECTION INOUT ;
    USE SIGNAL ;
    PORT
      LAYER L1 ;
        RECT  281.681 6716.317 361.681 6796.317 ;
    END
  END soc_780
  PIN soc_781
    DIRECTION INOUT ;
    USE SIGNAL ;
    PORT
      LAYER L1 ;
        RECT  124.881 6716.317 204.881 6796.317 ;
    END
  END soc_781
  PIN soc_782
    DIRECTION INOUT ;
    USE SIGNAL ;
    PORT
      LAYER L1 ;
        RECT  2476.881 7200.641 2556.881 7280.641 ;
    END
  END soc_782
  PIN soc_783
    DIRECTION INOUT ;
    USE SIGNAL ;
    PORT
      LAYER L1 ;
        RECT  2320.081 7200.641 2400.081 7280.641 ;
    END
  END soc_783
  PIN soc_784
    DIRECTION INOUT ;
    USE SIGNAL ;
    PORT
      LAYER L1 ;
        RECT  2163.281 7200.641 2243.281 7280.641 ;
    END
  END soc_784
  PIN soc_785
    DIRECTION INOUT ;
    USE SIGNAL ;
    PORT
      LAYER L1 ;
        RECT  2006.481 7200.641 2086.481 7280.641 ;
    END
  END soc_785
  PIN soc_786
    DIRECTION INOUT ;
    USE SIGNAL ;
    PORT
      LAYER L1 ;
        RECT  1849.681 7200.641 1929.681 7280.641 ;
    END
  END soc_786
  PIN soc_787
    DIRECTION INOUT ;
    USE SIGNAL ;
    PORT
      LAYER L1 ;
        RECT  1692.881 7200.641 1772.881 7280.641 ;
    END
  END soc_787
  PIN soc_788
    DIRECTION INOUT ;
    USE SIGNAL ;
    PORT
      LAYER L1 ;
        RECT  1536.081 7200.641 1616.081 7280.641 ;
    END
  END soc_788
  PIN soc_789
    DIRECTION INOUT ;
    USE SIGNAL ;
    PORT
      LAYER L1 ;
        RECT  1379.281 7200.641 1459.281 7280.641 ;
    END
  END soc_789
  PIN soc_79
    DIRECTION INOUT ;
    USE SIGNAL ;
    PORT
      LAYER L1 ;
        RECT  3104.081 1388.7545 3184.081 1468.7545 ;
    END
  END soc_79
  PIN soc_790
    DIRECTION INOUT ;
    USE SIGNAL ;
    PORT
      LAYER L1 ;
        RECT  1222.481 7200.641 1302.481 7280.641 ;
    END
  END soc_790
  PIN soc_791
    DIRECTION INOUT ;
    USE SIGNAL ;
    PORT
      LAYER L1 ;
        RECT  1065.681 7200.641 1145.681 7280.641 ;
    END
  END soc_791
  PIN soc_792
    DIRECTION INOUT ;
    USE SIGNAL ;
    PORT
      LAYER L1 ;
        RECT  908.881 7200.641 988.881 7280.641 ;
    END
  END soc_792
  PIN soc_793
    DIRECTION INOUT ;
    USE SIGNAL ;
    PORT
      LAYER L1 ;
        RECT  752.081 7200.641 832.081 7280.641 ;
    END
  END soc_793
  PIN soc_794
    DIRECTION INOUT ;
    USE SIGNAL ;
    PORT
      LAYER L1 ;
        RECT  595.281 7200.641 675.281 7280.641 ;
    END
  END soc_794
  PIN soc_795
    DIRECTION INOUT ;
    USE SIGNAL ;
    PORT
      LAYER L1 ;
        RECT  438.481 7200.641 518.481 7280.641 ;
    END
  END soc_795
  PIN soc_796
    DIRECTION INOUT ;
    USE SIGNAL ;
    PORT
      LAYER L1 ;
        RECT  281.681 7200.641 361.681 7280.641 ;
    END
  END soc_796
  PIN soc_797
    DIRECTION INOUT ;
    USE SIGNAL ;
    PORT
      LAYER L1 ;
        RECT  2712.081 3473.3235 2792.081 3553.3235 ;
    END
  END soc_797
  PIN soc_798
    DIRECTION INOUT ;
    USE SIGNAL ;
    PORT
      LAYER L1 ;
        RECT  3339.281 3473.3235 3419.281 3553.3235 ;
    END
  END soc_798
  PIN soc_799
    DIRECTION INOUT ;
    USE SIGNAL ;
    PORT
      LAYER L1 ;
        RECT  3496.081 3473.3235 3576.081 3553.3235 ;
    END
  END soc_799
  PIN soc_8
    DIRECTION INOUT ;
    USE SIGNAL ;
    PORT
      LAYER L1 ;
        RECT  1065.681 7039.1995 1145.681 7119.1995 ;
    END
  END soc_8
  PIN soc_80
    DIRECTION INOUT ;
    USE SIGNAL ;
    PORT
      LAYER L1 ;
        RECT  3731.281 1550.196 3811.281 1630.196 ;
    END
  END soc_80
  PIN soc_800
    DIRECTION INOUT ;
    USE SIGNAL ;
    PORT
      LAYER L1 ;
        RECT  3652.881 3473.3235 3732.881 3553.3235 ;
    END
  END soc_800
  PIN soc_801
    DIRECTION INOUT ;
    USE SIGNAL ;
    PORT
      LAYER L1 ;
        RECT  2633.681 7010.864 2713.681 7090.864 ;
    END
  END soc_801
  PIN soc_802
    DIRECTION INOUT ;
    USE SIGNAL ;
    PORT
      LAYER L1 ;
        RECT  2790.481 7010.864 2870.481 7090.864 ;
    END
  END soc_802
  PIN soc_803
    DIRECTION INOUT ;
    USE SIGNAL ;
    PORT
      LAYER L1 ;
        RECT  2947.281 7010.864 3027.281 7090.864 ;
    END
  END soc_803
  PIN soc_804
    DIRECTION INOUT ;
    USE SIGNAL ;
    PORT
      LAYER L1 ;
        RECT  3417.681 7010.864 3497.681 7090.864 ;
    END
  END soc_804
  PIN soc_805
    DIRECTION INOUT ;
    USE SIGNAL ;
    PORT
      LAYER L1 ;
        RECT  2476.881 2359.04 2556.881 2439.04 ;
    END
  END soc_805
  PIN soc_806
    DIRECTION INOUT ;
    USE SIGNAL ;
    PORT
      LAYER L1 ;
        RECT  2320.081 2359.04 2400.081 2439.04 ;
    END
  END soc_806
  PIN soc_807
    DIRECTION INOUT ;
    USE SIGNAL ;
    PORT
      LAYER L1 ;
        RECT  2476.881 2681.9225 2556.881 2761.9225 ;
    END
  END soc_807
  PIN soc_808
    DIRECTION INOUT ;
    USE SIGNAL ;
    PORT
      LAYER L1 ;
        RECT  2320.081 2681.9225 2400.081 2761.9225 ;
    END
  END soc_808
  PIN soc_809
    DIRECTION INOUT ;
    USE SIGNAL ;
    PORT
      LAYER L1 ;
        RECT  3731.281 3620.597 3811.281 3700.597 ;
    END
  END soc_809
  PIN soc_81
    DIRECTION INOUT ;
    USE SIGNAL ;
    PORT
      LAYER L1 ;
        RECT  3574.481 1550.196 3654.481 1630.196 ;
    END
  END soc_81
  PIN soc_810
    DIRECTION INOUT ;
    USE SIGNAL ;
    PORT
      LAYER L1 ;
        RECT  3417.681 3620.597 3497.681 3700.597 ;
    END
  END soc_810
  PIN soc_811
    DIRECTION INOUT ;
    USE SIGNAL ;
    PORT
      LAYER L1 ;
        RECT  3260.881 3620.597 3340.881 3700.597 ;
    END
  END soc_811
  PIN soc_812
    DIRECTION INOUT ;
    USE SIGNAL ;
    PORT
      LAYER L1 ;
        RECT  3058.3545 3625.2155 3138.3545 3705.2155 ;
    END
  END soc_812
  PIN soc_813
    DIRECTION INOUT ;
    USE SIGNAL ;
    PORT
      LAYER L1 ;
        RECT  3058.3545 3468.4155 3138.3545 3548.4155 ;
    END
  END soc_813
  PIN soc_814
    DIRECTION INOUT ;
    USE SIGNAL ;
    PORT
      LAYER L1 ;
        RECT  2915.006 3546.8155 2995.006 3626.8155 ;
    END
  END soc_814
  PIN soc_815
    DIRECTION INOUT ;
    USE SIGNAL ;
    PORT
      LAYER L1 ;
        RECT  3731.281 3782.038 3811.281 3862.038 ;
    END
  END soc_815
  PIN soc_816
    DIRECTION INOUT ;
    USE SIGNAL ;
    PORT
      LAYER L1 ;
        RECT  3417.681 3782.038 3497.681 3862.038 ;
    END
  END soc_816
  PIN soc_817
    DIRECTION INOUT ;
    USE SIGNAL ;
    PORT
      LAYER L1 ;
        RECT  3260.881 3782.038 3340.881 3862.038 ;
    END
  END soc_817
  PIN soc_818
    DIRECTION INOUT ;
    USE SIGNAL ;
    PORT
      LAYER L1 ;
        RECT  3058.3545 3782.0155 3138.3545 3862.0155 ;
    END
  END soc_818
  PIN soc_819
    DIRECTION INOUT ;
    USE SIGNAL ;
    PORT
      LAYER L1 ;
        RECT  2915.006 3703.6155 2995.006 3783.6155 ;
    END
  END soc_819
  PIN soc_82
    DIRECTION INOUT ;
    USE SIGNAL ;
    PORT
      LAYER L1 ;
        RECT  3260.881 1550.196 3340.881 1630.196 ;
    END
  END soc_82
  PIN soc_820
    DIRECTION INOUT ;
    USE SIGNAL ;
    PORT
      LAYER L1 ;
        RECT  2633.681 3782.038 2713.681 3862.038 ;
    END
  END soc_820
  PIN soc_821
    DIRECTION INOUT ;
    USE SIGNAL ;
    PORT
      LAYER L1 ;
        RECT  3417.681 3943.4795 3497.681 4023.4795 ;
    END
  END soc_821
  PIN soc_822
    DIRECTION INOUT ;
    USE SIGNAL ;
    PORT
      LAYER L1 ;
        RECT  2947.281 3943.4795 3027.281 4023.4795 ;
    END
  END soc_822
  PIN soc_823
    DIRECTION INOUT ;
    USE SIGNAL ;
    PORT
      LAYER L1 ;
        RECT  2790.481 3943.4795 2870.481 4023.4795 ;
    END
  END soc_823
  PIN soc_824
    DIRECTION INOUT ;
    USE SIGNAL ;
    PORT
      LAYER L1 ;
        RECT  2633.681 3943.4795 2713.681 4023.4795 ;
    END
  END soc_824
  PIN soc_825
    DIRECTION INOUT ;
    USE SIGNAL ;
    PORT
      LAYER L1 ;
        RECT  3417.681 4104.921 3497.681 4184.921 ;
    END
  END soc_825
  PIN soc_826
    DIRECTION INOUT ;
    USE SIGNAL ;
    PORT
      LAYER L1 ;
        RECT  2947.281 4104.921 3027.281 4184.921 ;
    END
  END soc_826
  PIN soc_827
    DIRECTION INOUT ;
    USE SIGNAL ;
    PORT
      LAYER L1 ;
        RECT  2790.481 4104.921 2870.481 4184.921 ;
    END
  END soc_827
  PIN soc_828
    DIRECTION INOUT ;
    USE SIGNAL ;
    PORT
      LAYER L1 ;
        RECT  2633.681 4104.921 2713.681 4184.921 ;
    END
  END soc_828
  PIN soc_829
    DIRECTION INOUT ;
    USE SIGNAL ;
    PORT
      LAYER L1 ;
        RECT  3417.681 4266.362 3497.681 4346.362 ;
    END
  END soc_829
  PIN soc_83
    DIRECTION INOUT ;
    USE SIGNAL ;
    PORT
      LAYER L1 ;
        RECT  3104.081 1550.196 3184.081 1630.196 ;
    END
  END soc_83
  PIN soc_830
    DIRECTION INOUT ;
    USE SIGNAL ;
    PORT
      LAYER L1 ;
        RECT  2947.281 4266.362 3027.281 4346.362 ;
    END
  END soc_830
  PIN soc_831
    DIRECTION INOUT ;
    USE SIGNAL ;
    PORT
      LAYER L1 ;
        RECT  2790.481 4266.362 2870.481 4346.362 ;
    END
  END soc_831
  PIN soc_832
    DIRECTION INOUT ;
    USE SIGNAL ;
    PORT
      LAYER L1 ;
        RECT  2633.681 4266.362 2713.681 4346.362 ;
    END
  END soc_832
  PIN soc_833
    DIRECTION INOUT ;
    USE SIGNAL ;
    PORT
      LAYER L1 ;
        RECT  3417.681 4427.8035 3497.681 4507.8035 ;
    END
  END soc_833
  PIN soc_834
    DIRECTION INOUT ;
    USE SIGNAL ;
    PORT
      LAYER L1 ;
        RECT  2947.281 4427.8035 3027.281 4507.8035 ;
    END
  END soc_834
  PIN soc_835
    DIRECTION INOUT ;
    USE SIGNAL ;
    PORT
      LAYER L1 ;
        RECT  2790.481 4427.8035 2870.481 4507.8035 ;
    END
  END soc_835
  PIN soc_836
    DIRECTION INOUT ;
    USE SIGNAL ;
    PORT
      LAYER L1 ;
        RECT  2633.681 4427.8035 2713.681 4507.8035 ;
    END
  END soc_836
  PIN soc_837
    DIRECTION INOUT ;
    USE SIGNAL ;
    PORT
      LAYER L1 ;
        RECT  3417.681 4589.2445 3497.681 4669.2445 ;
    END
  END soc_837
  PIN soc_838
    DIRECTION INOUT ;
    USE SIGNAL ;
    PORT
      LAYER L1 ;
        RECT  2947.281 4589.2445 3027.281 4669.2445 ;
    END
  END soc_838
  PIN soc_839
    DIRECTION INOUT ;
    USE SIGNAL ;
    PORT
      LAYER L1 ;
        RECT  2790.481 4589.2445 2870.481 4669.2445 ;
    END
  END soc_839
  PIN soc_84
    DIRECTION INOUT ;
    USE SIGNAL ;
    PORT
      LAYER L1 ;
        RECT  3731.281 1711.6375 3811.281 1791.6375 ;
    END
  END soc_84
  PIN soc_840
    DIRECTION INOUT ;
    USE SIGNAL ;
    PORT
      LAYER L1 ;
        RECT  2633.681 4589.2445 2713.681 4669.2445 ;
    END
  END soc_840
  PIN soc_841
    DIRECTION INOUT ;
    USE SIGNAL ;
    PORT
      LAYER L1 ;
        RECT  3417.681 4750.686 3497.681 4830.686 ;
    END
  END soc_841
  PIN soc_842
    DIRECTION INOUT ;
    USE SIGNAL ;
    PORT
      LAYER L1 ;
        RECT  2947.281 4750.686 3027.281 4830.686 ;
    END
  END soc_842
  PIN soc_843
    DIRECTION INOUT ;
    USE SIGNAL ;
    PORT
      LAYER L1 ;
        RECT  2790.481 4750.686 2870.481 4830.686 ;
    END
  END soc_843
  PIN soc_844
    DIRECTION INOUT ;
    USE SIGNAL ;
    PORT
      LAYER L1 ;
        RECT  2633.681 4750.686 2713.681 4830.686 ;
    END
  END soc_844
  PIN soc_845
    DIRECTION INOUT ;
    USE SIGNAL ;
    PORT
      LAYER L1 ;
        RECT  3417.681 4912.127 3497.681 4992.127 ;
    END
  END soc_845
  PIN soc_846
    DIRECTION INOUT ;
    USE SIGNAL ;
    PORT
      LAYER L1 ;
        RECT  2947.281 4912.127 3027.281 4992.127 ;
    END
  END soc_846
  PIN soc_847
    DIRECTION INOUT ;
    USE SIGNAL ;
    PORT
      LAYER L1 ;
        RECT  2790.481 4912.127 2870.481 4992.127 ;
    END
  END soc_847
  PIN soc_848
    DIRECTION INOUT ;
    USE SIGNAL ;
    PORT
      LAYER L1 ;
        RECT  2633.681 4912.127 2713.681 4992.127 ;
    END
  END soc_848
  PIN soc_849
    DIRECTION INOUT ;
    USE SIGNAL ;
    PORT
      LAYER L1 ;
        RECT  3417.681 5073.5685 3497.681 5153.5685 ;
    END
  END soc_849
  PIN soc_85
    DIRECTION INOUT ;
    USE SIGNAL ;
    PORT
      LAYER L1 ;
        RECT  3574.481 1711.6375 3654.481 1791.6375 ;
    END
  END soc_85
  PIN soc_850
    DIRECTION INOUT ;
    USE SIGNAL ;
    PORT
      LAYER L1 ;
        RECT  2947.281 5073.5685 3027.281 5153.5685 ;
    END
  END soc_850
  PIN soc_851
    DIRECTION INOUT ;
    USE SIGNAL ;
    PORT
      LAYER L1 ;
        RECT  2790.481 5073.5685 2870.481 5153.5685 ;
    END
  END soc_851
  PIN soc_852
    DIRECTION INOUT ;
    USE SIGNAL ;
    PORT
      LAYER L1 ;
        RECT  2633.681 5073.5685 2713.681 5153.5685 ;
    END
  END soc_852
  PIN soc_853
    DIRECTION INOUT ;
    USE SIGNAL ;
    PORT
      LAYER L1 ;
        RECT  3417.681 5235.0095 3497.681 5315.0095 ;
    END
  END soc_853
  PIN soc_854
    DIRECTION INOUT ;
    USE SIGNAL ;
    PORT
      LAYER L1 ;
        RECT  2947.281 5235.0095 3027.281 5315.0095 ;
    END
  END soc_854
  PIN soc_855
    DIRECTION INOUT ;
    USE SIGNAL ;
    PORT
      LAYER L1 ;
        RECT  2790.481 5235.0095 2870.481 5315.0095 ;
    END
  END soc_855
  PIN soc_856
    DIRECTION INOUT ;
    USE SIGNAL ;
    PORT
      LAYER L1 ;
        RECT  2633.681 5235.0095 2713.681 5315.0095 ;
    END
  END soc_856
  PIN soc_857
    DIRECTION INOUT ;
    USE SIGNAL ;
    PORT
      LAYER L1 ;
        RECT  3417.681 5396.451 3497.681 5476.451 ;
    END
  END soc_857
  PIN soc_858
    DIRECTION INOUT ;
    USE SIGNAL ;
    PORT
      LAYER L1 ;
        RECT  2947.281 5396.451 3027.281 5476.451 ;
    END
  END soc_858
  PIN soc_859
    DIRECTION INOUT ;
    USE SIGNAL ;
    PORT
      LAYER L1 ;
        RECT  2790.481 5396.451 2870.481 5476.451 ;
    END
  END soc_859
  PIN soc_86
    DIRECTION INOUT ;
    USE SIGNAL ;
    PORT
      LAYER L1 ;
        RECT  3260.881 1711.6375 3340.881 1791.6375 ;
    END
  END soc_86
  PIN soc_860
    DIRECTION INOUT ;
    USE SIGNAL ;
    PORT
      LAYER L1 ;
        RECT  2633.681 5396.451 2713.681 5476.451 ;
    END
  END soc_860
  PIN soc_861
    DIRECTION INOUT ;
    USE SIGNAL ;
    PORT
      LAYER L1 ;
        RECT  3417.681 5557.8925 3497.681 5637.8925 ;
    END
  END soc_861
  PIN soc_862
    DIRECTION INOUT ;
    USE SIGNAL ;
    PORT
      LAYER L1 ;
        RECT  2947.281 5557.8925 3027.281 5637.8925 ;
    END
  END soc_862
  PIN soc_863
    DIRECTION INOUT ;
    USE SIGNAL ;
    PORT
      LAYER L1 ;
        RECT  2790.481 5557.8925 2870.481 5637.8925 ;
    END
  END soc_863
  PIN soc_864
    DIRECTION INOUT ;
    USE SIGNAL ;
    PORT
      LAYER L1 ;
        RECT  2633.681 5557.8925 2713.681 5637.8925 ;
    END
  END soc_864
  PIN soc_865
    DIRECTION INOUT ;
    USE SIGNAL ;
    PORT
      LAYER L1 ;
        RECT  3417.681 5719.3335 3497.681 5799.3335 ;
    END
  END soc_865
  PIN soc_866
    DIRECTION INOUT ;
    USE SIGNAL ;
    PORT
      LAYER L1 ;
        RECT  2947.281 5719.3335 3027.281 5799.3335 ;
    END
  END soc_866
  PIN soc_867
    DIRECTION INOUT ;
    USE SIGNAL ;
    PORT
      LAYER L1 ;
        RECT  2790.481 5719.3335 2870.481 5799.3335 ;
    END
  END soc_867
  PIN soc_868
    DIRECTION INOUT ;
    USE SIGNAL ;
    PORT
      LAYER L1 ;
        RECT  2633.681 5719.3335 2713.681 5799.3335 ;
    END
  END soc_868
  PIN soc_869
    DIRECTION INOUT ;
    USE SIGNAL ;
    PORT
      LAYER L1 ;
        RECT  3417.681 5880.775 3497.681 5960.775 ;
    END
  END soc_869
  PIN soc_87
    DIRECTION INOUT ;
    USE SIGNAL ;
    PORT
      LAYER L1 ;
        RECT  3104.081 1711.6375 3184.081 1791.6375 ;
    END
  END soc_87
  PIN soc_870
    DIRECTION INOUT ;
    USE SIGNAL ;
    PORT
      LAYER L1 ;
        RECT  2947.281 5880.775 3027.281 5960.775 ;
    END
  END soc_870
  PIN soc_871
    DIRECTION INOUT ;
    USE SIGNAL ;
    PORT
      LAYER L1 ;
        RECT  2790.481 5880.775 2870.481 5960.775 ;
    END
  END soc_871
  PIN soc_872
    DIRECTION INOUT ;
    USE SIGNAL ;
    PORT
      LAYER L1 ;
        RECT  2633.681 5880.775 2713.681 5960.775 ;
    END
  END soc_872
  PIN soc_873
    DIRECTION INOUT ;
    USE SIGNAL ;
    PORT
      LAYER L1 ;
        RECT  3417.681 6042.216 3497.681 6122.216 ;
    END
  END soc_873
  PIN soc_874
    DIRECTION INOUT ;
    USE SIGNAL ;
    PORT
      LAYER L1 ;
        RECT  2947.281 6042.216 3027.281 6122.216 ;
    END
  END soc_874
  PIN soc_875
    DIRECTION INOUT ;
    USE SIGNAL ;
    PORT
      LAYER L1 ;
        RECT  2790.481 6042.216 2870.481 6122.216 ;
    END
  END soc_875
  PIN soc_876
    DIRECTION INOUT ;
    USE SIGNAL ;
    PORT
      LAYER L1 ;
        RECT  2633.681 6042.216 2713.681 6122.216 ;
    END
  END soc_876
  PIN soc_877
    DIRECTION INOUT ;
    USE SIGNAL ;
    PORT
      LAYER L1 ;
        RECT  3417.681 6203.6575 3497.681 6283.6575 ;
    END
  END soc_877
  PIN soc_878
    DIRECTION INOUT ;
    USE SIGNAL ;
    PORT
      LAYER L1 ;
        RECT  2947.281 6203.6575 3027.281 6283.6575 ;
    END
  END soc_878
  PIN soc_879
    DIRECTION INOUT ;
    USE SIGNAL ;
    PORT
      LAYER L1 ;
        RECT  2790.481 6203.6575 2870.481 6283.6575 ;
    END
  END soc_879
  PIN soc_88
    DIRECTION INOUT ;
    USE SIGNAL ;
    PORT
      LAYER L1 ;
        RECT  3731.281 1873.0785 3811.281 1953.0785 ;
    END
  END soc_88
  PIN soc_880
    DIRECTION INOUT ;
    USE SIGNAL ;
    PORT
      LAYER L1 ;
        RECT  2633.681 6203.6575 2713.681 6283.6575 ;
    END
  END soc_880
  PIN soc_881
    DIRECTION INOUT ;
    USE SIGNAL ;
    PORT
      LAYER L1 ;
        RECT  3417.681 6365.0985 3497.681 6445.0985 ;
    END
  END soc_881
  PIN soc_882
    DIRECTION INOUT ;
    USE SIGNAL ;
    PORT
      LAYER L1 ;
        RECT  2947.281 6365.0985 3027.281 6445.0985 ;
    END
  END soc_882
  PIN soc_883
    DIRECTION INOUT ;
    USE SIGNAL ;
    PORT
      LAYER L1 ;
        RECT  2790.481 6365.0985 2870.481 6445.0985 ;
    END
  END soc_883
  PIN soc_884
    DIRECTION INOUT ;
    USE SIGNAL ;
    PORT
      LAYER L1 ;
        RECT  2633.681 6365.0985 2713.681 6445.0985 ;
    END
  END soc_884
  PIN soc_885
    DIRECTION INOUT ;
    USE SIGNAL ;
    PORT
      LAYER L1 ;
        RECT  3417.681 6526.54 3497.681 6606.54 ;
    END
  END soc_885
  PIN soc_886
    DIRECTION INOUT ;
    USE SIGNAL ;
    PORT
      LAYER L1 ;
        RECT  2947.281 6526.54 3027.281 6606.54 ;
    END
  END soc_886
  PIN soc_887
    DIRECTION INOUT ;
    USE SIGNAL ;
    PORT
      LAYER L1 ;
        RECT  2790.481 6526.54 2870.481 6606.54 ;
    END
  END soc_887
  PIN soc_888
    DIRECTION INOUT ;
    USE SIGNAL ;
    PORT
      LAYER L1 ;
        RECT  2633.681 6526.54 2713.681 6606.54 ;
    END
  END soc_888
  PIN soc_889
    DIRECTION INOUT ;
    USE SIGNAL ;
    PORT
      LAYER L1 ;
        RECT  3417.681 6687.9815 3497.681 6767.9815 ;
    END
  END soc_889
  PIN soc_89
    DIRECTION INOUT ;
    USE SIGNAL ;
    PORT
      LAYER L1 ;
        RECT  3574.481 1873.0785 3654.481 1953.0785 ;
    END
  END soc_89
  PIN soc_890
    DIRECTION INOUT ;
    USE SIGNAL ;
    PORT
      LAYER L1 ;
        RECT  2947.281 6687.9815 3027.281 6767.9815 ;
    END
  END soc_890
  PIN soc_891
    DIRECTION INOUT ;
    USE SIGNAL ;
    PORT
      LAYER L1 ;
        RECT  2790.481 6687.9815 2870.481 6767.9815 ;
    END
  END soc_891
  PIN soc_892
    DIRECTION INOUT ;
    USE SIGNAL ;
    PORT
      LAYER L1 ;
        RECT  2633.681 6687.9815 2713.681 6767.9815 ;
    END
  END soc_892
  PIN soc_893
    DIRECTION INOUT ;
    USE SIGNAL ;
    PORT
      LAYER L1 ;
        RECT  3417.681 6849.4225 3497.681 6929.4225 ;
    END
  END soc_893
  PIN soc_894
    DIRECTION INOUT ;
    USE SIGNAL ;
    PORT
      LAYER L1 ;
        RECT  2947.281 6849.4225 3027.281 6929.4225 ;
    END
  END soc_894
  PIN soc_895
    DIRECTION INOUT ;
    USE SIGNAL ;
    PORT
      LAYER L1 ;
        RECT  2790.481 6849.4225 2870.481 6929.4225 ;
    END
  END soc_895
  PIN soc_896
    DIRECTION INOUT ;
    USE SIGNAL ;
    PORT
      LAYER L1 ;
        RECT  2633.681 6849.4225 2713.681 6929.4225 ;
    END
  END soc_896
  PIN soc_897
    DIRECTION INOUT ;
    USE SIGNAL ;
    PORT
      LAYER L1 ;
        RECT  1289.949 1691.4975 1369.949 1771.4975 ;
    END
  END soc_897
  PIN soc_898
    DIRECTION INOUT ;
    USE SIGNAL ;
    PORT
      LAYER L1 ;
        RECT  1564.349 1691.4975 1644.349 1771.4975 ;
    END
  END soc_898
  PIN soc_899
    DIRECTION INOUT ;
    USE SIGNAL ;
    PORT
      LAYER L1 ;
        RECT  1816.277 1691.4975 1896.277 1771.4975 ;
    END
  END soc_899
  PIN soc_9
    DIRECTION INOUT ;
    USE SIGNAL ;
    PORT
      LAYER L1 ;
        RECT  1222.481 7039.1995 1302.481 7119.1995 ;
    END
  END soc_9
  PIN soc_90
    DIRECTION INOUT ;
    USE SIGNAL ;
    PORT
      LAYER L1 ;
        RECT  3260.881 1873.0785 3340.881 1953.0785 ;
    END
  END soc_90
  PIN soc_900
    DIRECTION INOUT ;
    USE SIGNAL ;
    PORT
      LAYER L1 ;
        RECT  2068.2045 1691.4975 2148.2045 1771.4975 ;
    END
  END soc_900
  PIN soc_901
    DIRECTION INOUT ;
    USE SIGNAL ;
    PORT
      LAYER L1 ;
        RECT  2342.6045 1691.4975 2422.6045 1771.4975 ;
    END
  END soc_901
  PIN soc_902
    DIRECTION INOUT ;
    USE SIGNAL ;
    PORT
      LAYER L1 ;
        RECT  1164.577 1579.9245 1244.577 1659.9245 ;
    END
  END soc_902
  PIN soc_903
    DIRECTION INOUT ;
    USE SIGNAL ;
    PORT
      LAYER L1 ;
        RECT  1289.949 1468.3515 1369.949 1548.3515 ;
    END
  END soc_903
  PIN soc_904
    DIRECTION INOUT ;
    USE SIGNAL ;
    PORT
      LAYER L1 ;
        RECT  1438.977 1579.9245 1518.977 1659.9245 ;
    END
  END soc_904
  PIN soc_905
    DIRECTION INOUT ;
    USE SIGNAL ;
    PORT
      LAYER L1 ;
        RECT  1690.3135 1579.9245 1770.3135 1659.9245 ;
    END
  END soc_905
  PIN soc_906
    DIRECTION INOUT ;
    USE SIGNAL ;
    PORT
      LAYER L1 ;
        RECT  1942.24 1579.9245 2022.24 1659.9245 ;
    END
  END soc_906
  PIN soc_907
    DIRECTION INOUT ;
    USE SIGNAL ;
    PORT
      LAYER L1 ;
        RECT  2068.2045 1468.3515 2148.2045 1548.3515 ;
    END
  END soc_907
  PIN soc_908
    DIRECTION INOUT ;
    USE SIGNAL ;
    PORT
      LAYER L1 ;
        RECT  2193.577 1579.9245 2273.577 1659.9245 ;
    END
  END soc_908
  PIN soc_909
    DIRECTION INOUT ;
    USE SIGNAL ;
    PORT
      LAYER L1 ;
        RECT  2467.977 1579.9245 2547.977 1659.9245 ;
    END
  END soc_909
  PIN soc_91
    DIRECTION INOUT ;
    USE SIGNAL ;
    PORT
      LAYER L1 ;
        RECT  3104.081 1873.0785 3184.081 1953.0785 ;
    END
  END soc_91
  PIN soc_910
    DIRECTION INOUT ;
    USE SIGNAL ;
    PORT
      LAYER L1 ;
        RECT  1564.349 1468.3515 1644.349 1548.3515 ;
    END
  END soc_910
  PIN soc_911
    DIRECTION INOUT ;
    USE SIGNAL ;
    PORT
      LAYER L1 ;
        RECT  1697.693 1351.3195 1777.693 1431.3195 ;
    END
  END soc_911
  PIN soc_912
    DIRECTION INOUT ;
    USE SIGNAL ;
    PORT
      LAYER L1 ;
        RECT  1816.277 1468.3515 1896.277 1548.3515 ;
    END
  END soc_912
  PIN soc_913
    DIRECTION INOUT ;
    USE SIGNAL ;
    PORT
      LAYER L1 ;
        RECT  2342.6045 1468.3515 2422.6045 1548.3515 ;
    END
  END soc_913
  PIN soc_914
    DIRECTION INOUT ;
    USE SIGNAL ;
    PORT
      LAYER L1 ;
        RECT  1296.387 1240.8815 1376.387 1320.8815 ;
    END
  END soc_914
  PIN soc_915
    DIRECTION INOUT ;
    USE SIGNAL ;
    PORT
      LAYER L1 ;
        RECT  1570.787 1240.8815 1650.787 1320.8815 ;
    END
  END soc_915
  PIN soc_916
    DIRECTION INOUT ;
    USE SIGNAL ;
    PORT
      LAYER L1 ;
        RECT  2061.767 1240.8815 2141.767 1320.8815 ;
    END
  END soc_916
  PIN soc_917
    DIRECTION INOUT ;
    USE SIGNAL ;
    PORT
      LAYER L1 ;
        RECT  2336.167 1240.8815 2416.167 1320.8815 ;
    END
  END soc_917
  PIN soc_918
    DIRECTION INOUT ;
    USE SIGNAL ;
    PORT
      LAYER L1 ;
        RECT  1296.387 1015.2785 1376.387 1095.2785 ;
    END
  END soc_918
  PIN soc_919
    DIRECTION INOUT ;
    USE SIGNAL ;
    PORT
      LAYER L1 ;
        RECT  1733.957 1018.412 1813.957 1098.412 ;
    END
  END soc_919
  PIN soc_92
    DIRECTION INOUT ;
    USE SIGNAL ;
    PORT
      LAYER L1 ;
        RECT  3731.281 2034.52 3811.281 2114.52 ;
    END
  END soc_92
  PIN soc_920
    DIRECTION INOUT ;
    USE SIGNAL ;
    PORT
      LAYER L1 ;
        RECT  1898.597 1018.412 1978.597 1098.412 ;
    END
  END soc_920
  PIN soc_921
    DIRECTION INOUT ;
    USE SIGNAL ;
    PORT
      LAYER L1 ;
        RECT  2061.767 1015.2785 2141.767 1095.2785 ;
    END
  END soc_921
  PIN soc_922
    DIRECTION INOUT ;
    USE SIGNAL ;
    PORT
      LAYER L1 ;
        RECT  2336.167 1015.2785 2416.167 1095.2785 ;
    END
  END soc_922
  PIN soc_923
    DIRECTION INOUT ;
    USE SIGNAL ;
    PORT
      LAYER L1 ;
        RECT  1161.637 903.4205 1241.637 983.4205 ;
    END
  END soc_923
  PIN soc_924
    DIRECTION INOUT ;
    USE SIGNAL ;
    PORT
      LAYER L1 ;
        RECT  1436.037 903.4205 1516.037 983.4205 ;
    END
  END soc_924
  PIN soc_925
    DIRECTION INOUT ;
    USE SIGNAL ;
    PORT
      LAYER L1 ;
        RECT  1570.787 1015.2785 1650.787 1095.2785 ;
    END
  END soc_925
  PIN soc_926
    DIRECTION INOUT ;
    USE SIGNAL ;
    PORT
      LAYER L1 ;
        RECT  2196.517 903.4205 2276.517 983.4205 ;
    END
  END soc_926
  PIN soc_927
    DIRECTION INOUT ;
    USE SIGNAL ;
    PORT
      LAYER L1 ;
        RECT  2470.917 903.4205 2550.917 983.4205 ;
    END
  END soc_927
  PIN soc_928
    DIRECTION INOUT ;
    USE SIGNAL ;
    PORT
      LAYER L1 ;
        RECT  1161.637 687.2285 1241.637 767.2285 ;
    END
  END soc_928
  PIN soc_929
    DIRECTION INOUT ;
    USE SIGNAL ;
    PORT
      LAYER L1 ;
        RECT  1296.387 788.202 1376.387 868.202 ;
    END
  END soc_929
  PIN soc_93
    DIRECTION INOUT ;
    USE SIGNAL ;
    PORT
      LAYER L1 ;
        RECT  3574.481 2034.52 3654.481 2114.52 ;
    END
  END soc_93
  PIN soc_930
    DIRECTION INOUT ;
    USE SIGNAL ;
    PORT
      LAYER L1 ;
        RECT  1570.787 788.202 1650.787 868.202 ;
    END
  END soc_930
  PIN soc_931
    DIRECTION INOUT ;
    USE SIGNAL ;
    PORT
      LAYER L1 ;
        RECT  2061.767 788.202 2141.767 868.202 ;
    END
  END soc_931
  PIN soc_932
    DIRECTION INOUT ;
    USE SIGNAL ;
    PORT
      LAYER L1 ;
        RECT  2196.517 687.2285 2276.517 767.2285 ;
    END
  END soc_932
  PIN soc_933
    DIRECTION INOUT ;
    USE SIGNAL ;
    PORT
      LAYER L1 ;
        RECT  2336.167 788.202 2416.167 868.202 ;
    END
  END soc_933
  PIN soc_934
    DIRECTION INOUT ;
    USE SIGNAL ;
    PORT
      LAYER L1 ;
        RECT  2470.917 687.2285 2550.917 767.2285 ;
    END
  END soc_934
  PIN soc_935
    DIRECTION INOUT ;
    USE SIGNAL ;
    PORT
      LAYER L1 ;
        RECT  1296.387 586.3545 1376.387 666.3545 ;
    END
  END soc_935
  PIN soc_936
    DIRECTION INOUT ;
    USE SIGNAL ;
    PORT
      LAYER L1 ;
        RECT  1436.037 687.2285 1516.037 767.2285 ;
    END
  END soc_936
  PIN soc_937
    DIRECTION INOUT ;
    USE SIGNAL ;
    PORT
      LAYER L1 ;
        RECT  1570.787 586.3545 1650.787 666.3545 ;
    END
  END soc_937
  PIN soc_938
    DIRECTION INOUT ;
    USE SIGNAL ;
    PORT
      LAYER L1 ;
        RECT  1898.597 608.023 1978.597 688.023 ;
    END
  END soc_938
  PIN soc_939
    DIRECTION INOUT ;
    USE SIGNAL ;
    PORT
      LAYER L1 ;
        RECT  2061.767 586.3545 2141.767 666.3545 ;
    END
  END soc_939
  PIN soc_94
    DIRECTION INOUT ;
    USE SIGNAL ;
    PORT
      LAYER L1 ;
        RECT  3260.881 2034.52 3340.881 2114.52 ;
    END
  END soc_94
  PIN soc_940
    DIRECTION INOUT ;
    USE SIGNAL ;
    PORT
      LAYER L1 ;
        RECT  2336.167 586.3545 2416.167 666.3545 ;
    END
  END soc_940
  PIN soc_941
    DIRECTION INOUT ;
    USE SIGNAL ;
    PORT
      LAYER L1 ;
        RECT  1161.637 485.436 1241.637 565.436 ;
    END
  END soc_941
  PIN soc_942
    DIRECTION INOUT ;
    USE SIGNAL ;
    PORT
      LAYER L1 ;
        RECT  1436.037 485.436 1516.037 565.436 ;
    END
  END soc_942
  PIN soc_943
    DIRECTION INOUT ;
    USE SIGNAL ;
    PORT
      LAYER L1 ;
        RECT  2196.517 485.436 2276.517 565.436 ;
    END
  END soc_943
  PIN soc_944
    DIRECTION INOUT ;
    USE SIGNAL ;
    PORT
      LAYER L1 ;
        RECT  2470.917 485.436 2550.917 565.436 ;
    END
  END soc_944
  PIN soc_945
    DIRECTION INOUT ;
    USE SIGNAL ;
    PORT
      LAYER L1 ;
        RECT  1161.637 198.395 1241.637 278.395 ;
    END
  END soc_945
  PIN soc_946
    DIRECTION INOUT ;
    USE SIGNAL ;
    PORT
      LAYER L1 ;
        RECT  1436.037 198.395 1516.037 278.395 ;
    END
  END soc_946
  PIN soc_947
    DIRECTION INOUT ;
    USE SIGNAL ;
    PORT
      LAYER L1 ;
        RECT  2196.517 198.395 2276.517 278.395 ;
    END
  END soc_947
  PIN soc_948
    DIRECTION INOUT ;
    USE SIGNAL ;
    PORT
      LAYER L1 ;
        RECT  2470.917 198.395 2550.917 278.395 ;
    END
  END soc_948
  PIN soc_949
    DIRECTION INOUT ;
    USE SIGNAL ;
    PORT
      LAYER L1 ;
        RECT  1733.957 119.983 1813.957 199.983 ;
    END
  END soc_949
  PIN soc_95
    DIRECTION INOUT ;
    USE SIGNAL ;
    PORT
      LAYER L1 ;
        RECT  3104.081 2034.52 3184.081 2114.52 ;
    END
  END soc_95
  PIN soc_950
    DIRECTION INOUT ;
    USE SIGNAL ;
    PORT
      LAYER L1 ;
        RECT  1898.597 119.983 1978.597 199.983 ;
    END
  END soc_950
  PIN soc_951
    DIRECTION INOUT ;
    USE SIGNAL ;
    PORT
      LAYER L1 ;
        RECT  2633.681 3326.05 2713.681 3406.05 ;
    END
  END soc_951
  PIN soc_952
    DIRECTION INOUT ;
    USE SIGNAL ;
    PORT
      LAYER L1 ;
        RECT  2790.481 3326.05 2870.481 3406.05 ;
    END
  END soc_952
  PIN soc_953
    DIRECTION INOUT ;
    USE SIGNAL ;
    PORT
      LAYER L1 ;
        RECT  2947.281 3326.05 3027.281 3406.05 ;
    END
  END soc_953
  PIN soc_954
    DIRECTION INOUT ;
    USE SIGNAL ;
    PORT
      LAYER L1 ;
        RECT  2633.681 3164.609 2713.681 3244.609 ;
    END
  END soc_954
  PIN soc_955
    DIRECTION INOUT ;
    USE SIGNAL ;
    PORT
      LAYER L1 ;
        RECT  2790.481 3164.609 2870.481 3244.609 ;
    END
  END soc_955
  PIN soc_956
    DIRECTION INOUT ;
    USE SIGNAL ;
    PORT
      LAYER L1 ;
        RECT  2947.281 3164.609 3027.281 3244.609 ;
    END
  END soc_956
  PIN soc_957
    DIRECTION INOUT ;
    USE SIGNAL ;
    PORT
      LAYER L1 ;
        RECT  3417.681 3164.609 3497.681 3244.609 ;
    END
  END soc_957
  PIN soc_958
    DIRECTION INOUT ;
    USE SIGNAL ;
    PORT
      LAYER L1 ;
        RECT  3731.281 3164.609 3811.281 3244.609 ;
    END
  END soc_958
  PIN soc_959
    DIRECTION INOUT ;
    USE SIGNAL ;
    PORT
      LAYER L1 ;
        RECT  2633.681 3003.1675 2713.681 3083.1675 ;
    END
  END soc_959
  PIN soc_96
    DIRECTION INOUT ;
    USE SIGNAL ;
    PORT
      LAYER L1 ;
        RECT  3731.281 2195.961 3811.281 2275.961 ;
    END
  END soc_96
  PIN soc_960
    DIRECTION INOUT ;
    USE SIGNAL ;
    PORT
      LAYER L1 ;
        RECT  2790.481 3003.1675 2870.481 3083.1675 ;
    END
  END soc_960
  PIN soc_961
    DIRECTION INOUT ;
    USE SIGNAL ;
    PORT
      LAYER L1 ;
        RECT  2947.281 3003.1675 3027.281 3083.1675 ;
    END
  END soc_961
  PIN soc_962
    DIRECTION INOUT ;
    USE SIGNAL ;
    PORT
      LAYER L1 ;
        RECT  3417.681 3003.1675 3497.681 3083.1675 ;
    END
  END soc_962
  PIN soc_963
    DIRECTION INOUT ;
    USE SIGNAL ;
    PORT
      LAYER L1 ;
        RECT  2633.681 2841.7265 2713.681 2921.7265 ;
    END
  END soc_963
  PIN soc_964
    DIRECTION INOUT ;
    USE SIGNAL ;
    PORT
      LAYER L1 ;
        RECT  2790.481 2841.7265 2870.481 2921.7265 ;
    END
  END soc_964
  PIN soc_965
    DIRECTION INOUT ;
    USE SIGNAL ;
    PORT
      LAYER L1 ;
        RECT  2947.281 2841.7265 3027.281 2921.7265 ;
    END
  END soc_965
  PIN soc_966
    DIRECTION INOUT ;
    USE SIGNAL ;
    PORT
      LAYER L1 ;
        RECT  3417.681 2841.7265 3497.681 2921.7265 ;
    END
  END soc_966
  PIN soc_967
    DIRECTION INOUT ;
    USE SIGNAL ;
    PORT
      LAYER L1 ;
        RECT  2633.681 2680.285 2713.681 2760.285 ;
    END
  END soc_967
  PIN soc_968
    DIRECTION INOUT ;
    USE SIGNAL ;
    PORT
      LAYER L1 ;
        RECT  2790.481 2680.285 2870.481 2760.285 ;
    END
  END soc_968
  PIN soc_969
    DIRECTION INOUT ;
    USE SIGNAL ;
    PORT
      LAYER L1 ;
        RECT  2947.281 2680.285 3027.281 2760.285 ;
    END
  END soc_969
  PIN soc_97
    DIRECTION INOUT ;
    USE SIGNAL ;
    PORT
      LAYER L1 ;
        RECT  3574.481 2195.961 3654.481 2275.961 ;
    END
  END soc_97
  PIN soc_970
    DIRECTION INOUT ;
    USE SIGNAL ;
    PORT
      LAYER L1 ;
        RECT  3417.681 2680.285 3497.681 2760.285 ;
    END
  END soc_970
  PIN soc_971
    DIRECTION INOUT ;
    USE SIGNAL ;
    PORT
      LAYER L1 ;
        RECT  2633.681 2518.8435 2713.681 2598.8435 ;
    END
  END soc_971
  PIN soc_972
    DIRECTION INOUT ;
    USE SIGNAL ;
    PORT
      LAYER L1 ;
        RECT  2790.481 2518.8435 2870.481 2598.8435 ;
    END
  END soc_972
  PIN soc_973
    DIRECTION INOUT ;
    USE SIGNAL ;
    PORT
      LAYER L1 ;
        RECT  2947.281 2518.8435 3027.281 2598.8435 ;
    END
  END soc_973
  PIN soc_974
    DIRECTION INOUT ;
    USE SIGNAL ;
    PORT
      LAYER L1 ;
        RECT  3417.681 2518.8435 3497.681 2598.8435 ;
    END
  END soc_974
  PIN soc_975
    DIRECTION INOUT ;
    USE SIGNAL ;
    PORT
      LAYER L1 ;
        RECT  2633.681 2357.4025 2713.681 2437.4025 ;
    END
  END soc_975
  PIN soc_976
    DIRECTION INOUT ;
    USE SIGNAL ;
    PORT
      LAYER L1 ;
        RECT  2790.481 2357.4025 2870.481 2437.4025 ;
    END
  END soc_976
  PIN soc_977
    DIRECTION INOUT ;
    USE SIGNAL ;
    PORT
      LAYER L1 ;
        RECT  2947.281 2357.4025 3027.281 2437.4025 ;
    END
  END soc_977
  PIN soc_978
    DIRECTION INOUT ;
    USE SIGNAL ;
    PORT
      LAYER L1 ;
        RECT  3417.681 2357.4025 3497.681 2437.4025 ;
    END
  END soc_978
  PIN soc_979
    DIRECTION INOUT ;
    USE SIGNAL ;
    PORT
      LAYER L1 ;
        RECT  2633.681 2195.961 2713.681 2275.961 ;
    END
  END soc_979
  PIN soc_98
    DIRECTION INOUT ;
    USE SIGNAL ;
    PORT
      LAYER L1 ;
        RECT  3260.881 2195.961 3340.881 2275.961 ;
    END
  END soc_98
  PIN soc_980
    DIRECTION INOUT ;
    USE SIGNAL ;
    PORT
      LAYER L1 ;
        RECT  2790.481 2195.961 2870.481 2275.961 ;
    END
  END soc_980
  PIN soc_981
    DIRECTION INOUT ;
    USE SIGNAL ;
    PORT
      LAYER L1 ;
        RECT  2947.281 2195.961 3027.281 2275.961 ;
    END
  END soc_981
  PIN soc_982
    DIRECTION INOUT ;
    USE SIGNAL ;
    PORT
      LAYER L1 ;
        RECT  3417.681 2195.961 3497.681 2275.961 ;
    END
  END soc_982
  PIN soc_983
    DIRECTION INOUT ;
    USE SIGNAL ;
    PORT
      LAYER L1 ;
        RECT  2633.681 2034.52 2713.681 2114.52 ;
    END
  END soc_983
  PIN soc_984
    DIRECTION INOUT ;
    USE SIGNAL ;
    PORT
      LAYER L1 ;
        RECT  2790.481 2034.52 2870.481 2114.52 ;
    END
  END soc_984
  PIN soc_985
    DIRECTION INOUT ;
    USE SIGNAL ;
    PORT
      LAYER L1 ;
        RECT  2947.281 2034.52 3027.281 2114.52 ;
    END
  END soc_985
  PIN soc_986
    DIRECTION INOUT ;
    USE SIGNAL ;
    PORT
      LAYER L1 ;
        RECT  3417.681 2034.52 3497.681 2114.52 ;
    END
  END soc_986
  PIN soc_987
    DIRECTION INOUT ;
    USE SIGNAL ;
    PORT
      LAYER L1 ;
        RECT  2633.681 1873.0785 2713.681 1953.0785 ;
    END
  END soc_987
  PIN soc_988
    DIRECTION INOUT ;
    USE SIGNAL ;
    PORT
      LAYER L1 ;
        RECT  2790.481 1873.0785 2870.481 1953.0785 ;
    END
  END soc_988
  PIN soc_989
    DIRECTION INOUT ;
    USE SIGNAL ;
    PORT
      LAYER L1 ;
        RECT  2947.281 1873.0785 3027.281 1953.0785 ;
    END
  END soc_989
  PIN soc_99
    DIRECTION INOUT ;
    USE SIGNAL ;
    PORT
      LAYER L1 ;
        RECT  3104.081 2195.961 3184.081 2275.961 ;
    END
  END soc_99
  PIN soc_990
    DIRECTION INOUT ;
    USE SIGNAL ;
    PORT
      LAYER L1 ;
        RECT  3417.681 1873.0785 3497.681 1953.0785 ;
    END
  END soc_990
  PIN soc_991
    DIRECTION INOUT ;
    USE SIGNAL ;
    PORT
      LAYER L1 ;
        RECT  2633.681 1711.6375 2713.681 1791.6375 ;
    END
  END soc_991
  PIN soc_992
    DIRECTION INOUT ;
    USE SIGNAL ;
    PORT
      LAYER L1 ;
        RECT  2790.481 1711.6375 2870.481 1791.6375 ;
    END
  END soc_992
  PIN soc_993
    DIRECTION INOUT ;
    USE SIGNAL ;
    PORT
      LAYER L1 ;
        RECT  2947.281 1711.6375 3027.281 1791.6375 ;
    END
  END soc_993
  PIN soc_994
    DIRECTION INOUT ;
    USE SIGNAL ;
    PORT
      LAYER L1 ;
        RECT  3417.681 1711.6375 3497.681 1791.6375 ;
    END
  END soc_994
  PIN soc_995
    DIRECTION INOUT ;
    USE SIGNAL ;
    PORT
      LAYER L1 ;
        RECT  2633.681 1550.196 2713.681 1630.196 ;
    END
  END soc_995
  PIN soc_996
    DIRECTION INOUT ;
    USE SIGNAL ;
    PORT
      LAYER L1 ;
        RECT  2790.481 1550.196 2870.481 1630.196 ;
    END
  END soc_996
  PIN soc_997
    DIRECTION INOUT ;
    USE SIGNAL ;
    PORT
      LAYER L1 ;
        RECT  2947.281 1550.196 3027.281 1630.196 ;
    END
  END soc_997
  PIN soc_998
    DIRECTION INOUT ;
    USE SIGNAL ;
    PORT
      LAYER L1 ;
        RECT  3417.681 1550.196 3497.681 1630.196 ;
    END
  END soc_998
  PIN soc_999
    DIRECTION INOUT ;
    USE SIGNAL ;
    PORT
      LAYER L1 ;
        RECT  2633.681 1388.7545 2713.681 1468.7545 ;
    END
  END soc_999
  OBS
  END
END soc
END LIBRARY
